VERSION 5.7 ;
  NOWIREEXTENSIONATPIN ON ;
  DIVIDERCHAR "/" ;
  BUSBITCHARS "[]" ;
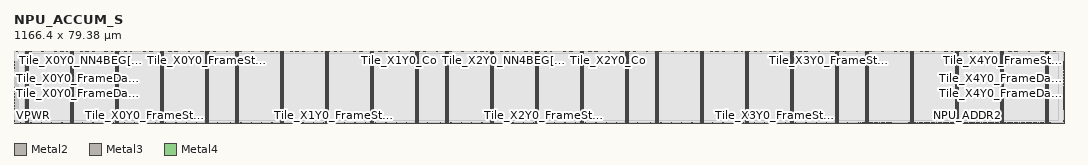
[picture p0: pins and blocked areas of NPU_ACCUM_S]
MACRO NPU_ACCUM_S
  CLASS BLOCK ;
  FOREIGN NPU_ACCUM_S ;
  ORIGIN 0.000 0.000 ;
  SIZE 1166.400 BY 79.380 ;
  PIN NPU_ADDR0
    DIRECTION OUTPUT ;
    USE SIGNAL ;
    ANTENNADIFFAREA 2.647800 ;
    PORT
      LAYER Metal2 ;
        RECT 1055.320 0.000 1055.720 0.400 ;
    END
  END NPU_ADDR0
  PIN NPU_ADDR1
    DIRECTION OUTPUT ;
    USE SIGNAL ;
    ANTENNADIFFAREA 2.647800 ;
    PORT
      LAYER Metal2 ;
        RECT 1057.240 0.000 1057.640 0.400 ;
    END
  END NPU_ADDR1
  PIN NPU_ADDR2
    DIRECTION OUTPUT ;
    USE SIGNAL ;
    ANTENNADIFFAREA 2.647800 ;
    PORT
      LAYER Metal2 ;
        RECT 1059.160 0.000 1059.560 0.400 ;
    END
  END NPU_ADDR2
  PIN NPU_ADDR3
    DIRECTION OUTPUT ;
    USE SIGNAL ;
    ANTENNADIFFAREA 2.647800 ;
    PORT
      LAYER Metal2 ;
        RECT 1061.080 0.000 1061.480 0.400 ;
    END
  END NPU_ADDR3
  PIN NPU_ADDR4
    DIRECTION OUTPUT ;
    USE SIGNAL ;
    ANTENNADIFFAREA 2.647800 ;
    PORT
      LAYER Metal2 ;
        RECT 1063.000 0.000 1063.400 0.400 ;
    END
  END NPU_ADDR4
  PIN NPU_ADDR5
    DIRECTION OUTPUT ;
    USE SIGNAL ;
    ANTENNADIFFAREA 2.647800 ;
    PORT
      LAYER Metal2 ;
        RECT 1064.920 0.000 1065.320 0.400 ;
    END
  END NPU_ADDR5
  PIN NPU_ADDR6
    DIRECTION OUTPUT ;
    USE SIGNAL ;
    ANTENNADIFFAREA 2.647800 ;
    PORT
      LAYER Metal2 ;
        RECT 1066.840 0.000 1067.240 0.400 ;
    END
  END NPU_ADDR6
  PIN NPU_ADDR7
    DIRECTION OUTPUT ;
    USE SIGNAL ;
    ANTENNADIFFAREA 2.647800 ;
    PORT
      LAYER Metal2 ;
        RECT 1068.760 0.000 1069.160 0.400 ;
    END
  END NPU_ADDR7
  PIN NPU_RDATA0
    DIRECTION INPUT ;
    USE SIGNAL ;
    ANTENNAGATEAREA 0.109200 ;
    ANTENNADIFFAREA 2.015400 ;
    PORT
      LAYER Metal2 ;
        RECT 993.880 0.000 994.280 0.400 ;
    END
  END NPU_RDATA0
  PIN NPU_RDATA1
    DIRECTION INPUT ;
    USE SIGNAL ;
    ANTENNAGATEAREA 0.109200 ;
    ANTENNADIFFAREA 2.015400 ;
    PORT
      LAYER Metal2 ;
        RECT 995.800 0.000 996.200 0.400 ;
    END
  END NPU_RDATA1
  PIN NPU_RDATA10
    DIRECTION INPUT ;
    USE SIGNAL ;
    ANTENNAGATEAREA 0.109200 ;
    ANTENNADIFFAREA 2.015400 ;
    PORT
      LAYER Metal2 ;
        RECT 1013.080 0.000 1013.480 0.400 ;
    END
  END NPU_RDATA10
  PIN NPU_RDATA11
    DIRECTION INPUT ;
    USE SIGNAL ;
    ANTENNAGATEAREA 0.109200 ;
    ANTENNADIFFAREA 2.015400 ;
    PORT
      LAYER Metal2 ;
        RECT 1015.000 0.000 1015.400 0.400 ;
    END
  END NPU_RDATA11
  PIN NPU_RDATA12
    DIRECTION INPUT ;
    USE SIGNAL ;
    ANTENNAGATEAREA 0.109200 ;
    ANTENNADIFFAREA 2.015400 ;
    PORT
      LAYER Metal2 ;
        RECT 1016.920 0.000 1017.320 0.400 ;
    END
  END NPU_RDATA12
  PIN NPU_RDATA13
    DIRECTION INPUT ;
    USE SIGNAL ;
    ANTENNAGATEAREA 0.109200 ;
    ANTENNADIFFAREA 2.015400 ;
    PORT
      LAYER Metal2 ;
        RECT 1018.840 0.000 1019.240 0.400 ;
    END
  END NPU_RDATA13
  PIN NPU_RDATA14
    DIRECTION INPUT ;
    USE SIGNAL ;
    ANTENNAGATEAREA 0.109200 ;
    ANTENNADIFFAREA 2.015400 ;
    PORT
      LAYER Metal2 ;
        RECT 1020.760 0.000 1021.160 0.400 ;
    END
  END NPU_RDATA14
  PIN NPU_RDATA15
    DIRECTION INPUT ;
    USE SIGNAL ;
    ANTENNAGATEAREA 0.109200 ;
    ANTENNADIFFAREA 2.015400 ;
    PORT
      LAYER Metal2 ;
        RECT 1022.680 0.000 1023.080 0.400 ;
    END
  END NPU_RDATA15
  PIN NPU_RDATA16
    DIRECTION INPUT ;
    USE SIGNAL ;
    ANTENNAGATEAREA 0.109200 ;
    ANTENNADIFFAREA 2.015400 ;
    PORT
      LAYER Metal2 ;
        RECT 1024.600 0.000 1025.000 0.400 ;
    END
  END NPU_RDATA16
  PIN NPU_RDATA17
    DIRECTION INPUT ;
    USE SIGNAL ;
    ANTENNAGATEAREA 0.109200 ;
    ANTENNADIFFAREA 2.015400 ;
    PORT
      LAYER Metal2 ;
        RECT 1026.520 0.000 1026.920 0.400 ;
    END
  END NPU_RDATA17
  PIN NPU_RDATA18
    DIRECTION INPUT ;
    USE SIGNAL ;
    ANTENNAGATEAREA 0.109200 ;
    ANTENNADIFFAREA 2.015400 ;
    PORT
      LAYER Metal2 ;
        RECT 1028.440 0.000 1028.840 0.400 ;
    END
  END NPU_RDATA18
  PIN NPU_RDATA19
    DIRECTION INPUT ;
    USE SIGNAL ;
    ANTENNAGATEAREA 0.109200 ;
    ANTENNADIFFAREA 2.015400 ;
    PORT
      LAYER Metal2 ;
        RECT 1030.360 0.000 1030.760 0.400 ;
    END
  END NPU_RDATA19
  PIN NPU_RDATA2
    DIRECTION INPUT ;
    USE SIGNAL ;
    ANTENNAGATEAREA 0.109200 ;
    ANTENNADIFFAREA 2.015400 ;
    PORT
      LAYER Metal2 ;
        RECT 997.720 0.000 998.120 0.400 ;
    END
  END NPU_RDATA2
  PIN NPU_RDATA20
    DIRECTION INPUT ;
    USE SIGNAL ;
    ANTENNAGATEAREA 0.109200 ;
    ANTENNADIFFAREA 2.015400 ;
    PORT
      LAYER Metal2 ;
        RECT 1032.280 0.000 1032.680 0.400 ;
    END
  END NPU_RDATA20
  PIN NPU_RDATA21
    DIRECTION INPUT ;
    USE SIGNAL ;
    ANTENNAGATEAREA 0.109200 ;
    ANTENNADIFFAREA 2.015400 ;
    PORT
      LAYER Metal2 ;
        RECT 1034.200 0.000 1034.600 0.400 ;
    END
  END NPU_RDATA21
  PIN NPU_RDATA22
    DIRECTION INPUT ;
    USE SIGNAL ;
    ANTENNAGATEAREA 0.109200 ;
    ANTENNADIFFAREA 2.015400 ;
    PORT
      LAYER Metal2 ;
        RECT 1036.120 0.000 1036.520 0.400 ;
    END
  END NPU_RDATA22
  PIN NPU_RDATA23
    DIRECTION INPUT ;
    USE SIGNAL ;
    ANTENNAGATEAREA 0.109200 ;
    ANTENNADIFFAREA 2.015400 ;
    PORT
      LAYER Metal2 ;
        RECT 1038.040 0.000 1038.440 0.400 ;
    END
  END NPU_RDATA23
  PIN NPU_RDATA24
    DIRECTION INPUT ;
    USE SIGNAL ;
    ANTENNAGATEAREA 0.109200 ;
    ANTENNADIFFAREA 2.015400 ;
    PORT
      LAYER Metal2 ;
        RECT 1039.960 0.000 1040.360 0.400 ;
    END
  END NPU_RDATA24
  PIN NPU_RDATA25
    DIRECTION INPUT ;
    USE SIGNAL ;
    ANTENNAGATEAREA 0.109200 ;
    ANTENNADIFFAREA 2.015400 ;
    PORT
      LAYER Metal2 ;
        RECT 1041.880 0.000 1042.280 0.400 ;
    END
  END NPU_RDATA25
  PIN NPU_RDATA26
    DIRECTION INPUT ;
    USE SIGNAL ;
    ANTENNAGATEAREA 0.109200 ;
    ANTENNADIFFAREA 2.015400 ;
    PORT
      LAYER Metal2 ;
        RECT 1043.800 0.000 1044.200 0.400 ;
    END
  END NPU_RDATA26
  PIN NPU_RDATA27
    DIRECTION INPUT ;
    USE SIGNAL ;
    ANTENNAGATEAREA 0.109200 ;
    ANTENNADIFFAREA 2.015400 ;
    PORT
      LAYER Metal2 ;
        RECT 1045.720 0.000 1046.120 0.400 ;
    END
  END NPU_RDATA27
  PIN NPU_RDATA28
    DIRECTION INPUT ;
    USE SIGNAL ;
    ANTENNAGATEAREA 0.109200 ;
    ANTENNADIFFAREA 2.015400 ;
    PORT
      LAYER Metal2 ;
        RECT 1047.640 0.000 1048.040 0.400 ;
    END
  END NPU_RDATA28
  PIN NPU_RDATA29
    DIRECTION INPUT ;
    USE SIGNAL ;
    ANTENNAGATEAREA 0.109200 ;
    ANTENNADIFFAREA 2.015400 ;
    PORT
      LAYER Metal2 ;
        RECT 1049.560 0.000 1049.960 0.400 ;
    END
  END NPU_RDATA29
  PIN NPU_RDATA3
    DIRECTION INPUT ;
    USE SIGNAL ;
    ANTENNAGATEAREA 0.109200 ;
    ANTENNADIFFAREA 2.015400 ;
    PORT
      LAYER Metal2 ;
        RECT 999.640 0.000 1000.040 0.400 ;
    END
  END NPU_RDATA3
  PIN NPU_RDATA30
    DIRECTION INPUT ;
    USE SIGNAL ;
    ANTENNAGATEAREA 0.109200 ;
    ANTENNADIFFAREA 2.015400 ;
    PORT
      LAYER Metal2 ;
        RECT 1051.480 0.000 1051.880 0.400 ;
    END
  END NPU_RDATA30
  PIN NPU_RDATA31
    DIRECTION INPUT ;
    USE SIGNAL ;
    ANTENNAGATEAREA 0.109200 ;
    ANTENNADIFFAREA 2.015400 ;
    PORT
      LAYER Metal2 ;
        RECT 1053.400 0.000 1053.800 0.400 ;
    END
  END NPU_RDATA31
  PIN NPU_RDATA4
    DIRECTION INPUT ;
    USE SIGNAL ;
    ANTENNAGATEAREA 0.109200 ;
    ANTENNADIFFAREA 2.015400 ;
    PORT
      LAYER Metal2 ;
        RECT 1001.560 0.000 1001.960 0.400 ;
    END
  END NPU_RDATA4
  PIN NPU_RDATA5
    DIRECTION INPUT ;
    USE SIGNAL ;
    ANTENNAGATEAREA 0.109200 ;
    ANTENNADIFFAREA 2.015400 ;
    PORT
      LAYER Metal2 ;
        RECT 1003.480 0.000 1003.880 0.400 ;
    END
  END NPU_RDATA5
  PIN NPU_RDATA6
    DIRECTION INPUT ;
    USE SIGNAL ;
    ANTENNAGATEAREA 0.109200 ;
    ANTENNADIFFAREA 2.015400 ;
    PORT
      LAYER Metal2 ;
        RECT 1005.400 0.000 1005.800 0.400 ;
    END
  END NPU_RDATA6
  PIN NPU_RDATA7
    DIRECTION INPUT ;
    USE SIGNAL ;
    ANTENNAGATEAREA 0.109200 ;
    ANTENNADIFFAREA 2.015400 ;
    PORT
      LAYER Metal2 ;
        RECT 1007.320 0.000 1007.720 0.400 ;
    END
  END NPU_RDATA7
  PIN NPU_RDATA8
    DIRECTION INPUT ;
    USE SIGNAL ;
    ANTENNAGATEAREA 0.109200 ;
    ANTENNADIFFAREA 2.015400 ;
    PORT
      LAYER Metal2 ;
        RECT 1009.240 0.000 1009.640 0.400 ;
    END
  END NPU_RDATA8
  PIN NPU_RDATA9
    DIRECTION INPUT ;
    USE SIGNAL ;
    ANTENNAGATEAREA 0.109200 ;
    ANTENNADIFFAREA 2.015400 ;
    PORT
      LAYER Metal2 ;
        RECT 1011.160 0.000 1011.560 0.400 ;
    END
  END NPU_RDATA9
  PIN NPU_READ_BANK_SEL0
    DIRECTION OUTPUT ;
    USE SIGNAL ;
    ANTENNADIFFAREA 2.647800 ;
    PORT
      LAYER Metal2 ;
        RECT 1147.480 0.000 1147.880 0.400 ;
    END
  END NPU_READ_BANK_SEL0
  PIN NPU_READ_BANK_SEL1
    DIRECTION OUTPUT ;
    USE SIGNAL ;
    ANTENNADIFFAREA 2.647800 ;
    PORT
      LAYER Metal2 ;
        RECT 1149.400 0.000 1149.800 0.400 ;
    END
  END NPU_READ_BANK_SEL1
  PIN NPU_READ_BANK_SEL2
    DIRECTION OUTPUT ;
    USE SIGNAL ;
    ANTENNADIFFAREA 2.647800 ;
    PORT
      LAYER Metal2 ;
        RECT 1151.320 0.000 1151.720 0.400 ;
    END
  END NPU_READ_BANK_SEL2
  PIN NPU_WDATA0
    DIRECTION OUTPUT ;
    USE SIGNAL ;
    ANTENNADIFFAREA 2.647800 ;
    PORT
      LAYER Metal2 ;
        RECT 1086.040 0.000 1086.440 0.400 ;
    END
  END NPU_WDATA0
  PIN NPU_WDATA1
    DIRECTION OUTPUT ;
    USE SIGNAL ;
    ANTENNADIFFAREA 2.647800 ;
    PORT
      LAYER Metal2 ;
        RECT 1087.960 0.000 1088.360 0.400 ;
    END
  END NPU_WDATA1
  PIN NPU_WDATA10
    DIRECTION OUTPUT ;
    USE SIGNAL ;
    ANTENNADIFFAREA 2.647800 ;
    PORT
      LAYER Metal2 ;
        RECT 1105.240 0.000 1105.640 0.400 ;
    END
  END NPU_WDATA10
  PIN NPU_WDATA11
    DIRECTION OUTPUT ;
    USE SIGNAL ;
    ANTENNADIFFAREA 2.647800 ;
    PORT
      LAYER Metal2 ;
        RECT 1107.160 0.000 1107.560 0.400 ;
    END
  END NPU_WDATA11
  PIN NPU_WDATA12
    DIRECTION OUTPUT ;
    USE SIGNAL ;
    ANTENNADIFFAREA 2.647800 ;
    PORT
      LAYER Metal2 ;
        RECT 1109.080 0.000 1109.480 0.400 ;
    END
  END NPU_WDATA12
  PIN NPU_WDATA13
    DIRECTION OUTPUT ;
    USE SIGNAL ;
    ANTENNADIFFAREA 2.647800 ;
    PORT
      LAYER Metal2 ;
        RECT 1111.000 0.000 1111.400 0.400 ;
    END
  END NPU_WDATA13
  PIN NPU_WDATA14
    DIRECTION OUTPUT ;
    USE SIGNAL ;
    ANTENNADIFFAREA 2.647800 ;
    PORT
      LAYER Metal2 ;
        RECT 1112.920 0.000 1113.320 0.400 ;
    END
  END NPU_WDATA14
  PIN NPU_WDATA15
    DIRECTION OUTPUT ;
    USE SIGNAL ;
    ANTENNADIFFAREA 2.647800 ;
    PORT
      LAYER Metal2 ;
        RECT 1114.840 0.000 1115.240 0.400 ;
    END
  END NPU_WDATA15
  PIN NPU_WDATA16
    DIRECTION OUTPUT ;
    USE SIGNAL ;
    ANTENNADIFFAREA 2.647800 ;
    PORT
      LAYER Metal2 ;
        RECT 1116.760 0.000 1117.160 0.400 ;
    END
  END NPU_WDATA16
  PIN NPU_WDATA17
    DIRECTION OUTPUT ;
    USE SIGNAL ;
    ANTENNADIFFAREA 2.647800 ;
    PORT
      LAYER Metal2 ;
        RECT 1118.680 0.000 1119.080 0.400 ;
    END
  END NPU_WDATA17
  PIN NPU_WDATA18
    DIRECTION OUTPUT ;
    USE SIGNAL ;
    ANTENNADIFFAREA 2.647800 ;
    PORT
      LAYER Metal2 ;
        RECT 1120.600 0.000 1121.000 0.400 ;
    END
  END NPU_WDATA18
  PIN NPU_WDATA19
    DIRECTION OUTPUT ;
    USE SIGNAL ;
    ANTENNADIFFAREA 2.647800 ;
    PORT
      LAYER Metal2 ;
        RECT 1122.520 0.000 1122.920 0.400 ;
    END
  END NPU_WDATA19
  PIN NPU_WDATA2
    DIRECTION OUTPUT ;
    USE SIGNAL ;
    ANTENNADIFFAREA 2.647800 ;
    PORT
      LAYER Metal2 ;
        RECT 1089.880 0.000 1090.280 0.400 ;
    END
  END NPU_WDATA2
  PIN NPU_WDATA20
    DIRECTION OUTPUT ;
    USE SIGNAL ;
    ANTENNADIFFAREA 2.647800 ;
    PORT
      LAYER Metal2 ;
        RECT 1124.440 0.000 1124.840 0.400 ;
    END
  END NPU_WDATA20
  PIN NPU_WDATA21
    DIRECTION OUTPUT ;
    USE SIGNAL ;
    ANTENNADIFFAREA 2.647800 ;
    PORT
      LAYER Metal2 ;
        RECT 1126.360 0.000 1126.760 0.400 ;
    END
  END NPU_WDATA21
  PIN NPU_WDATA22
    DIRECTION OUTPUT ;
    USE SIGNAL ;
    ANTENNADIFFAREA 2.647800 ;
    PORT
      LAYER Metal2 ;
        RECT 1128.280 0.000 1128.680 0.400 ;
    END
  END NPU_WDATA22
  PIN NPU_WDATA23
    DIRECTION OUTPUT ;
    USE SIGNAL ;
    ANTENNADIFFAREA 2.647800 ;
    PORT
      LAYER Metal2 ;
        RECT 1130.200 0.000 1130.600 0.400 ;
    END
  END NPU_WDATA23
  PIN NPU_WDATA24
    DIRECTION OUTPUT ;
    USE SIGNAL ;
    ANTENNADIFFAREA 2.647800 ;
    PORT
      LAYER Metal2 ;
        RECT 1132.120 0.000 1132.520 0.400 ;
    END
  END NPU_WDATA24
  PIN NPU_WDATA25
    DIRECTION OUTPUT ;
    USE SIGNAL ;
    ANTENNADIFFAREA 2.647800 ;
    PORT
      LAYER Metal2 ;
        RECT 1134.040 0.000 1134.440 0.400 ;
    END
  END NPU_WDATA25
  PIN NPU_WDATA26
    DIRECTION OUTPUT ;
    USE SIGNAL ;
    ANTENNADIFFAREA 2.647800 ;
    PORT
      LAYER Metal2 ;
        RECT 1135.960 0.000 1136.360 0.400 ;
    END
  END NPU_WDATA26
  PIN NPU_WDATA27
    DIRECTION OUTPUT ;
    USE SIGNAL ;
    ANTENNADIFFAREA 2.647800 ;
    PORT
      LAYER Metal2 ;
        RECT 1137.880 0.000 1138.280 0.400 ;
    END
  END NPU_WDATA27
  PIN NPU_WDATA28
    DIRECTION OUTPUT ;
    USE SIGNAL ;
    ANTENNADIFFAREA 2.647800 ;
    PORT
      LAYER Metal2 ;
        RECT 1139.800 0.000 1140.200 0.400 ;
    END
  END NPU_WDATA28
  PIN NPU_WDATA29
    DIRECTION OUTPUT ;
    USE SIGNAL ;
    ANTENNADIFFAREA 2.647800 ;
    PORT
      LAYER Metal2 ;
        RECT 1141.720 0.000 1142.120 0.400 ;
    END
  END NPU_WDATA29
  PIN NPU_WDATA3
    DIRECTION OUTPUT ;
    USE SIGNAL ;
    ANTENNADIFFAREA 2.647800 ;
    PORT
      LAYER Metal2 ;
        RECT 1091.800 0.000 1092.200 0.400 ;
    END
  END NPU_WDATA3
  PIN NPU_WDATA30
    DIRECTION OUTPUT ;
    USE SIGNAL ;
    ANTENNADIFFAREA 2.647800 ;
    PORT
      LAYER Metal2 ;
        RECT 1143.640 0.000 1144.040 0.400 ;
    END
  END NPU_WDATA30
  PIN NPU_WDATA31
    DIRECTION OUTPUT ;
    USE SIGNAL ;
    ANTENNADIFFAREA 2.647800 ;
    PORT
      LAYER Metal2 ;
        RECT 1145.560 0.000 1145.960 0.400 ;
    END
  END NPU_WDATA31
  PIN NPU_WDATA4
    DIRECTION OUTPUT ;
    USE SIGNAL ;
    ANTENNADIFFAREA 2.647800 ;
    PORT
      LAYER Metal2 ;
        RECT 1093.720 0.000 1094.120 0.400 ;
    END
  END NPU_WDATA4
  PIN NPU_WDATA5
    DIRECTION OUTPUT ;
    USE SIGNAL ;
    ANTENNADIFFAREA 2.647800 ;
    PORT
      LAYER Metal2 ;
        RECT 1095.640 0.000 1096.040 0.400 ;
    END
  END NPU_WDATA5
  PIN NPU_WDATA6
    DIRECTION OUTPUT ;
    USE SIGNAL ;
    ANTENNADIFFAREA 2.647800 ;
    PORT
      LAYER Metal2 ;
        RECT 1097.560 0.000 1097.960 0.400 ;
    END
  END NPU_WDATA6
  PIN NPU_WDATA7
    DIRECTION OUTPUT ;
    USE SIGNAL ;
    ANTENNADIFFAREA 2.647800 ;
    PORT
      LAYER Metal2 ;
        RECT 1099.480 0.000 1099.880 0.400 ;
    END
  END NPU_WDATA7
  PIN NPU_WDATA8
    DIRECTION OUTPUT ;
    USE SIGNAL ;
    ANTENNADIFFAREA 2.647800 ;
    PORT
      LAYER Metal2 ;
        RECT 1101.400 0.000 1101.800 0.400 ;
    END
  END NPU_WDATA8
  PIN NPU_WDATA9
    DIRECTION OUTPUT ;
    USE SIGNAL ;
    ANTENNADIFFAREA 2.647800 ;
    PORT
      LAYER Metal2 ;
        RECT 1103.320 0.000 1103.720 0.400 ;
    END
  END NPU_WDATA9
  PIN NPU_WE0
    DIRECTION OUTPUT ;
    USE SIGNAL ;
    ANTENNADIFFAREA 2.647800 ;
    PORT
      LAYER Metal2 ;
        RECT 1070.680 0.000 1071.080 0.400 ;
    END
  END NPU_WE0
  PIN NPU_WE1
    DIRECTION OUTPUT ;
    USE SIGNAL ;
    ANTENNADIFFAREA 2.647800 ;
    PORT
      LAYER Metal2 ;
        RECT 1072.600 0.000 1073.000 0.400 ;
    END
  END NPU_WE1
  PIN NPU_WE2
    DIRECTION OUTPUT ;
    USE SIGNAL ;
    ANTENNADIFFAREA 2.647800 ;
    PORT
      LAYER Metal2 ;
        RECT 1074.520 0.000 1074.920 0.400 ;
    END
  END NPU_WE2
  PIN NPU_WE3
    DIRECTION OUTPUT ;
    USE SIGNAL ;
    ANTENNADIFFAREA 2.647800 ;
    PORT
      LAYER Metal2 ;
        RECT 1076.440 0.000 1076.840 0.400 ;
    END
  END NPU_WE3
  PIN NPU_WE4
    DIRECTION OUTPUT ;
    USE SIGNAL ;
    ANTENNADIFFAREA 2.647800 ;
    PORT
      LAYER Metal2 ;
        RECT 1078.360 0.000 1078.760 0.400 ;
    END
  END NPU_WE4
  PIN NPU_WE5
    DIRECTION OUTPUT ;
    USE SIGNAL ;
    ANTENNADIFFAREA 2.647800 ;
    PORT
      LAYER Metal2 ;
        RECT 1080.280 0.000 1080.680 0.400 ;
    END
  END NPU_WE5
  PIN NPU_WE6
    DIRECTION OUTPUT ;
    USE SIGNAL ;
    ANTENNADIFFAREA 2.647800 ;
    PORT
      LAYER Metal2 ;
        RECT 1082.200 0.000 1082.600 0.400 ;
    END
  END NPU_WE6
  PIN NPU_WE7
    DIRECTION OUTPUT ;
    USE SIGNAL ;
    ANTENNADIFFAREA 2.647800 ;
    PORT
      LAYER Metal2 ;
        RECT 1084.120 0.000 1084.520 0.400 ;
    END
  END NPU_WE7
  PIN Tile_X0Y0_Co
    DIRECTION OUTPUT ;
    USE SIGNAL ;
    ANTENNADIFFAREA 2.314600 ;
    PORT
      LAYER Metal2 ;
        RECT 194.200 78.980 194.600 79.380 ;
    END
  END Tile_X0Y0_Co
  PIN Tile_X0Y0_FrameData[0]
    DIRECTION INPUT ;
    USE SIGNAL ;
    ANTENNAGATEAREA 2.349100 ;
    ANTENNADIFFAREA 78.600601 ;
    PORT
      LAYER Metal3 ;
        RECT 0.000 15.340 0.400 15.740 ;
    END
  END Tile_X0Y0_FrameData[0]
  PIN Tile_X0Y0_FrameData[10]
    DIRECTION INPUT ;
    USE SIGNAL ;
    ANTENNAGATEAREA 2.349100 ;
    ANTENNADIFFAREA 340.602600 ;
    PORT
      LAYER Metal3 ;
        RECT 0.000 32.140 0.400 32.540 ;
    END
  END Tile_X0Y0_FrameData[10]
  PIN Tile_X0Y0_FrameData[11]
    DIRECTION INPUT ;
    USE SIGNAL ;
    ANTENNAGATEAREA 2.349100 ;
    ANTENNADIFFAREA 235.801788 ;
    PORT
      LAYER Metal3 ;
        RECT 0.000 33.820 0.400 34.220 ;
    END
  END Tile_X0Y0_FrameData[11]
  PIN Tile_X0Y0_FrameData[12]
    DIRECTION INPUT ;
    USE SIGNAL ;
    ANTENNAGATEAREA 2.349100 ;
    ANTENNADIFFAREA 340.602600 ;
    PORT
      LAYER Metal3 ;
        RECT 0.000 35.500 0.400 35.900 ;
    END
  END Tile_X0Y0_FrameData[12]
  PIN Tile_X0Y0_FrameData[13]
    DIRECTION INPUT ;
    USE SIGNAL ;
    ANTENNAGATEAREA 2.349100 ;
    ANTENNADIFFAREA 52.400398 ;
    PORT
      LAYER Metal3 ;
        RECT 0.000 37.180 0.400 37.580 ;
    END
  END Tile_X0Y0_FrameData[13]
  PIN Tile_X0Y0_FrameData[14]
    DIRECTION INPUT ;
    USE SIGNAL ;
    ANTENNAGATEAREA 2.349100 ;
    ANTENNADIFFAREA 157.201202 ;
    PORT
      LAYER Metal3 ;
        RECT 0.000 38.860 0.400 39.260 ;
    END
  END Tile_X0Y0_FrameData[14]
  PIN Tile_X0Y0_FrameData[15]
    DIRECTION INPUT ;
    USE SIGNAL ;
    ANTENNAGATEAREA 2.349100 ;
    ANTENNADIFFAREA 340.602600 ;
    PORT
      LAYER Metal3 ;
        RECT 0.000 40.540 0.400 40.940 ;
    END
  END Tile_X0Y0_FrameData[15]
  PIN Tile_X0Y0_FrameData[16]
    DIRECTION INPUT ;
    USE SIGNAL ;
    ANTENNAGATEAREA 2.710500 ;
    ANTENNADIFFAREA 60.461998 ;
    PORT
      LAYER Metal3 ;
        RECT 0.000 42.220 0.400 42.620 ;
    END
  END Tile_X0Y0_FrameData[16]
  PIN Tile_X0Y0_FrameData[17]
    DIRECTION INPUT ;
    USE SIGNAL ;
    ANTENNAGATEAREA 2.710500 ;
    ANTENNADIFFAREA 453.464996 ;
    PORT
      LAYER Metal3 ;
        RECT 0.000 43.900 0.400 44.300 ;
    END
  END Tile_X0Y0_FrameData[17]
  PIN Tile_X0Y0_FrameData[18]
    DIRECTION INPUT ;
    USE SIGNAL ;
    ANTENNAGATEAREA 2.891200 ;
    ANTENNADIFFAREA 451.449585 ;
    PORT
      LAYER Metal3 ;
        RECT 0.000 45.580 0.400 45.980 ;
    END
  END Tile_X0Y0_FrameData[18]
  PIN Tile_X0Y0_FrameData[19]
    DIRECTION INPUT ;
    USE SIGNAL ;
    ANTENNAGATEAREA 2.891200 ;
    ANTENNADIFFAREA 193.478394 ;
    PORT
      LAYER Metal3 ;
        RECT 0.000 47.260 0.400 47.660 ;
    END
  END Tile_X0Y0_FrameData[19]
  PIN Tile_X0Y0_FrameData[1]
    DIRECTION INPUT ;
    USE SIGNAL ;
    ANTENNAGATEAREA 2.349100 ;
    ANTENNADIFFAREA 235.801788 ;
    PORT
      LAYER Metal3 ;
        RECT 0.000 17.020 0.400 17.420 ;
    END
  END Tile_X0Y0_FrameData[1]
  PIN Tile_X0Y0_FrameData[20]
    DIRECTION INPUT ;
    USE SIGNAL ;
    ANTENNAGATEAREA 2.891200 ;
    ANTENNADIFFAREA 515.942383 ;
    PORT
      LAYER Metal3 ;
        RECT 0.000 48.940 0.400 49.340 ;
    END
  END Tile_X0Y0_FrameData[20]
  PIN Tile_X0Y0_FrameData[21]
    DIRECTION INPUT ;
    USE SIGNAL ;
    ANTENNAGATEAREA 2.891200 ;
    ANTENNADIFFAREA 128.985596 ;
    PORT
      LAYER Metal3 ;
        RECT 0.000 50.620 0.400 51.020 ;
    END
  END Tile_X0Y0_FrameData[21]
  PIN Tile_X0Y0_FrameData[22]
    DIRECTION INPUT ;
    USE SIGNAL ;
    ANTENNAGATEAREA 2.891200 ;
    ANTENNADIFFAREA 386.956787 ;
    PORT
      LAYER Metal3 ;
        RECT 0.000 52.300 0.400 52.700 ;
    END
  END Tile_X0Y0_FrameData[22]
  PIN Tile_X0Y0_FrameData[23]
    DIRECTION INPUT ;
    USE SIGNAL ;
    ANTENNAGATEAREA 2.891200 ;
    ANTENNADIFFAREA 32.246399 ;
    PORT
      LAYER Metal3 ;
        RECT 0.000 53.980 0.400 54.380 ;
    END
  END Tile_X0Y0_FrameData[23]
  PIN Tile_X0Y0_FrameData[24]
    DIRECTION INPUT ;
    USE SIGNAL ;
    ANTENNAGATEAREA 2.891200 ;
    ANTENNADIFFAREA 419.203186 ;
    PORT
      LAYER Metal3 ;
        RECT 0.000 55.660 0.400 56.060 ;
    END
  END Tile_X0Y0_FrameData[24]
  PIN Tile_X0Y0_FrameData[25]
    DIRECTION INPUT ;
    USE SIGNAL ;
    ANTENNAGATEAREA 2.891200 ;
    ANTENNADIFFAREA 64.492798 ;
    PORT
      LAYER Metal3 ;
        RECT 0.000 57.340 0.400 57.740 ;
    END
  END Tile_X0Y0_FrameData[25]
  PIN Tile_X0Y0_FrameData[26]
    DIRECTION INPUT ;
    USE SIGNAL ;
    ANTENNAGATEAREA 2.891200 ;
    ANTENNADIFFAREA 193.478394 ;
    PORT
      LAYER Metal3 ;
        RECT 0.000 59.020 0.400 59.420 ;
    END
  END Tile_X0Y0_FrameData[26]
  PIN Tile_X0Y0_FrameData[27]
    DIRECTION INPUT ;
    USE SIGNAL ;
    ANTENNAGATEAREA 2.891200 ;
    ANTENNADIFFAREA 515.942383 ;
    PORT
      LAYER Metal3 ;
        RECT 0.000 60.700 0.400 61.100 ;
    END
  END Tile_X0Y0_FrameData[27]
  PIN Tile_X0Y0_FrameData[28]
    DIRECTION INPUT ;
    USE SIGNAL ;
    ANTENNAGATEAREA 2.891200 ;
    ANTENNADIFFAREA 344.633392 ;
    PORT
      LAYER Metal3 ;
        RECT 0.000 62.380 0.400 62.780 ;
    END
  END Tile_X0Y0_FrameData[28]
  PIN Tile_X0Y0_FrameData[29]
    DIRECTION INPUT ;
    USE SIGNAL ;
    ANTENNAGATEAREA 2.891200 ;
    ANTENNADIFFAREA 163.247391 ;
    PORT
      LAYER Metal3 ;
        RECT 0.000 64.060 0.400 64.460 ;
    END
  END Tile_X0Y0_FrameData[29]
  PIN Tile_X0Y0_FrameData[2]
    DIRECTION INPUT ;
    USE SIGNAL ;
    ANTENNAGATEAREA 2.349100 ;
    ANTENNADIFFAREA 102.785400 ;
    PORT
      LAYER Metal3 ;
        RECT 0.000 18.700 0.400 19.100 ;
    END
  END Tile_X0Y0_FrameData[2]
  PIN Tile_X0Y0_FrameData[30]
    DIRECTION INPUT ;
    USE SIGNAL ;
    ANTENNAGATEAREA 2.891200 ;
    ANTENNADIFFAREA 72.554398 ;
    PORT
      LAYER Metal3 ;
        RECT 0.000 65.740 0.400 66.140 ;
    END
  END Tile_X0Y0_FrameData[30]
  PIN Tile_X0Y0_FrameData[31]
    DIRECTION INPUT ;
    USE SIGNAL ;
    ANTENNAGATEAREA 2.891200 ;
    ANTENNADIFFAREA 515.942383 ;
    PORT
      LAYER Metal3 ;
        RECT 0.000 67.420 0.400 67.820 ;
    END
  END Tile_X0Y0_FrameData[31]
  PIN Tile_X0Y0_FrameData[3]
    DIRECTION INPUT ;
    USE SIGNAL ;
    ANTENNAGATEAREA 2.349100 ;
    PORT
      LAYER Metal3 ;
        RECT 0.000 20.380 0.400 20.780 ;
    END
  END Tile_X0Y0_FrameData[3]
  PIN Tile_X0Y0_FrameData[4]
    DIRECTION INPUT ;
    USE SIGNAL ;
    ANTENNAGATEAREA 2.349100 ;
    ANTENNADIFFAREA 340.602600 ;
    PORT
      LAYER Metal3 ;
        RECT 0.000 22.060 0.400 22.460 ;
    END
  END Tile_X0Y0_FrameData[4]
  PIN Tile_X0Y0_FrameData[5]
    DIRECTION INPUT ;
    USE SIGNAL ;
    ANTENNAGATEAREA 2.349100 ;
    ANTENNADIFFAREA 52.400398 ;
    PORT
      LAYER Metal3 ;
        RECT 0.000 23.740 0.400 24.140 ;
    END
  END Tile_X0Y0_FrameData[5]
  PIN Tile_X0Y0_FrameData[6]
    DIRECTION INPUT ;
    USE SIGNAL ;
    ANTENNAGATEAREA 2.349100 ;
    ANTENNADIFFAREA 340.602600 ;
    PORT
      LAYER Metal3 ;
        RECT 0.000 25.420 0.400 25.820 ;
    END
  END Tile_X0Y0_FrameData[6]
  PIN Tile_X0Y0_FrameData[7]
    DIRECTION INPUT ;
    USE SIGNAL ;
    ANTENNAGATEAREA 2.349100 ;
    ANTENNADIFFAREA 235.801788 ;
    PORT
      LAYER Metal3 ;
        RECT 0.000 27.100 0.400 27.500 ;
    END
  END Tile_X0Y0_FrameData[7]
  PIN Tile_X0Y0_FrameData[8]
    DIRECTION INPUT ;
    USE SIGNAL ;
    ANTENNAGATEAREA 2.349100 ;
    ANTENNADIFFAREA 340.602600 ;
    PORT
      LAYER Metal3 ;
        RECT 0.000 28.780 0.400 29.180 ;
    END
  END Tile_X0Y0_FrameData[8]
  PIN Tile_X0Y0_FrameData[9]
    DIRECTION INPUT ;
    USE SIGNAL ;
    ANTENNAGATEAREA 2.349100 ;
    ANTENNADIFFAREA 340.602600 ;
    PORT
      LAYER Metal3 ;
        RECT 0.000 30.460 0.400 30.860 ;
    END
  END Tile_X0Y0_FrameData[9]
  PIN Tile_X0Y0_FrameStrobe[0]
    DIRECTION INPUT ;
    USE SIGNAL ;
    ANTENNAGATEAREA 11.745500 ;
    PORT
      LAYER Metal2 ;
        RECT 7.000 0.000 7.400 0.400 ;
    END
  END Tile_X0Y0_FrameStrobe[0]
  PIN Tile_X0Y0_FrameStrobe[10]
    DIRECTION INPUT ;
    USE SIGNAL ;
    ANTENNAGATEAREA 0.180700 ;
    PORT
      LAYER Metal2 ;
        RECT 122.200 0.000 122.600 0.400 ;
    END
  END Tile_X0Y0_FrameStrobe[10]
  PIN Tile_X0Y0_FrameStrobe[11]
    DIRECTION INPUT ;
    USE SIGNAL ;
    ANTENNAGATEAREA 0.180700 ;
    PORT
      LAYER Metal2 ;
        RECT 133.720 0.000 134.120 0.400 ;
    END
  END Tile_X0Y0_FrameStrobe[11]
  PIN Tile_X0Y0_FrameStrobe[12]
    DIRECTION INPUT ;
    USE SIGNAL ;
    ANTENNAGATEAREA 0.180700 ;
    PORT
      LAYER Metal2 ;
        RECT 145.240 0.000 145.640 0.400 ;
    END
  END Tile_X0Y0_FrameStrobe[12]
  PIN Tile_X0Y0_FrameStrobe[13]
    DIRECTION INPUT ;
    USE SIGNAL ;
    ANTENNAGATEAREA 0.180700 ;
    PORT
      LAYER Metal2 ;
        RECT 156.760 0.000 157.160 0.400 ;
    END
  END Tile_X0Y0_FrameStrobe[13]
  PIN Tile_X0Y0_FrameStrobe[14]
    DIRECTION INPUT ;
    USE SIGNAL ;
    ANTENNAGATEAREA 0.180700 ;
    PORT
      LAYER Metal2 ;
        RECT 168.280 0.000 168.680 0.400 ;
    END
  END Tile_X0Y0_FrameStrobe[14]
  PIN Tile_X0Y0_FrameStrobe[15]
    DIRECTION INPUT ;
    USE SIGNAL ;
    ANTENNAGATEAREA 0.180700 ;
    PORT
      LAYER Metal2 ;
        RECT 179.800 0.000 180.200 0.400 ;
    END
  END Tile_X0Y0_FrameStrobe[15]
  PIN Tile_X0Y0_FrameStrobe[16]
    DIRECTION INPUT ;
    USE SIGNAL ;
    ANTENNAGATEAREA 0.180700 ;
    PORT
      LAYER Metal2 ;
        RECT 191.320 0.000 191.720 0.400 ;
    END
  END Tile_X0Y0_FrameStrobe[16]
  PIN Tile_X0Y0_FrameStrobe[17]
    DIRECTION INPUT ;
    USE SIGNAL ;
    ANTENNAGATEAREA 0.180700 ;
    PORT
      LAYER Metal2 ;
        RECT 202.840 0.000 203.240 0.400 ;
    END
  END Tile_X0Y0_FrameStrobe[17]
  PIN Tile_X0Y0_FrameStrobe[18]
    DIRECTION INPUT ;
    USE SIGNAL ;
    ANTENNAGATEAREA 0.180700 ;
    PORT
      LAYER Metal2 ;
        RECT 214.360 0.000 214.760 0.400 ;
    END
  END Tile_X0Y0_FrameStrobe[18]
  PIN Tile_X0Y0_FrameStrobe[19]
    DIRECTION INPUT ;
    USE SIGNAL ;
    ANTENNAGATEAREA 0.180700 ;
    PORT
      LAYER Metal2 ;
        RECT 225.880 0.000 226.280 0.400 ;
    END
  END Tile_X0Y0_FrameStrobe[19]
  PIN Tile_X0Y0_FrameStrobe[1]
    DIRECTION INPUT ;
    USE SIGNAL ;
    ANTENNAGATEAREA 11.745500 ;
    PORT
      LAYER Metal2 ;
        RECT 18.520 0.000 18.920 0.400 ;
    END
  END Tile_X0Y0_FrameStrobe[1]
  PIN Tile_X0Y0_FrameStrobe[2]
    DIRECTION INPUT ;
    USE SIGNAL ;
    ANTENNAGATEAREA 11.745500 ;
    PORT
      LAYER Metal2 ;
        RECT 30.040 0.000 30.440 0.400 ;
    END
  END Tile_X0Y0_FrameStrobe[2]
  PIN Tile_X0Y0_FrameStrobe[3]
    DIRECTION INPUT ;
    USE SIGNAL ;
    ANTENNAGATEAREA 5.963100 ;
    PORT
      LAYER Metal2 ;
        RECT 41.560 0.000 41.960 0.400 ;
    END
  END Tile_X0Y0_FrameStrobe[3]
  PIN Tile_X0Y0_FrameStrobe[4]
    DIRECTION INPUT ;
    USE SIGNAL ;
    ANTENNAGATEAREA 0.180700 ;
    PORT
      LAYER Metal2 ;
        RECT 53.080 0.000 53.480 0.400 ;
    END
  END Tile_X0Y0_FrameStrobe[4]
  PIN Tile_X0Y0_FrameStrobe[5]
    DIRECTION INPUT ;
    USE SIGNAL ;
    ANTENNAGATEAREA 0.180700 ;
    PORT
      LAYER Metal2 ;
        RECT 64.600 0.000 65.000 0.400 ;
    END
  END Tile_X0Y0_FrameStrobe[5]
  PIN Tile_X0Y0_FrameStrobe[6]
    DIRECTION INPUT ;
    USE SIGNAL ;
    ANTENNAGATEAREA 0.180700 ;
    PORT
      LAYER Metal2 ;
        RECT 76.120 0.000 76.520 0.400 ;
    END
  END Tile_X0Y0_FrameStrobe[6]
  PIN Tile_X0Y0_FrameStrobe[7]
    DIRECTION INPUT ;
    USE SIGNAL ;
    ANTENNAGATEAREA 0.180700 ;
    PORT
      LAYER Metal2 ;
        RECT 87.640 0.000 88.040 0.400 ;
    END
  END Tile_X0Y0_FrameStrobe[7]
  PIN Tile_X0Y0_FrameStrobe[8]
    DIRECTION INPUT ;
    USE SIGNAL ;
    ANTENNAGATEAREA 0.180700 ;
    PORT
      LAYER Metal2 ;
        RECT 99.160 0.000 99.560 0.400 ;
    END
  END Tile_X0Y0_FrameStrobe[8]
  PIN Tile_X0Y0_FrameStrobe[9]
    DIRECTION INPUT ;
    USE SIGNAL ;
    ANTENNAGATEAREA 0.180700 ;
    PORT
      LAYER Metal2 ;
        RECT 110.680 0.000 111.080 0.400 ;
    END
  END Tile_X0Y0_FrameStrobe[9]
  PIN Tile_X0Y0_FrameStrobe_O[0]
    DIRECTION OUTPUT ;
    USE SIGNAL ;
    ANTENNADIFFAREA 2.724000 ;
    PORT
      LAYER Metal2 ;
        RECT 204.760 78.980 205.160 79.380 ;
    END
  END Tile_X0Y0_FrameStrobe_O[0]
  PIN Tile_X0Y0_FrameStrobe_O[10]
    DIRECTION OUTPUT ;
    USE SIGNAL ;
    ANTENNADIFFAREA 2.724000 ;
    PORT
      LAYER Metal2 ;
        RECT 214.360 78.980 214.760 79.380 ;
    END
  END Tile_X0Y0_FrameStrobe_O[10]
  PIN Tile_X0Y0_FrameStrobe_O[11]
    DIRECTION OUTPUT ;
    USE SIGNAL ;
    ANTENNADIFFAREA 2.724000 ;
    PORT
      LAYER Metal2 ;
        RECT 215.320 78.980 215.720 79.380 ;
    END
  END Tile_X0Y0_FrameStrobe_O[11]
  PIN Tile_X0Y0_FrameStrobe_O[12]
    DIRECTION OUTPUT ;
    USE SIGNAL ;
    ANTENNADIFFAREA 2.724000 ;
    PORT
      LAYER Metal2 ;
        RECT 216.280 78.980 216.680 79.380 ;
    END
  END Tile_X0Y0_FrameStrobe_O[12]
  PIN Tile_X0Y0_FrameStrobe_O[13]
    DIRECTION OUTPUT ;
    USE SIGNAL ;
    ANTENNADIFFAREA 2.724000 ;
    PORT
      LAYER Metal2 ;
        RECT 217.240 78.980 217.640 79.380 ;
    END
  END Tile_X0Y0_FrameStrobe_O[13]
  PIN Tile_X0Y0_FrameStrobe_O[14]
    DIRECTION OUTPUT ;
    USE SIGNAL ;
    ANTENNADIFFAREA 2.724000 ;
    PORT
      LAYER Metal2 ;
        RECT 218.200 78.980 218.600 79.380 ;
    END
  END Tile_X0Y0_FrameStrobe_O[14]
  PIN Tile_X0Y0_FrameStrobe_O[15]
    DIRECTION OUTPUT ;
    USE SIGNAL ;
    ANTENNADIFFAREA 2.724000 ;
    PORT
      LAYER Metal2 ;
        RECT 219.160 78.980 219.560 79.380 ;
    END
  END Tile_X0Y0_FrameStrobe_O[15]
  PIN Tile_X0Y0_FrameStrobe_O[16]
    DIRECTION OUTPUT ;
    USE SIGNAL ;
    ANTENNADIFFAREA 2.724000 ;
    PORT
      LAYER Metal2 ;
        RECT 220.120 78.980 220.520 79.380 ;
    END
  END Tile_X0Y0_FrameStrobe_O[16]
  PIN Tile_X0Y0_FrameStrobe_O[17]
    DIRECTION OUTPUT ;
    USE SIGNAL ;
    ANTENNADIFFAREA 2.724000 ;
    PORT
      LAYER Metal2 ;
        RECT 221.080 78.980 221.480 79.380 ;
    END
  END Tile_X0Y0_FrameStrobe_O[17]
  PIN Tile_X0Y0_FrameStrobe_O[18]
    DIRECTION OUTPUT ;
    USE SIGNAL ;
    ANTENNADIFFAREA 2.724000 ;
    PORT
      LAYER Metal2 ;
        RECT 222.040 78.980 222.440 79.380 ;
    END
  END Tile_X0Y0_FrameStrobe_O[18]
  PIN Tile_X0Y0_FrameStrobe_O[19]
    DIRECTION OUTPUT ;
    USE SIGNAL ;
    ANTENNADIFFAREA 2.724000 ;
    PORT
      LAYER Metal2 ;
        RECT 223.000 78.980 223.400 79.380 ;
    END
  END Tile_X0Y0_FrameStrobe_O[19]
  PIN Tile_X0Y0_FrameStrobe_O[1]
    DIRECTION OUTPUT ;
    USE SIGNAL ;
    ANTENNADIFFAREA 2.724000 ;
    PORT
      LAYER Metal2 ;
        RECT 205.720 78.980 206.120 79.380 ;
    END
  END Tile_X0Y0_FrameStrobe_O[1]
  PIN Tile_X0Y0_FrameStrobe_O[2]
    DIRECTION OUTPUT ;
    USE SIGNAL ;
    ANTENNADIFFAREA 2.724000 ;
    PORT
      LAYER Metal2 ;
        RECT 206.680 78.980 207.080 79.380 ;
    END
  END Tile_X0Y0_FrameStrobe_O[2]
  PIN Tile_X0Y0_FrameStrobe_O[3]
    DIRECTION OUTPUT ;
    USE SIGNAL ;
    ANTENNADIFFAREA 2.724000 ;
    PORT
      LAYER Metal2 ;
        RECT 207.640 78.980 208.040 79.380 ;
    END
  END Tile_X0Y0_FrameStrobe_O[3]
  PIN Tile_X0Y0_FrameStrobe_O[4]
    DIRECTION OUTPUT ;
    USE SIGNAL ;
    ANTENNADIFFAREA 2.724000 ;
    PORT
      LAYER Metal2 ;
        RECT 208.600 78.980 209.000 79.380 ;
    END
  END Tile_X0Y0_FrameStrobe_O[4]
  PIN Tile_X0Y0_FrameStrobe_O[5]
    DIRECTION OUTPUT ;
    USE SIGNAL ;
    ANTENNADIFFAREA 2.724000 ;
    PORT
      LAYER Metal2 ;
        RECT 209.560 78.980 209.960 79.380 ;
    END
  END Tile_X0Y0_FrameStrobe_O[5]
  PIN Tile_X0Y0_FrameStrobe_O[6]
    DIRECTION OUTPUT ;
    USE SIGNAL ;
    ANTENNADIFFAREA 2.724000 ;
    PORT
      LAYER Metal2 ;
        RECT 210.520 78.980 210.920 79.380 ;
    END
  END Tile_X0Y0_FrameStrobe_O[6]
  PIN Tile_X0Y0_FrameStrobe_O[7]
    DIRECTION OUTPUT ;
    USE SIGNAL ;
    ANTENNADIFFAREA 2.724000 ;
    PORT
      LAYER Metal2 ;
        RECT 211.480 78.980 211.880 79.380 ;
    END
  END Tile_X0Y0_FrameStrobe_O[7]
  PIN Tile_X0Y0_FrameStrobe_O[8]
    DIRECTION OUTPUT ;
    USE SIGNAL ;
    ANTENNADIFFAREA 2.724000 ;
    PORT
      LAYER Metal2 ;
        RECT 212.440 78.980 212.840 79.380 ;
    END
  END Tile_X0Y0_FrameStrobe_O[8]
  PIN Tile_X0Y0_FrameStrobe_O[9]
    DIRECTION OUTPUT ;
    USE SIGNAL ;
    ANTENNADIFFAREA 2.724000 ;
    PORT
      LAYER Metal2 ;
        RECT 213.400 78.980 213.800 79.380 ;
    END
  END Tile_X0Y0_FrameStrobe_O[9]
  PIN Tile_X0Y0_N1BEG[0]
    DIRECTION OUTPUT ;
    USE SIGNAL ;
    ANTENNADIFFAREA 2.724000 ;
    PORT
      LAYER Metal2 ;
        RECT 1.240 78.980 1.640 79.380 ;
    END
  END Tile_X0Y0_N1BEG[0]
  PIN Tile_X0Y0_N1BEG[1]
    DIRECTION OUTPUT ;
    USE SIGNAL ;
    ANTENNADIFFAREA 2.724000 ;
    PORT
      LAYER Metal2 ;
        RECT 3.160 78.980 3.560 79.380 ;
    END
  END Tile_X0Y0_N1BEG[1]
  PIN Tile_X0Y0_N1BEG[2]
    DIRECTION OUTPUT ;
    USE SIGNAL ;
    ANTENNADIFFAREA 2.724000 ;
    PORT
      LAYER Metal2 ;
        RECT 5.080 78.980 5.480 79.380 ;
    END
  END Tile_X0Y0_N1BEG[2]
  PIN Tile_X0Y0_N1BEG[3]
    DIRECTION OUTPUT ;
    USE SIGNAL ;
    ANTENNADIFFAREA 2.724000 ;
    PORT
      LAYER Metal2 ;
        RECT 7.000 78.980 7.400 79.380 ;
    END
  END Tile_X0Y0_N1BEG[3]
  PIN Tile_X0Y0_N2BEG[0]
    DIRECTION OUTPUT ;
    USE SIGNAL ;
    ANTENNADIFFAREA 2.724000 ;
    PORT
      LAYER Metal2 ;
        RECT 11.800 78.980 12.200 79.380 ;
    END
  END Tile_X0Y0_N2BEG[0]
  PIN Tile_X0Y0_N2BEG[1]
    DIRECTION OUTPUT ;
    USE SIGNAL ;
    ANTENNADIFFAREA 2.724000 ;
    PORT
      LAYER Metal2 ;
        RECT 12.760 78.980 13.160 79.380 ;
    END
  END Tile_X0Y0_N2BEG[1]
  PIN Tile_X0Y0_N2BEG[2]
    DIRECTION OUTPUT ;
    USE SIGNAL ;
    ANTENNADIFFAREA 2.724000 ;
    PORT
      LAYER Metal2 ;
        RECT 13.720 78.980 14.120 79.380 ;
    END
  END Tile_X0Y0_N2BEG[2]
  PIN Tile_X0Y0_N2BEG[3]
    DIRECTION OUTPUT ;
    USE SIGNAL ;
    ANTENNADIFFAREA 2.724000 ;
    PORT
      LAYER Metal2 ;
        RECT 14.680 78.980 15.080 79.380 ;
    END
  END Tile_X0Y0_N2BEG[3]
  PIN Tile_X0Y0_N2BEG[4]
    DIRECTION OUTPUT ;
    USE SIGNAL ;
    ANTENNADIFFAREA 2.724000 ;
    PORT
      LAYER Metal2 ;
        RECT 15.640 78.980 16.040 79.380 ;
    END
  END Tile_X0Y0_N2BEG[4]
  PIN Tile_X0Y0_N2BEG[5]
    DIRECTION OUTPUT ;
    USE SIGNAL ;
    ANTENNADIFFAREA 2.724000 ;
    PORT
      LAYER Metal2 ;
        RECT 16.600 78.980 17.000 79.380 ;
    END
  END Tile_X0Y0_N2BEG[5]
  PIN Tile_X0Y0_N2BEG[6]
    DIRECTION OUTPUT ;
    USE SIGNAL ;
    ANTENNADIFFAREA 2.724000 ;
    PORT
      LAYER Metal2 ;
        RECT 17.560 78.980 17.960 79.380 ;
    END
  END Tile_X0Y0_N2BEG[6]
  PIN Tile_X0Y0_N2BEG[7]
    DIRECTION OUTPUT ;
    USE SIGNAL ;
    ANTENNADIFFAREA 2.724000 ;
    PORT
      LAYER Metal2 ;
        RECT 18.520 78.980 18.920 79.380 ;
    END
  END Tile_X0Y0_N2BEG[7]
  PIN Tile_X0Y0_N2BEGb[0]
    DIRECTION OUTPUT ;
    USE SIGNAL ;
    ANTENNADIFFAREA 2.724000 ;
    PORT
      LAYER Metal2 ;
        RECT 26.200 78.980 26.600 79.380 ;
    END
  END Tile_X0Y0_N2BEGb[0]
  PIN Tile_X0Y0_N2BEGb[1]
    DIRECTION OUTPUT ;
    USE SIGNAL ;
    ANTENNADIFFAREA 2.724000 ;
    PORT
      LAYER Metal2 ;
        RECT 27.160 78.980 27.560 79.380 ;
    END
  END Tile_X0Y0_N2BEGb[1]
  PIN Tile_X0Y0_N2BEGb[2]
    DIRECTION OUTPUT ;
    USE SIGNAL ;
    ANTENNADIFFAREA 2.724000 ;
    PORT
      LAYER Metal2 ;
        RECT 28.120 78.980 28.520 79.380 ;
    END
  END Tile_X0Y0_N2BEGb[2]
  PIN Tile_X0Y0_N2BEGb[3]
    DIRECTION OUTPUT ;
    USE SIGNAL ;
    ANTENNADIFFAREA 2.724000 ;
    PORT
      LAYER Metal2 ;
        RECT 29.080 78.980 29.480 79.380 ;
    END
  END Tile_X0Y0_N2BEGb[3]
  PIN Tile_X0Y0_N2BEGb[4]
    DIRECTION OUTPUT ;
    USE SIGNAL ;
    ANTENNADIFFAREA 2.724000 ;
    PORT
      LAYER Metal2 ;
        RECT 30.040 78.980 30.440 79.380 ;
    END
  END Tile_X0Y0_N2BEGb[4]
  PIN Tile_X0Y0_N2BEGb[5]
    DIRECTION OUTPUT ;
    USE SIGNAL ;
    ANTENNADIFFAREA 2.724000 ;
    PORT
      LAYER Metal2 ;
        RECT 31.000 78.980 31.400 79.380 ;
    END
  END Tile_X0Y0_N2BEGb[5]
  PIN Tile_X0Y0_N2BEGb[6]
    DIRECTION OUTPUT ;
    USE SIGNAL ;
    ANTENNADIFFAREA 2.724000 ;
    PORT
      LAYER Metal2 ;
        RECT 31.960 78.980 32.360 79.380 ;
    END
  END Tile_X0Y0_N2BEGb[6]
  PIN Tile_X0Y0_N2BEGb[7]
    DIRECTION OUTPUT ;
    USE SIGNAL ;
    ANTENNADIFFAREA 2.724000 ;
    PORT
      LAYER Metal2 ;
        RECT 32.920 78.980 33.320 79.380 ;
    END
  END Tile_X0Y0_N2BEGb[7]
  PIN Tile_X0Y0_N4BEG[0]
    DIRECTION OUTPUT ;
    USE SIGNAL ;
    ANTENNADIFFAREA 2.724000 ;
    PORT
      LAYER Metal2 ;
        RECT 44.440 78.980 44.840 79.380 ;
    END
  END Tile_X0Y0_N4BEG[0]
  PIN Tile_X0Y0_N4BEG[10]
    DIRECTION OUTPUT ;
    USE SIGNAL ;
    ANTENNADIFFAREA 2.724000 ;
    PORT
      LAYER Metal2 ;
        RECT 54.040 78.980 54.440 79.380 ;
    END
  END Tile_X0Y0_N4BEG[10]
  PIN Tile_X0Y0_N4BEG[11]
    DIRECTION OUTPUT ;
    USE SIGNAL ;
    ANTENNADIFFAREA 2.724000 ;
    PORT
      LAYER Metal2 ;
        RECT 55.000 78.980 55.400 79.380 ;
    END
  END Tile_X0Y0_N4BEG[11]
  PIN Tile_X0Y0_N4BEG[12]
    DIRECTION OUTPUT ;
    USE SIGNAL ;
    ANTENNADIFFAREA 2.724000 ;
    PORT
      LAYER Metal2 ;
        RECT 55.960 78.980 56.360 79.380 ;
    END
  END Tile_X0Y0_N4BEG[12]
  PIN Tile_X0Y0_N4BEG[13]
    DIRECTION OUTPUT ;
    USE SIGNAL ;
    ANTENNADIFFAREA 2.724000 ;
    PORT
      LAYER Metal2 ;
        RECT 56.920 78.980 57.320 79.380 ;
    END
  END Tile_X0Y0_N4BEG[13]
  PIN Tile_X0Y0_N4BEG[14]
    DIRECTION OUTPUT ;
    USE SIGNAL ;
    ANTENNADIFFAREA 2.724000 ;
    PORT
      LAYER Metal2 ;
        RECT 57.880 78.980 58.280 79.380 ;
    END
  END Tile_X0Y0_N4BEG[14]
  PIN Tile_X0Y0_N4BEG[15]
    DIRECTION OUTPUT ;
    USE SIGNAL ;
    ANTENNADIFFAREA 2.724000 ;
    PORT
      LAYER Metal2 ;
        RECT 58.840 78.980 59.240 79.380 ;
    END
  END Tile_X0Y0_N4BEG[15]
  PIN Tile_X0Y0_N4BEG[1]
    DIRECTION OUTPUT ;
    USE SIGNAL ;
    ANTENNADIFFAREA 2.724000 ;
    PORT
      LAYER Metal2 ;
        RECT 45.400 78.980 45.800 79.380 ;
    END
  END Tile_X0Y0_N4BEG[1]
  PIN Tile_X0Y0_N4BEG[2]
    DIRECTION OUTPUT ;
    USE SIGNAL ;
    ANTENNADIFFAREA 2.724000 ;
    PORT
      LAYER Metal2 ;
        RECT 46.360 78.980 46.760 79.380 ;
    END
  END Tile_X0Y0_N4BEG[2]
  PIN Tile_X0Y0_N4BEG[3]
    DIRECTION OUTPUT ;
    USE SIGNAL ;
    ANTENNADIFFAREA 2.724000 ;
    PORT
      LAYER Metal2 ;
        RECT 47.320 78.980 47.720 79.380 ;
    END
  END Tile_X0Y0_N4BEG[3]
  PIN Tile_X0Y0_N4BEG[4]
    DIRECTION OUTPUT ;
    USE SIGNAL ;
    ANTENNADIFFAREA 2.724000 ;
    PORT
      LAYER Metal2 ;
        RECT 48.280 78.980 48.680 79.380 ;
    END
  END Tile_X0Y0_N4BEG[4]
  PIN Tile_X0Y0_N4BEG[5]
    DIRECTION OUTPUT ;
    USE SIGNAL ;
    ANTENNADIFFAREA 2.724000 ;
    PORT
      LAYER Metal2 ;
        RECT 49.240 78.980 49.640 79.380 ;
    END
  END Tile_X0Y0_N4BEG[5]
  PIN Tile_X0Y0_N4BEG[6]
    DIRECTION OUTPUT ;
    USE SIGNAL ;
    ANTENNADIFFAREA 2.724000 ;
    PORT
      LAYER Metal2 ;
        RECT 50.200 78.980 50.600 79.380 ;
    END
  END Tile_X0Y0_N4BEG[6]
  PIN Tile_X0Y0_N4BEG[7]
    DIRECTION OUTPUT ;
    USE SIGNAL ;
    ANTENNADIFFAREA 2.724000 ;
    PORT
      LAYER Metal2 ;
        RECT 51.160 78.980 51.560 79.380 ;
    END
  END Tile_X0Y0_N4BEG[7]
  PIN Tile_X0Y0_N4BEG[8]
    DIRECTION OUTPUT ;
    USE SIGNAL ;
    ANTENNADIFFAREA 2.724000 ;
    PORT
      LAYER Metal2 ;
        RECT 52.120 78.980 52.520 79.380 ;
    END
  END Tile_X0Y0_N4BEG[8]
  PIN Tile_X0Y0_N4BEG[9]
    DIRECTION OUTPUT ;
    USE SIGNAL ;
    ANTENNADIFFAREA 2.724000 ;
    PORT
      LAYER Metal2 ;
        RECT 53.080 78.980 53.480 79.380 ;
    END
  END Tile_X0Y0_N4BEG[9]
  PIN Tile_X0Y0_NN4BEG[0]
    DIRECTION OUTPUT ;
    USE SIGNAL ;
    ANTENNADIFFAREA 2.724000 ;
    PORT
      LAYER Metal2 ;
        RECT 74.200 78.980 74.600 79.380 ;
    END
  END Tile_X0Y0_NN4BEG[0]
  PIN Tile_X0Y0_NN4BEG[10]
    DIRECTION OUTPUT ;
    USE SIGNAL ;
    ANTENNADIFFAREA 2.724000 ;
    PORT
      LAYER Metal2 ;
        RECT 83.800 78.980 84.200 79.380 ;
    END
  END Tile_X0Y0_NN4BEG[10]
  PIN Tile_X0Y0_NN4BEG[11]
    DIRECTION OUTPUT ;
    USE SIGNAL ;
    ANTENNADIFFAREA 2.724000 ;
    PORT
      LAYER Metal2 ;
        RECT 84.760 78.980 85.160 79.380 ;
    END
  END Tile_X0Y0_NN4BEG[11]
  PIN Tile_X0Y0_NN4BEG[12]
    DIRECTION OUTPUT ;
    USE SIGNAL ;
    ANTENNADIFFAREA 2.724000 ;
    PORT
      LAYER Metal2 ;
        RECT 85.720 78.980 86.120 79.380 ;
    END
  END Tile_X0Y0_NN4BEG[12]
  PIN Tile_X0Y0_NN4BEG[13]
    DIRECTION OUTPUT ;
    USE SIGNAL ;
    ANTENNADIFFAREA 2.724000 ;
    PORT
      LAYER Metal2 ;
        RECT 86.680 78.980 87.080 79.380 ;
    END
  END Tile_X0Y0_NN4BEG[13]
  PIN Tile_X0Y0_NN4BEG[14]
    DIRECTION OUTPUT ;
    USE SIGNAL ;
    ANTENNADIFFAREA 2.724000 ;
    PORT
      LAYER Metal2 ;
        RECT 87.640 78.980 88.040 79.380 ;
    END
  END Tile_X0Y0_NN4BEG[14]
  PIN Tile_X0Y0_NN4BEG[15]
    DIRECTION OUTPUT ;
    USE SIGNAL ;
    ANTENNADIFFAREA 2.724000 ;
    PORT
      LAYER Metal2 ;
        RECT 88.600 78.980 89.000 79.380 ;
    END
  END Tile_X0Y0_NN4BEG[15]
  PIN Tile_X0Y0_NN4BEG[1]
    DIRECTION OUTPUT ;
    USE SIGNAL ;
    ANTENNADIFFAREA 2.724000 ;
    PORT
      LAYER Metal2 ;
        RECT 75.160 78.980 75.560 79.380 ;
    END
  END Tile_X0Y0_NN4BEG[1]
  PIN Tile_X0Y0_NN4BEG[2]
    DIRECTION OUTPUT ;
    USE SIGNAL ;
    ANTENNADIFFAREA 2.724000 ;
    PORT
      LAYER Metal2 ;
        RECT 76.120 78.980 76.520 79.380 ;
    END
  END Tile_X0Y0_NN4BEG[2]
  PIN Tile_X0Y0_NN4BEG[3]
    DIRECTION OUTPUT ;
    USE SIGNAL ;
    ANTENNADIFFAREA 2.724000 ;
    PORT
      LAYER Metal2 ;
        RECT 77.080 78.980 77.480 79.380 ;
    END
  END Tile_X0Y0_NN4BEG[3]
  PIN Tile_X0Y0_NN4BEG[4]
    DIRECTION OUTPUT ;
    USE SIGNAL ;
    ANTENNADIFFAREA 2.724000 ;
    PORT
      LAYER Metal2 ;
        RECT 78.040 78.980 78.440 79.380 ;
    END
  END Tile_X0Y0_NN4BEG[4]
  PIN Tile_X0Y0_NN4BEG[5]
    DIRECTION OUTPUT ;
    USE SIGNAL ;
    ANTENNADIFFAREA 2.724000 ;
    PORT
      LAYER Metal2 ;
        RECT 79.000 78.980 79.400 79.380 ;
    END
  END Tile_X0Y0_NN4BEG[5]
  PIN Tile_X0Y0_NN4BEG[6]
    DIRECTION OUTPUT ;
    USE SIGNAL ;
    ANTENNADIFFAREA 2.724000 ;
    PORT
      LAYER Metal2 ;
        RECT 79.960 78.980 80.360 79.380 ;
    END
  END Tile_X0Y0_NN4BEG[6]
  PIN Tile_X0Y0_NN4BEG[7]
    DIRECTION OUTPUT ;
    USE SIGNAL ;
    ANTENNADIFFAREA 2.724000 ;
    PORT
      LAYER Metal2 ;
        RECT 80.920 78.980 81.320 79.380 ;
    END
  END Tile_X0Y0_NN4BEG[7]
  PIN Tile_X0Y0_NN4BEG[8]
    DIRECTION OUTPUT ;
    USE SIGNAL ;
    ANTENNADIFFAREA 2.724000 ;
    PORT
      LAYER Metal2 ;
        RECT 81.880 78.980 82.280 79.380 ;
    END
  END Tile_X0Y0_NN4BEG[8]
  PIN Tile_X0Y0_NN4BEG[9]
    DIRECTION OUTPUT ;
    USE SIGNAL ;
    ANTENNADIFFAREA 2.724000 ;
    PORT
      LAYER Metal2 ;
        RECT 82.840 78.980 83.240 79.380 ;
    END
  END Tile_X0Y0_NN4BEG[9]
  PIN Tile_X0Y0_S1END[0]
    DIRECTION INPUT ;
    USE SIGNAL ;
    ANTENNAGATEAREA 0.607100 ;
    PORT
      LAYER Metal2 ;
        RECT 97.240 78.980 97.640 79.380 ;
    END
  END Tile_X0Y0_S1END[0]
  PIN Tile_X0Y0_S1END[1]
    DIRECTION INPUT ;
    USE SIGNAL ;
    ANTENNAGATEAREA 0.607100 ;
    PORT
      LAYER Metal2 ;
        RECT 99.160 78.980 99.560 79.380 ;
    END
  END Tile_X0Y0_S1END[1]
  PIN Tile_X0Y0_S1END[2]
    DIRECTION INPUT ;
    USE SIGNAL ;
    ANTENNAGATEAREA 0.607100 ;
    PORT
      LAYER Metal2 ;
        RECT 101.080 78.980 101.480 79.380 ;
    END
  END Tile_X0Y0_S1END[2]
  PIN Tile_X0Y0_S1END[3]
    DIRECTION INPUT ;
    USE SIGNAL ;
    ANTENNAGATEAREA 0.607100 ;
    PORT
      LAYER Metal2 ;
        RECT 103.000 78.980 103.400 79.380 ;
    END
  END Tile_X0Y0_S1END[3]
  PIN Tile_X0Y0_S2END[0]
    DIRECTION INPUT ;
    USE SIGNAL ;
    ANTENNAGATEAREA 0.639600 ;
    PORT
      LAYER Metal2 ;
        RECT 123.160 78.980 123.560 79.380 ;
    END
  END Tile_X0Y0_S2END[0]
  PIN Tile_X0Y0_S2END[1]
    DIRECTION INPUT ;
    USE SIGNAL ;
    ANTENNAGATEAREA 0.639600 ;
    PORT
      LAYER Metal2 ;
        RECT 124.120 78.980 124.520 79.380 ;
    END
  END Tile_X0Y0_S2END[1]
  PIN Tile_X0Y0_S2END[2]
    DIRECTION INPUT ;
    USE SIGNAL ;
    ANTENNAGATEAREA 0.639600 ;
    PORT
      LAYER Metal2 ;
        RECT 125.080 78.980 125.480 79.380 ;
    END
  END Tile_X0Y0_S2END[2]
  PIN Tile_X0Y0_S2END[3]
    DIRECTION INPUT ;
    USE SIGNAL ;
    ANTENNAGATEAREA 0.639600 ;
    PORT
      LAYER Metal2 ;
        RECT 126.040 78.980 126.440 79.380 ;
    END
  END Tile_X0Y0_S2END[3]
  PIN Tile_X0Y0_S2END[4]
    DIRECTION INPUT ;
    USE SIGNAL ;
    ANTENNAGATEAREA 0.639600 ;
    PORT
      LAYER Metal2 ;
        RECT 127.000 78.980 127.400 79.380 ;
    END
  END Tile_X0Y0_S2END[4]
  PIN Tile_X0Y0_S2END[5]
    DIRECTION INPUT ;
    USE SIGNAL ;
    ANTENNAGATEAREA 0.639600 ;
    PORT
      LAYER Metal2 ;
        RECT 127.960 78.980 128.360 79.380 ;
    END
  END Tile_X0Y0_S2END[5]
  PIN Tile_X0Y0_S2END[6]
    DIRECTION INPUT ;
    USE SIGNAL ;
    ANTENNAGATEAREA 0.639600 ;
    PORT
      LAYER Metal2 ;
        RECT 128.920 78.980 129.320 79.380 ;
    END
  END Tile_X0Y0_S2END[6]
  PIN Tile_X0Y0_S2END[7]
    DIRECTION INPUT ;
    USE SIGNAL ;
    ANTENNAGATEAREA 0.639600 ;
    PORT
      LAYER Metal2 ;
        RECT 129.880 78.980 130.280 79.380 ;
    END
  END Tile_X0Y0_S2END[7]
  PIN Tile_X0Y0_S2MID[0]
    DIRECTION INPUT ;
    USE SIGNAL ;
    ANTENNAGATEAREA 0.820300 ;
    PORT
      LAYER Metal2 ;
        RECT 104.920 78.980 105.320 79.380 ;
    END
  END Tile_X0Y0_S2MID[0]
  PIN Tile_X0Y0_S2MID[1]
    DIRECTION INPUT ;
    USE SIGNAL ;
    ANTENNAGATEAREA 0.820300 ;
    PORT
      LAYER Metal2 ;
        RECT 106.840 78.980 107.240 79.380 ;
    END
  END Tile_X0Y0_S2MID[1]
  PIN Tile_X0Y0_S2MID[2]
    DIRECTION INPUT ;
    USE SIGNAL ;
    ANTENNAGATEAREA 0.820300 ;
    PORT
      LAYER Metal2 ;
        RECT 108.760 78.980 109.160 79.380 ;
    END
  END Tile_X0Y0_S2MID[2]
  PIN Tile_X0Y0_S2MID[3]
    DIRECTION INPUT ;
    USE SIGNAL ;
    ANTENNAGATEAREA 0.820300 ;
    PORT
      LAYER Metal2 ;
        RECT 110.680 78.980 111.080 79.380 ;
    END
  END Tile_X0Y0_S2MID[3]
  PIN Tile_X0Y0_S2MID[4]
    DIRECTION INPUT ;
    USE SIGNAL ;
    ANTENNAGATEAREA 0.820300 ;
    PORT
      LAYER Metal2 ;
        RECT 112.600 78.980 113.000 79.380 ;
    END
  END Tile_X0Y0_S2MID[4]
  PIN Tile_X0Y0_S2MID[5]
    DIRECTION INPUT ;
    USE SIGNAL ;
    ANTENNAGATEAREA 0.820300 ;
    PORT
      LAYER Metal2 ;
        RECT 114.520 78.980 114.920 79.380 ;
    END
  END Tile_X0Y0_S2MID[5]
  PIN Tile_X0Y0_S2MID[6]
    DIRECTION INPUT ;
    USE SIGNAL ;
    ANTENNAGATEAREA 0.820300 ;
    PORT
      LAYER Metal2 ;
        RECT 116.440 78.980 116.840 79.380 ;
    END
  END Tile_X0Y0_S2MID[6]
  PIN Tile_X0Y0_S2MID[7]
    DIRECTION INPUT ;
    USE SIGNAL ;
    ANTENNAGATEAREA 0.820300 ;
    PORT
      LAYER Metal2 ;
        RECT 118.360 78.980 118.760 79.380 ;
    END
  END Tile_X0Y0_S2MID[7]
  PIN Tile_X0Y0_S4END[0]
    DIRECTION INPUT ;
    USE SIGNAL ;
    ANTENNAGATEAREA 0.852800 ;
    PORT
      LAYER Metal2 ;
        RECT 141.400 78.980 141.800 79.380 ;
    END
  END Tile_X0Y0_S4END[0]
  PIN Tile_X0Y0_S4END[10]
    DIRECTION INPUT ;
    USE SIGNAL ;
    ANTENNAGATEAREA 0.852800 ;
    PORT
      LAYER Metal2 ;
        RECT 151.000 78.980 151.400 79.380 ;
    END
  END Tile_X0Y0_S4END[10]
  PIN Tile_X0Y0_S4END[11]
    DIRECTION INPUT ;
    USE SIGNAL ;
    ANTENNAGATEAREA 0.852800 ;
    PORT
      LAYER Metal2 ;
        RECT 151.960 78.980 152.360 79.380 ;
    END
  END Tile_X0Y0_S4END[11]
  PIN Tile_X0Y0_S4END[12]
    DIRECTION INPUT ;
    USE SIGNAL ;
    ANTENNAGATEAREA 0.852800 ;
    PORT
      LAYER Metal2 ;
        RECT 152.920 78.980 153.320 79.380 ;
    END
  END Tile_X0Y0_S4END[12]
  PIN Tile_X0Y0_S4END[13]
    DIRECTION INPUT ;
    USE SIGNAL ;
    ANTENNAGATEAREA 0.852800 ;
    PORT
      LAYER Metal2 ;
        RECT 153.880 78.980 154.280 79.380 ;
    END
  END Tile_X0Y0_S4END[13]
  PIN Tile_X0Y0_S4END[14]
    DIRECTION INPUT ;
    USE SIGNAL ;
    ANTENNAGATEAREA 0.852800 ;
    PORT
      LAYER Metal2 ;
        RECT 154.840 78.980 155.240 79.380 ;
    END
  END Tile_X0Y0_S4END[14]
  PIN Tile_X0Y0_S4END[15]
    DIRECTION INPUT ;
    USE SIGNAL ;
    ANTENNAGATEAREA 0.852800 ;
    PORT
      LAYER Metal2 ;
        RECT 155.800 78.980 156.200 79.380 ;
    END
  END Tile_X0Y0_S4END[15]
  PIN Tile_X0Y0_S4END[1]
    DIRECTION INPUT ;
    USE SIGNAL ;
    ANTENNAGATEAREA 0.852800 ;
    PORT
      LAYER Metal2 ;
        RECT 142.360 78.980 142.760 79.380 ;
    END
  END Tile_X0Y0_S4END[1]
  PIN Tile_X0Y0_S4END[2]
    DIRECTION INPUT ;
    USE SIGNAL ;
    ANTENNAGATEAREA 0.852800 ;
    PORT
      LAYER Metal2 ;
        RECT 143.320 78.980 143.720 79.380 ;
    END
  END Tile_X0Y0_S4END[2]
  PIN Tile_X0Y0_S4END[3]
    DIRECTION INPUT ;
    USE SIGNAL ;
    ANTENNAGATEAREA 0.852800 ;
    PORT
      LAYER Metal2 ;
        RECT 144.280 78.980 144.680 79.380 ;
    END
  END Tile_X0Y0_S4END[3]
  PIN Tile_X0Y0_S4END[4]
    DIRECTION INPUT ;
    USE SIGNAL ;
    ANTENNAGATEAREA 0.852800 ;
    PORT
      LAYER Metal2 ;
        RECT 145.240 78.980 145.640 79.380 ;
    END
  END Tile_X0Y0_S4END[4]
  PIN Tile_X0Y0_S4END[5]
    DIRECTION INPUT ;
    USE SIGNAL ;
    ANTENNAGATEAREA 0.852800 ;
    PORT
      LAYER Metal2 ;
        RECT 146.200 78.980 146.600 79.380 ;
    END
  END Tile_X0Y0_S4END[5]
  PIN Tile_X0Y0_S4END[6]
    DIRECTION INPUT ;
    USE SIGNAL ;
    ANTENNAGATEAREA 0.852800 ;
    PORT
      LAYER Metal2 ;
        RECT 147.160 78.980 147.560 79.380 ;
    END
  END Tile_X0Y0_S4END[6]
  PIN Tile_X0Y0_S4END[7]
    DIRECTION INPUT ;
    USE SIGNAL ;
    ANTENNAGATEAREA 0.852800 ;
    PORT
      LAYER Metal2 ;
        RECT 148.120 78.980 148.520 79.380 ;
    END
  END Tile_X0Y0_S4END[7]
  PIN Tile_X0Y0_S4END[8]
    DIRECTION INPUT ;
    USE SIGNAL ;
    ANTENNAGATEAREA 0.852800 ;
    PORT
      LAYER Metal2 ;
        RECT 149.080 78.980 149.480 79.380 ;
    END
  END Tile_X0Y0_S4END[8]
  PIN Tile_X0Y0_S4END[9]
    DIRECTION INPUT ;
    USE SIGNAL ;
    ANTENNAGATEAREA 0.852800 ;
    PORT
      LAYER Metal2 ;
        RECT 150.040 78.980 150.440 79.380 ;
    END
  END Tile_X0Y0_S4END[9]
  PIN Tile_X0Y0_SS4END[0]
    DIRECTION INPUT ;
    USE SIGNAL ;
    ANTENNAGATEAREA 0.852800 ;
    PORT
      LAYER Metal2 ;
        RECT 171.160 78.980 171.560 79.380 ;
    END
  END Tile_X0Y0_SS4END[0]
  PIN Tile_X0Y0_SS4END[10]
    DIRECTION INPUT ;
    USE SIGNAL ;
    ANTENNAGATEAREA 0.852800 ;
    PORT
      LAYER Metal2 ;
        RECT 180.760 78.980 181.160 79.380 ;
    END
  END Tile_X0Y0_SS4END[10]
  PIN Tile_X0Y0_SS4END[11]
    DIRECTION INPUT ;
    USE SIGNAL ;
    ANTENNAGATEAREA 0.852800 ;
    PORT
      LAYER Metal2 ;
        RECT 181.720 78.980 182.120 79.380 ;
    END
  END Tile_X0Y0_SS4END[11]
  PIN Tile_X0Y0_SS4END[12]
    DIRECTION INPUT ;
    USE SIGNAL ;
    ANTENNAGATEAREA 0.852800 ;
    ANTENNADIFFAREA 32.246399 ;
    PORT
      LAYER Metal2 ;
        RECT 182.680 78.980 183.080 79.380 ;
    END
  END Tile_X0Y0_SS4END[12]
  PIN Tile_X0Y0_SS4END[13]
    DIRECTION INPUT ;
    USE SIGNAL ;
    ANTENNAGATEAREA 0.852800 ;
    PORT
      LAYER Metal2 ;
        RECT 183.640 78.980 184.040 79.380 ;
    END
  END Tile_X0Y0_SS4END[13]
  PIN Tile_X0Y0_SS4END[14]
    DIRECTION INPUT ;
    USE SIGNAL ;
    ANTENNAGATEAREA 0.852800 ;
    ANTENNADIFFAREA 32.246399 ;
    PORT
      LAYER Metal2 ;
        RECT 184.600 78.980 185.000 79.380 ;
    END
  END Tile_X0Y0_SS4END[14]
  PIN Tile_X0Y0_SS4END[15]
    DIRECTION INPUT ;
    USE SIGNAL ;
    ANTENNAGATEAREA 0.852800 ;
    PORT
      LAYER Metal2 ;
        RECT 185.560 78.980 185.960 79.380 ;
    END
  END Tile_X0Y0_SS4END[15]
  PIN Tile_X0Y0_SS4END[1]
    DIRECTION INPUT ;
    USE SIGNAL ;
    ANTENNAGATEAREA 0.852800 ;
    PORT
      LAYER Metal2 ;
        RECT 172.120 78.980 172.520 79.380 ;
    END
  END Tile_X0Y0_SS4END[1]
  PIN Tile_X0Y0_SS4END[2]
    DIRECTION INPUT ;
    USE SIGNAL ;
    ANTENNAGATEAREA 0.852800 ;
    PORT
      LAYER Metal2 ;
        RECT 173.080 78.980 173.480 79.380 ;
    END
  END Tile_X0Y0_SS4END[2]
  PIN Tile_X0Y0_SS4END[3]
    DIRECTION INPUT ;
    USE SIGNAL ;
    ANTENNAGATEAREA 0.852800 ;
    PORT
      LAYER Metal2 ;
        RECT 174.040 78.980 174.440 79.380 ;
    END
  END Tile_X0Y0_SS4END[3]
  PIN Tile_X0Y0_SS4END[4]
    DIRECTION INPUT ;
    USE SIGNAL ;
    ANTENNAGATEAREA 0.852800 ;
    PORT
      LAYER Metal2 ;
        RECT 175.000 78.980 175.400 79.380 ;
    END
  END Tile_X0Y0_SS4END[4]
  PIN Tile_X0Y0_SS4END[5]
    DIRECTION INPUT ;
    USE SIGNAL ;
    ANTENNAGATEAREA 0.852800 ;
    PORT
      LAYER Metal2 ;
        RECT 175.960 78.980 176.360 79.380 ;
    END
  END Tile_X0Y0_SS4END[5]
  PIN Tile_X0Y0_SS4END[6]
    DIRECTION INPUT ;
    USE SIGNAL ;
    ANTENNAGATEAREA 0.852800 ;
    PORT
      LAYER Metal2 ;
        RECT 176.920 78.980 177.320 79.380 ;
    END
  END Tile_X0Y0_SS4END[6]
  PIN Tile_X0Y0_SS4END[7]
    DIRECTION INPUT ;
    USE SIGNAL ;
    ANTENNAGATEAREA 0.852800 ;
    PORT
      LAYER Metal2 ;
        RECT 177.880 78.980 178.280 79.380 ;
    END
  END Tile_X0Y0_SS4END[7]
  PIN Tile_X0Y0_SS4END[8]
    DIRECTION INPUT ;
    USE SIGNAL ;
    ANTENNAGATEAREA 0.852800 ;
    PORT
      LAYER Metal2 ;
        RECT 178.840 78.980 179.240 79.380 ;
    END
  END Tile_X0Y0_SS4END[8]
  PIN Tile_X0Y0_SS4END[9]
    DIRECTION INPUT ;
    USE SIGNAL ;
    ANTENNAGATEAREA 0.852800 ;
    PORT
      LAYER Metal2 ;
        RECT 179.800 78.980 180.200 79.380 ;
    END
  END Tile_X0Y0_SS4END[9]
  PIN Tile_X0Y0_UserCLK
    DIRECTION INPUT ;
    USE SIGNAL ;
    ANTENNAGATEAREA 20.250099 ;
    PORT
      LAYER Metal3 ;
        RECT 0.000 1.900 0.400 2.300 ;
    END
  END Tile_X0Y0_UserCLK
  PIN Tile_X1Y0_Co
    DIRECTION OUTPUT ;
    USE SIGNAL ;
    ANTENNADIFFAREA 2.314600 ;
    PORT
      LAYER Metal2 ;
        RECT 427.480 78.980 427.880 79.380 ;
    END
  END Tile_X1Y0_Co
  PIN Tile_X1Y0_FrameStrobe[0]
    DIRECTION INPUT ;
    USE SIGNAL ;
    ANTENNAGATEAREA 11.745500 ;
    PORT
      LAYER Metal2 ;
        RECT 240.280 0.000 240.680 0.400 ;
    END
  END Tile_X1Y0_FrameStrobe[0]
  PIN Tile_X1Y0_FrameStrobe[10]
    DIRECTION INPUT ;
    USE SIGNAL ;
    ANTENNAGATEAREA 0.180700 ;
    PORT
      LAYER Metal2 ;
        RECT 355.480 0.000 355.880 0.400 ;
    END
  END Tile_X1Y0_FrameStrobe[10]
  PIN Tile_X1Y0_FrameStrobe[11]
    DIRECTION INPUT ;
    USE SIGNAL ;
    ANTENNAGATEAREA 0.180700 ;
    PORT
      LAYER Metal2 ;
        RECT 367.000 0.000 367.400 0.400 ;
    END
  END Tile_X1Y0_FrameStrobe[11]
  PIN Tile_X1Y0_FrameStrobe[12]
    DIRECTION INPUT ;
    USE SIGNAL ;
    ANTENNAGATEAREA 0.180700 ;
    PORT
      LAYER Metal2 ;
        RECT 378.520 0.000 378.920 0.400 ;
    END
  END Tile_X1Y0_FrameStrobe[12]
  PIN Tile_X1Y0_FrameStrobe[13]
    DIRECTION INPUT ;
    USE SIGNAL ;
    ANTENNAGATEAREA 0.180700 ;
    PORT
      LAYER Metal2 ;
        RECT 390.040 0.000 390.440 0.400 ;
    END
  END Tile_X1Y0_FrameStrobe[13]
  PIN Tile_X1Y0_FrameStrobe[14]
    DIRECTION INPUT ;
    USE SIGNAL ;
    ANTENNAGATEAREA 0.180700 ;
    PORT
      LAYER Metal2 ;
        RECT 401.560 0.000 401.960 0.400 ;
    END
  END Tile_X1Y0_FrameStrobe[14]
  PIN Tile_X1Y0_FrameStrobe[15]
    DIRECTION INPUT ;
    USE SIGNAL ;
    ANTENNAGATEAREA 0.180700 ;
    PORT
      LAYER Metal2 ;
        RECT 413.080 0.000 413.480 0.400 ;
    END
  END Tile_X1Y0_FrameStrobe[15]
  PIN Tile_X1Y0_FrameStrobe[16]
    DIRECTION INPUT ;
    USE SIGNAL ;
    ANTENNAGATEAREA 0.180700 ;
    PORT
      LAYER Metal2 ;
        RECT 424.600 0.000 425.000 0.400 ;
    END
  END Tile_X1Y0_FrameStrobe[16]
  PIN Tile_X1Y0_FrameStrobe[17]
    DIRECTION INPUT ;
    USE SIGNAL ;
    ANTENNAGATEAREA 0.180700 ;
    PORT
      LAYER Metal2 ;
        RECT 436.120 0.000 436.520 0.400 ;
    END
  END Tile_X1Y0_FrameStrobe[17]
  PIN Tile_X1Y0_FrameStrobe[18]
    DIRECTION INPUT ;
    USE SIGNAL ;
    ANTENNAGATEAREA 0.180700 ;
    PORT
      LAYER Metal2 ;
        RECT 447.640 0.000 448.040 0.400 ;
    END
  END Tile_X1Y0_FrameStrobe[18]
  PIN Tile_X1Y0_FrameStrobe[19]
    DIRECTION INPUT ;
    USE SIGNAL ;
    ANTENNAGATEAREA 0.180700 ;
    PORT
      LAYER Metal2 ;
        RECT 459.160 0.000 459.560 0.400 ;
    END
  END Tile_X1Y0_FrameStrobe[19]
  PIN Tile_X1Y0_FrameStrobe[1]
    DIRECTION INPUT ;
    USE SIGNAL ;
    ANTENNAGATEAREA 11.745500 ;
    PORT
      LAYER Metal2 ;
        RECT 251.800 0.000 252.200 0.400 ;
    END
  END Tile_X1Y0_FrameStrobe[1]
  PIN Tile_X1Y0_FrameStrobe[2]
    DIRECTION INPUT ;
    USE SIGNAL ;
    ANTENNAGATEAREA 11.745500 ;
    PORT
      LAYER Metal2 ;
        RECT 263.320 0.000 263.720 0.400 ;
    END
  END Tile_X1Y0_FrameStrobe[2]
  PIN Tile_X1Y0_FrameStrobe[3]
    DIRECTION INPUT ;
    USE SIGNAL ;
    ANTENNAGATEAREA 5.963100 ;
    PORT
      LAYER Metal2 ;
        RECT 274.840 0.000 275.240 0.400 ;
    END
  END Tile_X1Y0_FrameStrobe[3]
  PIN Tile_X1Y0_FrameStrobe[4]
    DIRECTION INPUT ;
    USE SIGNAL ;
    ANTENNAGATEAREA 0.180700 ;
    PORT
      LAYER Metal2 ;
        RECT 286.360 0.000 286.760 0.400 ;
    END
  END Tile_X1Y0_FrameStrobe[4]
  PIN Tile_X1Y0_FrameStrobe[5]
    DIRECTION INPUT ;
    USE SIGNAL ;
    ANTENNAGATEAREA 0.180700 ;
    PORT
      LAYER Metal2 ;
        RECT 297.880 0.000 298.280 0.400 ;
    END
  END Tile_X1Y0_FrameStrobe[5]
  PIN Tile_X1Y0_FrameStrobe[6]
    DIRECTION INPUT ;
    USE SIGNAL ;
    ANTENNAGATEAREA 0.180700 ;
    PORT
      LAYER Metal2 ;
        RECT 309.400 0.000 309.800 0.400 ;
    END
  END Tile_X1Y0_FrameStrobe[6]
  PIN Tile_X1Y0_FrameStrobe[7]
    DIRECTION INPUT ;
    USE SIGNAL ;
    ANTENNAGATEAREA 0.180700 ;
    PORT
      LAYER Metal2 ;
        RECT 320.920 0.000 321.320 0.400 ;
    END
  END Tile_X1Y0_FrameStrobe[7]
  PIN Tile_X1Y0_FrameStrobe[8]
    DIRECTION INPUT ;
    USE SIGNAL ;
    ANTENNAGATEAREA 0.180700 ;
    PORT
      LAYER Metal2 ;
        RECT 332.440 0.000 332.840 0.400 ;
    END
  END Tile_X1Y0_FrameStrobe[8]
  PIN Tile_X1Y0_FrameStrobe[9]
    DIRECTION INPUT ;
    USE SIGNAL ;
    ANTENNAGATEAREA 0.180700 ;
    PORT
      LAYER Metal2 ;
        RECT 343.960 0.000 344.360 0.400 ;
    END
  END Tile_X1Y0_FrameStrobe[9]
  PIN Tile_X1Y0_FrameStrobe_O[0]
    DIRECTION OUTPUT ;
    USE SIGNAL ;
    ANTENNADIFFAREA 2.724000 ;
    PORT
      LAYER Metal2 ;
        RECT 438.040 78.980 438.440 79.380 ;
    END
  END Tile_X1Y0_FrameStrobe_O[0]
  PIN Tile_X1Y0_FrameStrobe_O[10]
    DIRECTION OUTPUT ;
    USE SIGNAL ;
    ANTENNADIFFAREA 2.724000 ;
    PORT
      LAYER Metal2 ;
        RECT 447.640 78.980 448.040 79.380 ;
    END
  END Tile_X1Y0_FrameStrobe_O[10]
  PIN Tile_X1Y0_FrameStrobe_O[11]
    DIRECTION OUTPUT ;
    USE SIGNAL ;
    ANTENNADIFFAREA 2.724000 ;
    PORT
      LAYER Metal2 ;
        RECT 448.600 78.980 449.000 79.380 ;
    END
  END Tile_X1Y0_FrameStrobe_O[11]
  PIN Tile_X1Y0_FrameStrobe_O[12]
    DIRECTION OUTPUT ;
    USE SIGNAL ;
    ANTENNADIFFAREA 2.724000 ;
    PORT
      LAYER Metal2 ;
        RECT 449.560 78.980 449.960 79.380 ;
    END
  END Tile_X1Y0_FrameStrobe_O[12]
  PIN Tile_X1Y0_FrameStrobe_O[13]
    DIRECTION OUTPUT ;
    USE SIGNAL ;
    ANTENNADIFFAREA 2.724000 ;
    PORT
      LAYER Metal2 ;
        RECT 450.520 78.980 450.920 79.380 ;
    END
  END Tile_X1Y0_FrameStrobe_O[13]
  PIN Tile_X1Y0_FrameStrobe_O[14]
    DIRECTION OUTPUT ;
    USE SIGNAL ;
    ANTENNADIFFAREA 2.724000 ;
    PORT
      LAYER Metal2 ;
        RECT 451.480 78.980 451.880 79.380 ;
    END
  END Tile_X1Y0_FrameStrobe_O[14]
  PIN Tile_X1Y0_FrameStrobe_O[15]
    DIRECTION OUTPUT ;
    USE SIGNAL ;
    ANTENNADIFFAREA 2.724000 ;
    PORT
      LAYER Metal2 ;
        RECT 452.440 78.980 452.840 79.380 ;
    END
  END Tile_X1Y0_FrameStrobe_O[15]
  PIN Tile_X1Y0_FrameStrobe_O[16]
    DIRECTION OUTPUT ;
    USE SIGNAL ;
    ANTENNADIFFAREA 2.724000 ;
    PORT
      LAYER Metal2 ;
        RECT 453.400 78.980 453.800 79.380 ;
    END
  END Tile_X1Y0_FrameStrobe_O[16]
  PIN Tile_X1Y0_FrameStrobe_O[17]
    DIRECTION OUTPUT ;
    USE SIGNAL ;
    ANTENNADIFFAREA 2.724000 ;
    PORT
      LAYER Metal2 ;
        RECT 454.360 78.980 454.760 79.380 ;
    END
  END Tile_X1Y0_FrameStrobe_O[17]
  PIN Tile_X1Y0_FrameStrobe_O[18]
    DIRECTION OUTPUT ;
    USE SIGNAL ;
    ANTENNADIFFAREA 2.724000 ;
    PORT
      LAYER Metal2 ;
        RECT 455.320 78.980 455.720 79.380 ;
    END
  END Tile_X1Y0_FrameStrobe_O[18]
  PIN Tile_X1Y0_FrameStrobe_O[19]
    DIRECTION OUTPUT ;
    USE SIGNAL ;
    ANTENNADIFFAREA 2.724000 ;
    PORT
      LAYER Metal2 ;
        RECT 456.280 78.980 456.680 79.380 ;
    END
  END Tile_X1Y0_FrameStrobe_O[19]
  PIN Tile_X1Y0_FrameStrobe_O[1]
    DIRECTION OUTPUT ;
    USE SIGNAL ;
    ANTENNADIFFAREA 2.724000 ;
    PORT
      LAYER Metal2 ;
        RECT 439.000 78.980 439.400 79.380 ;
    END
  END Tile_X1Y0_FrameStrobe_O[1]
  PIN Tile_X1Y0_FrameStrobe_O[2]
    DIRECTION OUTPUT ;
    USE SIGNAL ;
    ANTENNADIFFAREA 2.724000 ;
    PORT
      LAYER Metal2 ;
        RECT 439.960 78.980 440.360 79.380 ;
    END
  END Tile_X1Y0_FrameStrobe_O[2]
  PIN Tile_X1Y0_FrameStrobe_O[3]
    DIRECTION OUTPUT ;
    USE SIGNAL ;
    ANTENNADIFFAREA 2.724000 ;
    PORT
      LAYER Metal2 ;
        RECT 440.920 78.980 441.320 79.380 ;
    END
  END Tile_X1Y0_FrameStrobe_O[3]
  PIN Tile_X1Y0_FrameStrobe_O[4]
    DIRECTION OUTPUT ;
    USE SIGNAL ;
    ANTENNADIFFAREA 2.724000 ;
    PORT
      LAYER Metal2 ;
        RECT 441.880 78.980 442.280 79.380 ;
    END
  END Tile_X1Y0_FrameStrobe_O[4]
  PIN Tile_X1Y0_FrameStrobe_O[5]
    DIRECTION OUTPUT ;
    USE SIGNAL ;
    ANTENNADIFFAREA 2.724000 ;
    PORT
      LAYER Metal2 ;
        RECT 442.840 78.980 443.240 79.380 ;
    END
  END Tile_X1Y0_FrameStrobe_O[5]
  PIN Tile_X1Y0_FrameStrobe_O[6]
    DIRECTION OUTPUT ;
    USE SIGNAL ;
    ANTENNADIFFAREA 2.724000 ;
    PORT
      LAYER Metal2 ;
        RECT 443.800 78.980 444.200 79.380 ;
    END
  END Tile_X1Y0_FrameStrobe_O[6]
  PIN Tile_X1Y0_FrameStrobe_O[7]
    DIRECTION OUTPUT ;
    USE SIGNAL ;
    ANTENNADIFFAREA 2.724000 ;
    PORT
      LAYER Metal2 ;
        RECT 444.760 78.980 445.160 79.380 ;
    END
  END Tile_X1Y0_FrameStrobe_O[7]
  PIN Tile_X1Y0_FrameStrobe_O[8]
    DIRECTION OUTPUT ;
    USE SIGNAL ;
    ANTENNADIFFAREA 2.724000 ;
    PORT
      LAYER Metal2 ;
        RECT 445.720 78.980 446.120 79.380 ;
    END
  END Tile_X1Y0_FrameStrobe_O[8]
  PIN Tile_X1Y0_FrameStrobe_O[9]
    DIRECTION OUTPUT ;
    USE SIGNAL ;
    ANTENNADIFFAREA 2.724000 ;
    PORT
      LAYER Metal2 ;
        RECT 446.680 78.980 447.080 79.380 ;
    END
  END Tile_X1Y0_FrameStrobe_O[9]
  PIN Tile_X1Y0_N1BEG[0]
    DIRECTION OUTPUT ;
    USE SIGNAL ;
    ANTENNADIFFAREA 2.724000 ;
    PORT
      LAYER Metal2 ;
        RECT 234.520 78.980 234.920 79.380 ;
    END
  END Tile_X1Y0_N1BEG[0]
  PIN Tile_X1Y0_N1BEG[1]
    DIRECTION OUTPUT ;
    USE SIGNAL ;
    ANTENNADIFFAREA 2.724000 ;
    PORT
      LAYER Metal2 ;
        RECT 236.440 78.980 236.840 79.380 ;
    END
  END Tile_X1Y0_N1BEG[1]
  PIN Tile_X1Y0_N1BEG[2]
    DIRECTION OUTPUT ;
    USE SIGNAL ;
    ANTENNADIFFAREA 2.724000 ;
    PORT
      LAYER Metal2 ;
        RECT 238.360 78.980 238.760 79.380 ;
    END
  END Tile_X1Y0_N1BEG[2]
  PIN Tile_X1Y0_N1BEG[3]
    DIRECTION OUTPUT ;
    USE SIGNAL ;
    ANTENNADIFFAREA 2.724000 ;
    PORT
      LAYER Metal2 ;
        RECT 240.280 78.980 240.680 79.380 ;
    END
  END Tile_X1Y0_N1BEG[3]
  PIN Tile_X1Y0_N2BEG[0]
    DIRECTION OUTPUT ;
    USE SIGNAL ;
    ANTENNADIFFAREA 2.724000 ;
    PORT
      LAYER Metal2 ;
        RECT 245.080 78.980 245.480 79.380 ;
    END
  END Tile_X1Y0_N2BEG[0]
  PIN Tile_X1Y0_N2BEG[1]
    DIRECTION OUTPUT ;
    USE SIGNAL ;
    ANTENNADIFFAREA 2.724000 ;
    PORT
      LAYER Metal2 ;
        RECT 246.040 78.980 246.440 79.380 ;
    END
  END Tile_X1Y0_N2BEG[1]
  PIN Tile_X1Y0_N2BEG[2]
    DIRECTION OUTPUT ;
    USE SIGNAL ;
    ANTENNADIFFAREA 2.724000 ;
    PORT
      LAYER Metal2 ;
        RECT 247.000 78.980 247.400 79.380 ;
    END
  END Tile_X1Y0_N2BEG[2]
  PIN Tile_X1Y0_N2BEG[3]
    DIRECTION OUTPUT ;
    USE SIGNAL ;
    ANTENNADIFFAREA 2.724000 ;
    PORT
      LAYER Metal2 ;
        RECT 247.960 78.980 248.360 79.380 ;
    END
  END Tile_X1Y0_N2BEG[3]
  PIN Tile_X1Y0_N2BEG[4]
    DIRECTION OUTPUT ;
    USE SIGNAL ;
    ANTENNADIFFAREA 2.724000 ;
    PORT
      LAYER Metal2 ;
        RECT 248.920 78.980 249.320 79.380 ;
    END
  END Tile_X1Y0_N2BEG[4]
  PIN Tile_X1Y0_N2BEG[5]
    DIRECTION OUTPUT ;
    USE SIGNAL ;
    ANTENNADIFFAREA 2.724000 ;
    PORT
      LAYER Metal2 ;
        RECT 249.880 78.980 250.280 79.380 ;
    END
  END Tile_X1Y0_N2BEG[5]
  PIN Tile_X1Y0_N2BEG[6]
    DIRECTION OUTPUT ;
    USE SIGNAL ;
    ANTENNADIFFAREA 2.724000 ;
    PORT
      LAYER Metal2 ;
        RECT 250.840 78.980 251.240 79.380 ;
    END
  END Tile_X1Y0_N2BEG[6]
  PIN Tile_X1Y0_N2BEG[7]
    DIRECTION OUTPUT ;
    USE SIGNAL ;
    ANTENNADIFFAREA 2.724000 ;
    PORT
      LAYER Metal2 ;
        RECT 251.800 78.980 252.200 79.380 ;
    END
  END Tile_X1Y0_N2BEG[7]
  PIN Tile_X1Y0_N2BEGb[0]
    DIRECTION OUTPUT ;
    USE SIGNAL ;
    ANTENNADIFFAREA 2.724000 ;
    PORT
      LAYER Metal2 ;
        RECT 259.480 78.980 259.880 79.380 ;
    END
  END Tile_X1Y0_N2BEGb[0]
  PIN Tile_X1Y0_N2BEGb[1]
    DIRECTION OUTPUT ;
    USE SIGNAL ;
    ANTENNADIFFAREA 2.724000 ;
    PORT
      LAYER Metal2 ;
        RECT 260.440 78.980 260.840 79.380 ;
    END
  END Tile_X1Y0_N2BEGb[1]
  PIN Tile_X1Y0_N2BEGb[2]
    DIRECTION OUTPUT ;
    USE SIGNAL ;
    ANTENNADIFFAREA 2.724000 ;
    PORT
      LAYER Metal2 ;
        RECT 261.400 78.980 261.800 79.380 ;
    END
  END Tile_X1Y0_N2BEGb[2]
  PIN Tile_X1Y0_N2BEGb[3]
    DIRECTION OUTPUT ;
    USE SIGNAL ;
    ANTENNADIFFAREA 2.724000 ;
    PORT
      LAYER Metal2 ;
        RECT 262.360 78.980 262.760 79.380 ;
    END
  END Tile_X1Y0_N2BEGb[3]
  PIN Tile_X1Y0_N2BEGb[4]
    DIRECTION OUTPUT ;
    USE SIGNAL ;
    ANTENNADIFFAREA 2.724000 ;
    PORT
      LAYER Metal2 ;
        RECT 263.320 78.980 263.720 79.380 ;
    END
  END Tile_X1Y0_N2BEGb[4]
  PIN Tile_X1Y0_N2BEGb[5]
    DIRECTION OUTPUT ;
    USE SIGNAL ;
    ANTENNADIFFAREA 2.724000 ;
    PORT
      LAYER Metal2 ;
        RECT 264.280 78.980 264.680 79.380 ;
    END
  END Tile_X1Y0_N2BEGb[5]
  PIN Tile_X1Y0_N2BEGb[6]
    DIRECTION OUTPUT ;
    USE SIGNAL ;
    ANTENNADIFFAREA 2.724000 ;
    PORT
      LAYER Metal2 ;
        RECT 265.240 78.980 265.640 79.380 ;
    END
  END Tile_X1Y0_N2BEGb[6]
  PIN Tile_X1Y0_N2BEGb[7]
    DIRECTION OUTPUT ;
    USE SIGNAL ;
    ANTENNADIFFAREA 2.724000 ;
    PORT
      LAYER Metal2 ;
        RECT 266.200 78.980 266.600 79.380 ;
    END
  END Tile_X1Y0_N2BEGb[7]
  PIN Tile_X1Y0_N4BEG[0]
    DIRECTION OUTPUT ;
    USE SIGNAL ;
    ANTENNADIFFAREA 2.724000 ;
    PORT
      LAYER Metal2 ;
        RECT 277.720 78.980 278.120 79.380 ;
    END
  END Tile_X1Y0_N4BEG[0]
  PIN Tile_X1Y0_N4BEG[10]
    DIRECTION OUTPUT ;
    USE SIGNAL ;
    ANTENNADIFFAREA 2.724000 ;
    PORT
      LAYER Metal2 ;
        RECT 287.320 78.980 287.720 79.380 ;
    END
  END Tile_X1Y0_N4BEG[10]
  PIN Tile_X1Y0_N4BEG[11]
    DIRECTION OUTPUT ;
    USE SIGNAL ;
    ANTENNADIFFAREA 2.724000 ;
    PORT
      LAYER Metal2 ;
        RECT 288.280 78.980 288.680 79.380 ;
    END
  END Tile_X1Y0_N4BEG[11]
  PIN Tile_X1Y0_N4BEG[12]
    DIRECTION OUTPUT ;
    USE SIGNAL ;
    ANTENNADIFFAREA 2.724000 ;
    PORT
      LAYER Metal2 ;
        RECT 289.240 78.980 289.640 79.380 ;
    END
  END Tile_X1Y0_N4BEG[12]
  PIN Tile_X1Y0_N4BEG[13]
    DIRECTION OUTPUT ;
    USE SIGNAL ;
    ANTENNADIFFAREA 2.724000 ;
    PORT
      LAYER Metal2 ;
        RECT 290.200 78.980 290.600 79.380 ;
    END
  END Tile_X1Y0_N4BEG[13]
  PIN Tile_X1Y0_N4BEG[14]
    DIRECTION OUTPUT ;
    USE SIGNAL ;
    ANTENNADIFFAREA 2.724000 ;
    PORT
      LAYER Metal2 ;
        RECT 291.160 78.980 291.560 79.380 ;
    END
  END Tile_X1Y0_N4BEG[14]
  PIN Tile_X1Y0_N4BEG[15]
    DIRECTION OUTPUT ;
    USE SIGNAL ;
    ANTENNADIFFAREA 2.724000 ;
    PORT
      LAYER Metal2 ;
        RECT 292.120 78.980 292.520 79.380 ;
    END
  END Tile_X1Y0_N4BEG[15]
  PIN Tile_X1Y0_N4BEG[1]
    DIRECTION OUTPUT ;
    USE SIGNAL ;
    ANTENNADIFFAREA 2.724000 ;
    PORT
      LAYER Metal2 ;
        RECT 278.680 78.980 279.080 79.380 ;
    END
  END Tile_X1Y0_N4BEG[1]
  PIN Tile_X1Y0_N4BEG[2]
    DIRECTION OUTPUT ;
    USE SIGNAL ;
    ANTENNADIFFAREA 2.724000 ;
    PORT
      LAYER Metal2 ;
        RECT 279.640 78.980 280.040 79.380 ;
    END
  END Tile_X1Y0_N4BEG[2]
  PIN Tile_X1Y0_N4BEG[3]
    DIRECTION OUTPUT ;
    USE SIGNAL ;
    ANTENNADIFFAREA 2.724000 ;
    PORT
      LAYER Metal2 ;
        RECT 280.600 78.980 281.000 79.380 ;
    END
  END Tile_X1Y0_N4BEG[3]
  PIN Tile_X1Y0_N4BEG[4]
    DIRECTION OUTPUT ;
    USE SIGNAL ;
    ANTENNADIFFAREA 2.724000 ;
    PORT
      LAYER Metal2 ;
        RECT 281.560 78.980 281.960 79.380 ;
    END
  END Tile_X1Y0_N4BEG[4]
  PIN Tile_X1Y0_N4BEG[5]
    DIRECTION OUTPUT ;
    USE SIGNAL ;
    ANTENNADIFFAREA 2.724000 ;
    PORT
      LAYER Metal2 ;
        RECT 282.520 78.980 282.920 79.380 ;
    END
  END Tile_X1Y0_N4BEG[5]
  PIN Tile_X1Y0_N4BEG[6]
    DIRECTION OUTPUT ;
    USE SIGNAL ;
    ANTENNADIFFAREA 2.724000 ;
    PORT
      LAYER Metal2 ;
        RECT 283.480 78.980 283.880 79.380 ;
    END
  END Tile_X1Y0_N4BEG[6]
  PIN Tile_X1Y0_N4BEG[7]
    DIRECTION OUTPUT ;
    USE SIGNAL ;
    ANTENNADIFFAREA 2.724000 ;
    PORT
      LAYER Metal2 ;
        RECT 284.440 78.980 284.840 79.380 ;
    END
  END Tile_X1Y0_N4BEG[7]
  PIN Tile_X1Y0_N4BEG[8]
    DIRECTION OUTPUT ;
    USE SIGNAL ;
    ANTENNADIFFAREA 2.724000 ;
    PORT
      LAYER Metal2 ;
        RECT 285.400 78.980 285.800 79.380 ;
    END
  END Tile_X1Y0_N4BEG[8]
  PIN Tile_X1Y0_N4BEG[9]
    DIRECTION OUTPUT ;
    USE SIGNAL ;
    ANTENNADIFFAREA 2.724000 ;
    PORT
      LAYER Metal2 ;
        RECT 286.360 78.980 286.760 79.380 ;
    END
  END Tile_X1Y0_N4BEG[9]
  PIN Tile_X1Y0_NN4BEG[0]
    DIRECTION OUTPUT ;
    USE SIGNAL ;
    ANTENNADIFFAREA 2.724000 ;
    PORT
      LAYER Metal2 ;
        RECT 307.480 78.980 307.880 79.380 ;
    END
  END Tile_X1Y0_NN4BEG[0]
  PIN Tile_X1Y0_NN4BEG[10]
    DIRECTION OUTPUT ;
    USE SIGNAL ;
    ANTENNADIFFAREA 2.724000 ;
    PORT
      LAYER Metal2 ;
        RECT 317.080 78.980 317.480 79.380 ;
    END
  END Tile_X1Y0_NN4BEG[10]
  PIN Tile_X1Y0_NN4BEG[11]
    DIRECTION OUTPUT ;
    USE SIGNAL ;
    ANTENNADIFFAREA 2.724000 ;
    PORT
      LAYER Metal2 ;
        RECT 318.040 78.980 318.440 79.380 ;
    END
  END Tile_X1Y0_NN4BEG[11]
  PIN Tile_X1Y0_NN4BEG[12]
    DIRECTION OUTPUT ;
    USE SIGNAL ;
    ANTENNADIFFAREA 2.724000 ;
    PORT
      LAYER Metal2 ;
        RECT 319.000 78.980 319.400 79.380 ;
    END
  END Tile_X1Y0_NN4BEG[12]
  PIN Tile_X1Y0_NN4BEG[13]
    DIRECTION OUTPUT ;
    USE SIGNAL ;
    ANTENNADIFFAREA 2.724000 ;
    PORT
      LAYER Metal2 ;
        RECT 319.960 78.980 320.360 79.380 ;
    END
  END Tile_X1Y0_NN4BEG[13]
  PIN Tile_X1Y0_NN4BEG[14]
    DIRECTION OUTPUT ;
    USE SIGNAL ;
    ANTENNADIFFAREA 2.724000 ;
    PORT
      LAYER Metal2 ;
        RECT 320.920 78.980 321.320 79.380 ;
    END
  END Tile_X1Y0_NN4BEG[14]
  PIN Tile_X1Y0_NN4BEG[15]
    DIRECTION OUTPUT ;
    USE SIGNAL ;
    ANTENNADIFFAREA 2.724000 ;
    PORT
      LAYER Metal2 ;
        RECT 321.880 78.980 322.280 79.380 ;
    END
  END Tile_X1Y0_NN4BEG[15]
  PIN Tile_X1Y0_NN4BEG[1]
    DIRECTION OUTPUT ;
    USE SIGNAL ;
    ANTENNADIFFAREA 2.724000 ;
    PORT
      LAYER Metal2 ;
        RECT 308.440 78.980 308.840 79.380 ;
    END
  END Tile_X1Y0_NN4BEG[1]
  PIN Tile_X1Y0_NN4BEG[2]
    DIRECTION OUTPUT ;
    USE SIGNAL ;
    ANTENNADIFFAREA 2.724000 ;
    PORT
      LAYER Metal2 ;
        RECT 309.400 78.980 309.800 79.380 ;
    END
  END Tile_X1Y0_NN4BEG[2]
  PIN Tile_X1Y0_NN4BEG[3]
    DIRECTION OUTPUT ;
    USE SIGNAL ;
    ANTENNADIFFAREA 2.724000 ;
    PORT
      LAYER Metal2 ;
        RECT 310.360 78.980 310.760 79.380 ;
    END
  END Tile_X1Y0_NN4BEG[3]
  PIN Tile_X1Y0_NN4BEG[4]
    DIRECTION OUTPUT ;
    USE SIGNAL ;
    ANTENNADIFFAREA 2.724000 ;
    PORT
      LAYER Metal2 ;
        RECT 311.320 78.980 311.720 79.380 ;
    END
  END Tile_X1Y0_NN4BEG[4]
  PIN Tile_X1Y0_NN4BEG[5]
    DIRECTION OUTPUT ;
    USE SIGNAL ;
    ANTENNADIFFAREA 2.724000 ;
    PORT
      LAYER Metal2 ;
        RECT 312.280 78.980 312.680 79.380 ;
    END
  END Tile_X1Y0_NN4BEG[5]
  PIN Tile_X1Y0_NN4BEG[6]
    DIRECTION OUTPUT ;
    USE SIGNAL ;
    ANTENNADIFFAREA 2.724000 ;
    PORT
      LAYER Metal2 ;
        RECT 313.240 78.980 313.640 79.380 ;
    END
  END Tile_X1Y0_NN4BEG[6]
  PIN Tile_X1Y0_NN4BEG[7]
    DIRECTION OUTPUT ;
    USE SIGNAL ;
    ANTENNADIFFAREA 2.724000 ;
    PORT
      LAYER Metal2 ;
        RECT 314.200 78.980 314.600 79.380 ;
    END
  END Tile_X1Y0_NN4BEG[7]
  PIN Tile_X1Y0_NN4BEG[8]
    DIRECTION OUTPUT ;
    USE SIGNAL ;
    ANTENNADIFFAREA 2.724000 ;
    PORT
      LAYER Metal2 ;
        RECT 315.160 78.980 315.560 79.380 ;
    END
  END Tile_X1Y0_NN4BEG[8]
  PIN Tile_X1Y0_NN4BEG[9]
    DIRECTION OUTPUT ;
    USE SIGNAL ;
    ANTENNADIFFAREA 2.724000 ;
    PORT
      LAYER Metal2 ;
        RECT 316.120 78.980 316.520 79.380 ;
    END
  END Tile_X1Y0_NN4BEG[9]
  PIN Tile_X1Y0_S1END[0]
    DIRECTION INPUT ;
    USE SIGNAL ;
    ANTENNAGATEAREA 0.607100 ;
    PORT
      LAYER Metal2 ;
        RECT 330.520 78.980 330.920 79.380 ;
    END
  END Tile_X1Y0_S1END[0]
  PIN Tile_X1Y0_S1END[1]
    DIRECTION INPUT ;
    USE SIGNAL ;
    ANTENNAGATEAREA 0.607100 ;
    PORT
      LAYER Metal2 ;
        RECT 332.440 78.980 332.840 79.380 ;
    END
  END Tile_X1Y0_S1END[1]
  PIN Tile_X1Y0_S1END[2]
    DIRECTION INPUT ;
    USE SIGNAL ;
    ANTENNAGATEAREA 0.607100 ;
    PORT
      LAYER Metal2 ;
        RECT 334.360 78.980 334.760 79.380 ;
    END
  END Tile_X1Y0_S1END[2]
  PIN Tile_X1Y0_S1END[3]
    DIRECTION INPUT ;
    USE SIGNAL ;
    ANTENNAGATEAREA 0.607100 ;
    PORT
      LAYER Metal2 ;
        RECT 336.280 78.980 336.680 79.380 ;
    END
  END Tile_X1Y0_S1END[3]
  PIN Tile_X1Y0_S2END[0]
    DIRECTION INPUT ;
    USE SIGNAL ;
    ANTENNAGATEAREA 0.639600 ;
    PORT
      LAYER Metal2 ;
        RECT 356.440 78.980 356.840 79.380 ;
    END
  END Tile_X1Y0_S2END[0]
  PIN Tile_X1Y0_S2END[1]
    DIRECTION INPUT ;
    USE SIGNAL ;
    ANTENNAGATEAREA 0.639600 ;
    PORT
      LAYER Metal2 ;
        RECT 357.400 78.980 357.800 79.380 ;
    END
  END Tile_X1Y0_S2END[1]
  PIN Tile_X1Y0_S2END[2]
    DIRECTION INPUT ;
    USE SIGNAL ;
    ANTENNAGATEAREA 0.639600 ;
    PORT
      LAYER Metal2 ;
        RECT 358.360 78.980 358.760 79.380 ;
    END
  END Tile_X1Y0_S2END[2]
  PIN Tile_X1Y0_S2END[3]
    DIRECTION INPUT ;
    USE SIGNAL ;
    ANTENNAGATEAREA 0.639600 ;
    PORT
      LAYER Metal2 ;
        RECT 359.320 78.980 359.720 79.380 ;
    END
  END Tile_X1Y0_S2END[3]
  PIN Tile_X1Y0_S2END[4]
    DIRECTION INPUT ;
    USE SIGNAL ;
    ANTENNAGATEAREA 0.639600 ;
    PORT
      LAYER Metal2 ;
        RECT 360.280 78.980 360.680 79.380 ;
    END
  END Tile_X1Y0_S2END[4]
  PIN Tile_X1Y0_S2END[5]
    DIRECTION INPUT ;
    USE SIGNAL ;
    ANTENNAGATEAREA 0.639600 ;
    PORT
      LAYER Metal2 ;
        RECT 361.240 78.980 361.640 79.380 ;
    END
  END Tile_X1Y0_S2END[5]
  PIN Tile_X1Y0_S2END[6]
    DIRECTION INPUT ;
    USE SIGNAL ;
    ANTENNAGATEAREA 0.639600 ;
    PORT
      LAYER Metal2 ;
        RECT 362.200 78.980 362.600 79.380 ;
    END
  END Tile_X1Y0_S2END[6]
  PIN Tile_X1Y0_S2END[7]
    DIRECTION INPUT ;
    USE SIGNAL ;
    ANTENNAGATEAREA 0.639600 ;
    PORT
      LAYER Metal2 ;
        RECT 363.160 78.980 363.560 79.380 ;
    END
  END Tile_X1Y0_S2END[7]
  PIN Tile_X1Y0_S2MID[0]
    DIRECTION INPUT ;
    USE SIGNAL ;
    ANTENNAGATEAREA 0.820300 ;
    PORT
      LAYER Metal2 ;
        RECT 338.200 78.980 338.600 79.380 ;
    END
  END Tile_X1Y0_S2MID[0]
  PIN Tile_X1Y0_S2MID[1]
    DIRECTION INPUT ;
    USE SIGNAL ;
    ANTENNAGATEAREA 0.820300 ;
    PORT
      LAYER Metal2 ;
        RECT 340.120 78.980 340.520 79.380 ;
    END
  END Tile_X1Y0_S2MID[1]
  PIN Tile_X1Y0_S2MID[2]
    DIRECTION INPUT ;
    USE SIGNAL ;
    ANTENNAGATEAREA 0.820300 ;
    PORT
      LAYER Metal2 ;
        RECT 342.040 78.980 342.440 79.380 ;
    END
  END Tile_X1Y0_S2MID[2]
  PIN Tile_X1Y0_S2MID[3]
    DIRECTION INPUT ;
    USE SIGNAL ;
    ANTENNAGATEAREA 0.820300 ;
    PORT
      LAYER Metal2 ;
        RECT 343.960 78.980 344.360 79.380 ;
    END
  END Tile_X1Y0_S2MID[3]
  PIN Tile_X1Y0_S2MID[4]
    DIRECTION INPUT ;
    USE SIGNAL ;
    ANTENNAGATEAREA 0.820300 ;
    PORT
      LAYER Metal2 ;
        RECT 345.880 78.980 346.280 79.380 ;
    END
  END Tile_X1Y0_S2MID[4]
  PIN Tile_X1Y0_S2MID[5]
    DIRECTION INPUT ;
    USE SIGNAL ;
    ANTENNAGATEAREA 0.820300 ;
    PORT
      LAYER Metal2 ;
        RECT 347.800 78.980 348.200 79.380 ;
    END
  END Tile_X1Y0_S2MID[5]
  PIN Tile_X1Y0_S2MID[6]
    DIRECTION INPUT ;
    USE SIGNAL ;
    ANTENNAGATEAREA 0.820300 ;
    PORT
      LAYER Metal2 ;
        RECT 349.720 78.980 350.120 79.380 ;
    END
  END Tile_X1Y0_S2MID[6]
  PIN Tile_X1Y0_S2MID[7]
    DIRECTION INPUT ;
    USE SIGNAL ;
    ANTENNAGATEAREA 0.820300 ;
    PORT
      LAYER Metal2 ;
        RECT 351.640 78.980 352.040 79.380 ;
    END
  END Tile_X1Y0_S2MID[7]
  PIN Tile_X1Y0_S4END[0]
    DIRECTION INPUT ;
    USE SIGNAL ;
    ANTENNAGATEAREA 0.852800 ;
    PORT
      LAYER Metal2 ;
        RECT 374.680 78.980 375.080 79.380 ;
    END
  END Tile_X1Y0_S4END[0]
  PIN Tile_X1Y0_S4END[10]
    DIRECTION INPUT ;
    USE SIGNAL ;
    ANTENNAGATEAREA 0.852800 ;
    PORT
      LAYER Metal2 ;
        RECT 384.280 78.980 384.680 79.380 ;
    END
  END Tile_X1Y0_S4END[10]
  PIN Tile_X1Y0_S4END[11]
    DIRECTION INPUT ;
    USE SIGNAL ;
    ANTENNAGATEAREA 0.852800 ;
    PORT
      LAYER Metal2 ;
        RECT 385.240 78.980 385.640 79.380 ;
    END
  END Tile_X1Y0_S4END[11]
  PIN Tile_X1Y0_S4END[12]
    DIRECTION INPUT ;
    USE SIGNAL ;
    ANTENNAGATEAREA 0.852800 ;
    PORT
      LAYER Metal2 ;
        RECT 386.200 78.980 386.600 79.380 ;
    END
  END Tile_X1Y0_S4END[12]
  PIN Tile_X1Y0_S4END[13]
    DIRECTION INPUT ;
    USE SIGNAL ;
    ANTENNAGATEAREA 0.852800 ;
    PORT
      LAYER Metal2 ;
        RECT 387.160 78.980 387.560 79.380 ;
    END
  END Tile_X1Y0_S4END[13]
  PIN Tile_X1Y0_S4END[14]
    DIRECTION INPUT ;
    USE SIGNAL ;
    ANTENNAGATEAREA 0.852800 ;
    PORT
      LAYER Metal2 ;
        RECT 388.120 78.980 388.520 79.380 ;
    END
  END Tile_X1Y0_S4END[14]
  PIN Tile_X1Y0_S4END[15]
    DIRECTION INPUT ;
    USE SIGNAL ;
    ANTENNAGATEAREA 0.852800 ;
    PORT
      LAYER Metal2 ;
        RECT 389.080 78.980 389.480 79.380 ;
    END
  END Tile_X1Y0_S4END[15]
  PIN Tile_X1Y0_S4END[1]
    DIRECTION INPUT ;
    USE SIGNAL ;
    ANTENNAGATEAREA 0.852800 ;
    PORT
      LAYER Metal2 ;
        RECT 375.640 78.980 376.040 79.380 ;
    END
  END Tile_X1Y0_S4END[1]
  PIN Tile_X1Y0_S4END[2]
    DIRECTION INPUT ;
    USE SIGNAL ;
    ANTENNAGATEAREA 0.852800 ;
    PORT
      LAYER Metal2 ;
        RECT 376.600 78.980 377.000 79.380 ;
    END
  END Tile_X1Y0_S4END[2]
  PIN Tile_X1Y0_S4END[3]
    DIRECTION INPUT ;
    USE SIGNAL ;
    ANTENNAGATEAREA 0.852800 ;
    PORT
      LAYER Metal2 ;
        RECT 377.560 78.980 377.960 79.380 ;
    END
  END Tile_X1Y0_S4END[3]
  PIN Tile_X1Y0_S4END[4]
    DIRECTION INPUT ;
    USE SIGNAL ;
    ANTENNAGATEAREA 0.852800 ;
    PORT
      LAYER Metal2 ;
        RECT 378.520 78.980 378.920 79.380 ;
    END
  END Tile_X1Y0_S4END[4]
  PIN Tile_X1Y0_S4END[5]
    DIRECTION INPUT ;
    USE SIGNAL ;
    ANTENNAGATEAREA 0.852800 ;
    PORT
      LAYER Metal2 ;
        RECT 379.480 78.980 379.880 79.380 ;
    END
  END Tile_X1Y0_S4END[5]
  PIN Tile_X1Y0_S4END[6]
    DIRECTION INPUT ;
    USE SIGNAL ;
    ANTENNAGATEAREA 0.852800 ;
    PORT
      LAYER Metal2 ;
        RECT 380.440 78.980 380.840 79.380 ;
    END
  END Tile_X1Y0_S4END[6]
  PIN Tile_X1Y0_S4END[7]
    DIRECTION INPUT ;
    USE SIGNAL ;
    ANTENNAGATEAREA 0.852800 ;
    PORT
      LAYER Metal2 ;
        RECT 381.400 78.980 381.800 79.380 ;
    END
  END Tile_X1Y0_S4END[7]
  PIN Tile_X1Y0_S4END[8]
    DIRECTION INPUT ;
    USE SIGNAL ;
    ANTENNAGATEAREA 0.852800 ;
    PORT
      LAYER Metal2 ;
        RECT 382.360 78.980 382.760 79.380 ;
    END
  END Tile_X1Y0_S4END[8]
  PIN Tile_X1Y0_S4END[9]
    DIRECTION INPUT ;
    USE SIGNAL ;
    ANTENNAGATEAREA 0.852800 ;
    PORT
      LAYER Metal2 ;
        RECT 383.320 78.980 383.720 79.380 ;
    END
  END Tile_X1Y0_S4END[9]
  PIN Tile_X1Y0_SS4END[0]
    DIRECTION INPUT ;
    USE SIGNAL ;
    ANTENNAGATEAREA 0.852800 ;
    PORT
      LAYER Metal2 ;
        RECT 404.440 78.980 404.840 79.380 ;
    END
  END Tile_X1Y0_SS4END[0]
  PIN Tile_X1Y0_SS4END[10]
    DIRECTION INPUT ;
    USE SIGNAL ;
    ANTENNAGATEAREA 0.852800 ;
    PORT
      LAYER Metal2 ;
        RECT 414.040 78.980 414.440 79.380 ;
    END
  END Tile_X1Y0_SS4END[10]
  PIN Tile_X1Y0_SS4END[11]
    DIRECTION INPUT ;
    USE SIGNAL ;
    ANTENNAGATEAREA 0.852800 ;
    PORT
      LAYER Metal2 ;
        RECT 415.000 78.980 415.400 79.380 ;
    END
  END Tile_X1Y0_SS4END[11]
  PIN Tile_X1Y0_SS4END[12]
    DIRECTION INPUT ;
    USE SIGNAL ;
    ANTENNAGATEAREA 0.852800 ;
    PORT
      LAYER Metal2 ;
        RECT 415.960 78.980 416.360 79.380 ;
    END
  END Tile_X1Y0_SS4END[12]
  PIN Tile_X1Y0_SS4END[13]
    DIRECTION INPUT ;
    USE SIGNAL ;
    ANTENNAGATEAREA 0.852800 ;
    ANTENNADIFFAREA 32.246399 ;
    PORT
      LAYER Metal2 ;
        RECT 416.920 78.980 417.320 79.380 ;
    END
  END Tile_X1Y0_SS4END[13]
  PIN Tile_X1Y0_SS4END[14]
    DIRECTION INPUT ;
    USE SIGNAL ;
    ANTENNAGATEAREA 0.852800 ;
    PORT
      LAYER Metal2 ;
        RECT 417.880 78.980 418.280 79.380 ;
    END
  END Tile_X1Y0_SS4END[14]
  PIN Tile_X1Y0_SS4END[15]
    DIRECTION INPUT ;
    USE SIGNAL ;
    ANTENNAGATEAREA 0.852800 ;
    ANTENNADIFFAREA 32.246399 ;
    PORT
      LAYER Metal2 ;
        RECT 418.840 78.980 419.240 79.380 ;
    END
  END Tile_X1Y0_SS4END[15]
  PIN Tile_X1Y0_SS4END[1]
    DIRECTION INPUT ;
    USE SIGNAL ;
    ANTENNAGATEAREA 0.852800 ;
    PORT
      LAYER Metal2 ;
        RECT 405.400 78.980 405.800 79.380 ;
    END
  END Tile_X1Y0_SS4END[1]
  PIN Tile_X1Y0_SS4END[2]
    DIRECTION INPUT ;
    USE SIGNAL ;
    ANTENNAGATEAREA 0.852800 ;
    PORT
      LAYER Metal2 ;
        RECT 406.360 78.980 406.760 79.380 ;
    END
  END Tile_X1Y0_SS4END[2]
  PIN Tile_X1Y0_SS4END[3]
    DIRECTION INPUT ;
    USE SIGNAL ;
    ANTENNAGATEAREA 0.852800 ;
    PORT
      LAYER Metal2 ;
        RECT 407.320 78.980 407.720 79.380 ;
    END
  END Tile_X1Y0_SS4END[3]
  PIN Tile_X1Y0_SS4END[4]
    DIRECTION INPUT ;
    USE SIGNAL ;
    ANTENNAGATEAREA 0.852800 ;
    PORT
      LAYER Metal2 ;
        RECT 408.280 78.980 408.680 79.380 ;
    END
  END Tile_X1Y0_SS4END[4]
  PIN Tile_X1Y0_SS4END[5]
    DIRECTION INPUT ;
    USE SIGNAL ;
    ANTENNAGATEAREA 0.852800 ;
    ANTENNADIFFAREA 16.123199 ;
    PORT
      LAYER Metal2 ;
        RECT 409.240 78.980 409.640 79.380 ;
    END
  END Tile_X1Y0_SS4END[5]
  PIN Tile_X1Y0_SS4END[6]
    DIRECTION INPUT ;
    USE SIGNAL ;
    ANTENNAGATEAREA 0.852800 ;
    PORT
      LAYER Metal2 ;
        RECT 410.200 78.980 410.600 79.380 ;
    END
  END Tile_X1Y0_SS4END[6]
  PIN Tile_X1Y0_SS4END[7]
    DIRECTION INPUT ;
    USE SIGNAL ;
    ANTENNAGATEAREA 0.852800 ;
    PORT
      LAYER Metal2 ;
        RECT 411.160 78.980 411.560 79.380 ;
    END
  END Tile_X1Y0_SS4END[7]
  PIN Tile_X1Y0_SS4END[8]
    DIRECTION INPUT ;
    USE SIGNAL ;
    ANTENNAGATEAREA 0.852800 ;
    PORT
      LAYER Metal2 ;
        RECT 412.120 78.980 412.520 79.380 ;
    END
  END Tile_X1Y0_SS4END[8]
  PIN Tile_X1Y0_SS4END[9]
    DIRECTION INPUT ;
    USE SIGNAL ;
    ANTENNAGATEAREA 0.852800 ;
    PORT
      LAYER Metal2 ;
        RECT 413.080 78.980 413.480 79.380 ;
    END
  END Tile_X1Y0_SS4END[9]
  PIN Tile_X2Y0_Co
    DIRECTION OUTPUT ;
    USE SIGNAL ;
    ANTENNADIFFAREA 2.314600 ;
    PORT
      LAYER Metal2 ;
        RECT 660.760 78.980 661.160 79.380 ;
    END
  END Tile_X2Y0_Co
  PIN Tile_X2Y0_FrameStrobe[0]
    DIRECTION INPUT ;
    USE SIGNAL ;
    ANTENNAGATEAREA 11.745500 ;
    PORT
      LAYER Metal2 ;
        RECT 473.560 0.000 473.960 0.400 ;
    END
  END Tile_X2Y0_FrameStrobe[0]
  PIN Tile_X2Y0_FrameStrobe[10]
    DIRECTION INPUT ;
    USE SIGNAL ;
    ANTENNAGATEAREA 0.180700 ;
    PORT
      LAYER Metal2 ;
        RECT 588.760 0.000 589.160 0.400 ;
    END
  END Tile_X2Y0_FrameStrobe[10]
  PIN Tile_X2Y0_FrameStrobe[11]
    DIRECTION INPUT ;
    USE SIGNAL ;
    ANTENNAGATEAREA 0.180700 ;
    PORT
      LAYER Metal2 ;
        RECT 600.280 0.000 600.680 0.400 ;
    END
  END Tile_X2Y0_FrameStrobe[11]
  PIN Tile_X2Y0_FrameStrobe[12]
    DIRECTION INPUT ;
    USE SIGNAL ;
    ANTENNAGATEAREA 0.180700 ;
    PORT
      LAYER Metal2 ;
        RECT 611.800 0.000 612.200 0.400 ;
    END
  END Tile_X2Y0_FrameStrobe[12]
  PIN Tile_X2Y0_FrameStrobe[13]
    DIRECTION INPUT ;
    USE SIGNAL ;
    ANTENNAGATEAREA 0.180700 ;
    PORT
      LAYER Metal2 ;
        RECT 623.320 0.000 623.720 0.400 ;
    END
  END Tile_X2Y0_FrameStrobe[13]
  PIN Tile_X2Y0_FrameStrobe[14]
    DIRECTION INPUT ;
    USE SIGNAL ;
    ANTENNAGATEAREA 0.180700 ;
    PORT
      LAYER Metal2 ;
        RECT 634.840 0.000 635.240 0.400 ;
    END
  END Tile_X2Y0_FrameStrobe[14]
  PIN Tile_X2Y0_FrameStrobe[15]
    DIRECTION INPUT ;
    USE SIGNAL ;
    ANTENNAGATEAREA 0.180700 ;
    PORT
      LAYER Metal2 ;
        RECT 646.360 0.000 646.760 0.400 ;
    END
  END Tile_X2Y0_FrameStrobe[15]
  PIN Tile_X2Y0_FrameStrobe[16]
    DIRECTION INPUT ;
    USE SIGNAL ;
    ANTENNAGATEAREA 0.180700 ;
    PORT
      LAYER Metal2 ;
        RECT 657.880 0.000 658.280 0.400 ;
    END
  END Tile_X2Y0_FrameStrobe[16]
  PIN Tile_X2Y0_FrameStrobe[17]
    DIRECTION INPUT ;
    USE SIGNAL ;
    ANTENNAGATEAREA 0.180700 ;
    PORT
      LAYER Metal2 ;
        RECT 669.400 0.000 669.800 0.400 ;
    END
  END Tile_X2Y0_FrameStrobe[17]
  PIN Tile_X2Y0_FrameStrobe[18]
    DIRECTION INPUT ;
    USE SIGNAL ;
    ANTENNAGATEAREA 0.180700 ;
    PORT
      LAYER Metal2 ;
        RECT 680.920 0.000 681.320 0.400 ;
    END
  END Tile_X2Y0_FrameStrobe[18]
  PIN Tile_X2Y0_FrameStrobe[19]
    DIRECTION INPUT ;
    USE SIGNAL ;
    ANTENNAGATEAREA 0.180700 ;
    PORT
      LAYER Metal2 ;
        RECT 692.440 0.000 692.840 0.400 ;
    END
  END Tile_X2Y0_FrameStrobe[19]
  PIN Tile_X2Y0_FrameStrobe[1]
    DIRECTION INPUT ;
    USE SIGNAL ;
    ANTENNAGATEAREA 11.745500 ;
    PORT
      LAYER Metal2 ;
        RECT 485.080 0.000 485.480 0.400 ;
    END
  END Tile_X2Y0_FrameStrobe[1]
  PIN Tile_X2Y0_FrameStrobe[2]
    DIRECTION INPUT ;
    USE SIGNAL ;
    ANTENNAGATEAREA 11.745500 ;
    PORT
      LAYER Metal2 ;
        RECT 496.600 0.000 497.000 0.400 ;
    END
  END Tile_X2Y0_FrameStrobe[2]
  PIN Tile_X2Y0_FrameStrobe[3]
    DIRECTION INPUT ;
    USE SIGNAL ;
    ANTENNAGATEAREA 0.180700 ;
    PORT
      LAYER Metal2 ;
        RECT 508.120 0.000 508.520 0.400 ;
    END
  END Tile_X2Y0_FrameStrobe[3]
  PIN Tile_X2Y0_FrameStrobe[4]
    DIRECTION INPUT ;
    USE SIGNAL ;
    ANTENNAGATEAREA 0.180700 ;
    PORT
      LAYER Metal2 ;
        RECT 519.640 0.000 520.040 0.400 ;
    END
  END Tile_X2Y0_FrameStrobe[4]
  PIN Tile_X2Y0_FrameStrobe[5]
    DIRECTION INPUT ;
    USE SIGNAL ;
    ANTENNAGATEAREA 0.180700 ;
    PORT
      LAYER Metal2 ;
        RECT 531.160 0.000 531.560 0.400 ;
    END
  END Tile_X2Y0_FrameStrobe[5]
  PIN Tile_X2Y0_FrameStrobe[6]
    DIRECTION INPUT ;
    USE SIGNAL ;
    ANTENNAGATEAREA 0.180700 ;
    PORT
      LAYER Metal2 ;
        RECT 542.680 0.000 543.080 0.400 ;
    END
  END Tile_X2Y0_FrameStrobe[6]
  PIN Tile_X2Y0_FrameStrobe[7]
    DIRECTION INPUT ;
    USE SIGNAL ;
    ANTENNAGATEAREA 0.180700 ;
    PORT
      LAYER Metal2 ;
        RECT 554.200 0.000 554.600 0.400 ;
    END
  END Tile_X2Y0_FrameStrobe[7]
  PIN Tile_X2Y0_FrameStrobe[8]
    DIRECTION INPUT ;
    USE SIGNAL ;
    ANTENNAGATEAREA 0.180700 ;
    PORT
      LAYER Metal2 ;
        RECT 565.720 0.000 566.120 0.400 ;
    END
  END Tile_X2Y0_FrameStrobe[8]
  PIN Tile_X2Y0_FrameStrobe[9]
    DIRECTION INPUT ;
    USE SIGNAL ;
    ANTENNAGATEAREA 0.180700 ;
    PORT
      LAYER Metal2 ;
        RECT 577.240 0.000 577.640 0.400 ;
    END
  END Tile_X2Y0_FrameStrobe[9]
  PIN Tile_X2Y0_FrameStrobe_O[0]
    DIRECTION OUTPUT ;
    USE SIGNAL ;
    ANTENNADIFFAREA 2.724000 ;
    PORT
      LAYER Metal2 ;
        RECT 671.320 78.980 671.720 79.380 ;
    END
  END Tile_X2Y0_FrameStrobe_O[0]
  PIN Tile_X2Y0_FrameStrobe_O[10]
    DIRECTION OUTPUT ;
    USE SIGNAL ;
    ANTENNADIFFAREA 2.724000 ;
    PORT
      LAYER Metal2 ;
        RECT 680.920 78.980 681.320 79.380 ;
    END
  END Tile_X2Y0_FrameStrobe_O[10]
  PIN Tile_X2Y0_FrameStrobe_O[11]
    DIRECTION OUTPUT ;
    USE SIGNAL ;
    ANTENNADIFFAREA 2.724000 ;
    PORT
      LAYER Metal2 ;
        RECT 681.880 78.980 682.280 79.380 ;
    END
  END Tile_X2Y0_FrameStrobe_O[11]
  PIN Tile_X2Y0_FrameStrobe_O[12]
    DIRECTION OUTPUT ;
    USE SIGNAL ;
    ANTENNADIFFAREA 2.724000 ;
    PORT
      LAYER Metal2 ;
        RECT 682.840 78.980 683.240 79.380 ;
    END
  END Tile_X2Y0_FrameStrobe_O[12]
  PIN Tile_X2Y0_FrameStrobe_O[13]
    DIRECTION OUTPUT ;
    USE SIGNAL ;
    ANTENNADIFFAREA 2.724000 ;
    PORT
      LAYER Metal2 ;
        RECT 683.800 78.980 684.200 79.380 ;
    END
  END Tile_X2Y0_FrameStrobe_O[13]
  PIN Tile_X2Y0_FrameStrobe_O[14]
    DIRECTION OUTPUT ;
    USE SIGNAL ;
    ANTENNADIFFAREA 2.724000 ;
    PORT
      LAYER Metal2 ;
        RECT 684.760 78.980 685.160 79.380 ;
    END
  END Tile_X2Y0_FrameStrobe_O[14]
  PIN Tile_X2Y0_FrameStrobe_O[15]
    DIRECTION OUTPUT ;
    USE SIGNAL ;
    ANTENNADIFFAREA 2.724000 ;
    PORT
      LAYER Metal2 ;
        RECT 685.720 78.980 686.120 79.380 ;
    END
  END Tile_X2Y0_FrameStrobe_O[15]
  PIN Tile_X2Y0_FrameStrobe_O[16]
    DIRECTION OUTPUT ;
    USE SIGNAL ;
    ANTENNADIFFAREA 2.724000 ;
    PORT
      LAYER Metal2 ;
        RECT 686.680 78.980 687.080 79.380 ;
    END
  END Tile_X2Y0_FrameStrobe_O[16]
  PIN Tile_X2Y0_FrameStrobe_O[17]
    DIRECTION OUTPUT ;
    USE SIGNAL ;
    ANTENNADIFFAREA 2.724000 ;
    PORT
      LAYER Metal2 ;
        RECT 687.640 78.980 688.040 79.380 ;
    END
  END Tile_X2Y0_FrameStrobe_O[17]
  PIN Tile_X2Y0_FrameStrobe_O[18]
    DIRECTION OUTPUT ;
    USE SIGNAL ;
    ANTENNADIFFAREA 2.724000 ;
    PORT
      LAYER Metal2 ;
        RECT 688.600 78.980 689.000 79.380 ;
    END
  END Tile_X2Y0_FrameStrobe_O[18]
  PIN Tile_X2Y0_FrameStrobe_O[19]
    DIRECTION OUTPUT ;
    USE SIGNAL ;
    ANTENNADIFFAREA 2.724000 ;
    PORT
      LAYER Metal2 ;
        RECT 689.560 78.980 689.960 79.380 ;
    END
  END Tile_X2Y0_FrameStrobe_O[19]
  PIN Tile_X2Y0_FrameStrobe_O[1]
    DIRECTION OUTPUT ;
    USE SIGNAL ;
    ANTENNADIFFAREA 2.724000 ;
    PORT
      LAYER Metal2 ;
        RECT 672.280 78.980 672.680 79.380 ;
    END
  END Tile_X2Y0_FrameStrobe_O[1]
  PIN Tile_X2Y0_FrameStrobe_O[2]
    DIRECTION OUTPUT ;
    USE SIGNAL ;
    ANTENNADIFFAREA 2.724000 ;
    PORT
      LAYER Metal2 ;
        RECT 673.240 78.980 673.640 79.380 ;
    END
  END Tile_X2Y0_FrameStrobe_O[2]
  PIN Tile_X2Y0_FrameStrobe_O[3]
    DIRECTION OUTPUT ;
    USE SIGNAL ;
    ANTENNADIFFAREA 2.724000 ;
    PORT
      LAYER Metal2 ;
        RECT 674.200 78.980 674.600 79.380 ;
    END
  END Tile_X2Y0_FrameStrobe_O[3]
  PIN Tile_X2Y0_FrameStrobe_O[4]
    DIRECTION OUTPUT ;
    USE SIGNAL ;
    ANTENNADIFFAREA 2.724000 ;
    PORT
      LAYER Metal2 ;
        RECT 675.160 78.980 675.560 79.380 ;
    END
  END Tile_X2Y0_FrameStrobe_O[4]
  PIN Tile_X2Y0_FrameStrobe_O[5]
    DIRECTION OUTPUT ;
    USE SIGNAL ;
    ANTENNADIFFAREA 2.724000 ;
    PORT
      LAYER Metal2 ;
        RECT 676.120 78.980 676.520 79.380 ;
    END
  END Tile_X2Y0_FrameStrobe_O[5]
  PIN Tile_X2Y0_FrameStrobe_O[6]
    DIRECTION OUTPUT ;
    USE SIGNAL ;
    ANTENNADIFFAREA 2.724000 ;
    PORT
      LAYER Metal2 ;
        RECT 677.080 78.980 677.480 79.380 ;
    END
  END Tile_X2Y0_FrameStrobe_O[6]
  PIN Tile_X2Y0_FrameStrobe_O[7]
    DIRECTION OUTPUT ;
    USE SIGNAL ;
    ANTENNADIFFAREA 2.724000 ;
    PORT
      LAYER Metal2 ;
        RECT 678.040 78.980 678.440 79.380 ;
    END
  END Tile_X2Y0_FrameStrobe_O[7]
  PIN Tile_X2Y0_FrameStrobe_O[8]
    DIRECTION OUTPUT ;
    USE SIGNAL ;
    ANTENNADIFFAREA 2.724000 ;
    PORT
      LAYER Metal2 ;
        RECT 679.000 78.980 679.400 79.380 ;
    END
  END Tile_X2Y0_FrameStrobe_O[8]
  PIN Tile_X2Y0_FrameStrobe_O[9]
    DIRECTION OUTPUT ;
    USE SIGNAL ;
    ANTENNADIFFAREA 2.724000 ;
    PORT
      LAYER Metal2 ;
        RECT 679.960 78.980 680.360 79.380 ;
    END
  END Tile_X2Y0_FrameStrobe_O[9]
  PIN Tile_X2Y0_N1BEG[0]
    DIRECTION OUTPUT ;
    USE SIGNAL ;
    ANTENNADIFFAREA 2.724000 ;
    PORT
      LAYER Metal2 ;
        RECT 467.800 78.980 468.200 79.380 ;
    END
  END Tile_X2Y0_N1BEG[0]
  PIN Tile_X2Y0_N1BEG[1]
    DIRECTION OUTPUT ;
    USE SIGNAL ;
    ANTENNADIFFAREA 2.724000 ;
    PORT
      LAYER Metal2 ;
        RECT 469.720 78.980 470.120 79.380 ;
    END
  END Tile_X2Y0_N1BEG[1]
  PIN Tile_X2Y0_N1BEG[2]
    DIRECTION OUTPUT ;
    USE SIGNAL ;
    ANTENNADIFFAREA 2.724000 ;
    PORT
      LAYER Metal2 ;
        RECT 471.640 78.980 472.040 79.380 ;
    END
  END Tile_X2Y0_N1BEG[2]
  PIN Tile_X2Y0_N1BEG[3]
    DIRECTION OUTPUT ;
    USE SIGNAL ;
    ANTENNADIFFAREA 2.724000 ;
    PORT
      LAYER Metal2 ;
        RECT 473.560 78.980 473.960 79.380 ;
    END
  END Tile_X2Y0_N1BEG[3]
  PIN Tile_X2Y0_N2BEG[0]
    DIRECTION OUTPUT ;
    USE SIGNAL ;
    ANTENNADIFFAREA 2.724000 ;
    PORT
      LAYER Metal2 ;
        RECT 478.360 78.980 478.760 79.380 ;
    END
  END Tile_X2Y0_N2BEG[0]
  PIN Tile_X2Y0_N2BEG[1]
    DIRECTION OUTPUT ;
    USE SIGNAL ;
    ANTENNADIFFAREA 2.724000 ;
    PORT
      LAYER Metal2 ;
        RECT 479.320 78.980 479.720 79.380 ;
    END
  END Tile_X2Y0_N2BEG[1]
  PIN Tile_X2Y0_N2BEG[2]
    DIRECTION OUTPUT ;
    USE SIGNAL ;
    ANTENNADIFFAREA 2.724000 ;
    PORT
      LAYER Metal2 ;
        RECT 480.280 78.980 480.680 79.380 ;
    END
  END Tile_X2Y0_N2BEG[2]
  PIN Tile_X2Y0_N2BEG[3]
    DIRECTION OUTPUT ;
    USE SIGNAL ;
    ANTENNADIFFAREA 2.724000 ;
    PORT
      LAYER Metal2 ;
        RECT 481.240 78.980 481.640 79.380 ;
    END
  END Tile_X2Y0_N2BEG[3]
  PIN Tile_X2Y0_N2BEG[4]
    DIRECTION OUTPUT ;
    USE SIGNAL ;
    ANTENNADIFFAREA 2.724000 ;
    PORT
      LAYER Metal2 ;
        RECT 482.200 78.980 482.600 79.380 ;
    END
  END Tile_X2Y0_N2BEG[4]
  PIN Tile_X2Y0_N2BEG[5]
    DIRECTION OUTPUT ;
    USE SIGNAL ;
    ANTENNADIFFAREA 2.724000 ;
    PORT
      LAYER Metal2 ;
        RECT 483.160 78.980 483.560 79.380 ;
    END
  END Tile_X2Y0_N2BEG[5]
  PIN Tile_X2Y0_N2BEG[6]
    DIRECTION OUTPUT ;
    USE SIGNAL ;
    ANTENNADIFFAREA 2.724000 ;
    PORT
      LAYER Metal2 ;
        RECT 484.120 78.980 484.520 79.380 ;
    END
  END Tile_X2Y0_N2BEG[6]
  PIN Tile_X2Y0_N2BEG[7]
    DIRECTION OUTPUT ;
    USE SIGNAL ;
    ANTENNADIFFAREA 2.724000 ;
    PORT
      LAYER Metal2 ;
        RECT 485.080 78.980 485.480 79.380 ;
    END
  END Tile_X2Y0_N2BEG[7]
  PIN Tile_X2Y0_N2BEGb[0]
    DIRECTION OUTPUT ;
    USE SIGNAL ;
    ANTENNADIFFAREA 2.724000 ;
    PORT
      LAYER Metal2 ;
        RECT 492.760 78.980 493.160 79.380 ;
    END
  END Tile_X2Y0_N2BEGb[0]
  PIN Tile_X2Y0_N2BEGb[1]
    DIRECTION OUTPUT ;
    USE SIGNAL ;
    ANTENNADIFFAREA 2.724000 ;
    PORT
      LAYER Metal2 ;
        RECT 493.720 78.980 494.120 79.380 ;
    END
  END Tile_X2Y0_N2BEGb[1]
  PIN Tile_X2Y0_N2BEGb[2]
    DIRECTION OUTPUT ;
    USE SIGNAL ;
    ANTENNADIFFAREA 2.724000 ;
    PORT
      LAYER Metal2 ;
        RECT 494.680 78.980 495.080 79.380 ;
    END
  END Tile_X2Y0_N2BEGb[2]
  PIN Tile_X2Y0_N2BEGb[3]
    DIRECTION OUTPUT ;
    USE SIGNAL ;
    ANTENNADIFFAREA 2.724000 ;
    PORT
      LAYER Metal2 ;
        RECT 495.640 78.980 496.040 79.380 ;
    END
  END Tile_X2Y0_N2BEGb[3]
  PIN Tile_X2Y0_N2BEGb[4]
    DIRECTION OUTPUT ;
    USE SIGNAL ;
    ANTENNADIFFAREA 2.724000 ;
    PORT
      LAYER Metal2 ;
        RECT 496.600 78.980 497.000 79.380 ;
    END
  END Tile_X2Y0_N2BEGb[4]
  PIN Tile_X2Y0_N2BEGb[5]
    DIRECTION OUTPUT ;
    USE SIGNAL ;
    ANTENNADIFFAREA 2.724000 ;
    PORT
      LAYER Metal2 ;
        RECT 497.560 78.980 497.960 79.380 ;
    END
  END Tile_X2Y0_N2BEGb[5]
  PIN Tile_X2Y0_N2BEGb[6]
    DIRECTION OUTPUT ;
    USE SIGNAL ;
    ANTENNADIFFAREA 2.724000 ;
    PORT
      LAYER Metal2 ;
        RECT 498.520 78.980 498.920 79.380 ;
    END
  END Tile_X2Y0_N2BEGb[6]
  PIN Tile_X2Y0_N2BEGb[7]
    DIRECTION OUTPUT ;
    USE SIGNAL ;
    ANTENNADIFFAREA 2.724000 ;
    PORT
      LAYER Metal2 ;
        RECT 499.480 78.980 499.880 79.380 ;
    END
  END Tile_X2Y0_N2BEGb[7]
  PIN Tile_X2Y0_N4BEG[0]
    DIRECTION OUTPUT ;
    USE SIGNAL ;
    ANTENNADIFFAREA 2.724000 ;
    PORT
      LAYER Metal2 ;
        RECT 511.000 78.980 511.400 79.380 ;
    END
  END Tile_X2Y0_N4BEG[0]
  PIN Tile_X2Y0_N4BEG[10]
    DIRECTION OUTPUT ;
    USE SIGNAL ;
    ANTENNADIFFAREA 2.724000 ;
    PORT
      LAYER Metal2 ;
        RECT 520.600 78.980 521.000 79.380 ;
    END
  END Tile_X2Y0_N4BEG[10]
  PIN Tile_X2Y0_N4BEG[11]
    DIRECTION OUTPUT ;
    USE SIGNAL ;
    ANTENNADIFFAREA 2.724000 ;
    PORT
      LAYER Metal2 ;
        RECT 521.560 78.980 521.960 79.380 ;
    END
  END Tile_X2Y0_N4BEG[11]
  PIN Tile_X2Y0_N4BEG[12]
    DIRECTION OUTPUT ;
    USE SIGNAL ;
    ANTENNADIFFAREA 2.724000 ;
    PORT
      LAYER Metal2 ;
        RECT 522.520 78.980 522.920 79.380 ;
    END
  END Tile_X2Y0_N4BEG[12]
  PIN Tile_X2Y0_N4BEG[13]
    DIRECTION OUTPUT ;
    USE SIGNAL ;
    ANTENNADIFFAREA 2.724000 ;
    PORT
      LAYER Metal2 ;
        RECT 523.480 78.980 523.880 79.380 ;
    END
  END Tile_X2Y0_N4BEG[13]
  PIN Tile_X2Y0_N4BEG[14]
    DIRECTION OUTPUT ;
    USE SIGNAL ;
    ANTENNADIFFAREA 2.724000 ;
    PORT
      LAYER Metal2 ;
        RECT 524.440 78.980 524.840 79.380 ;
    END
  END Tile_X2Y0_N4BEG[14]
  PIN Tile_X2Y0_N4BEG[15]
    DIRECTION OUTPUT ;
    USE SIGNAL ;
    ANTENNADIFFAREA 2.724000 ;
    PORT
      LAYER Metal2 ;
        RECT 525.400 78.980 525.800 79.380 ;
    END
  END Tile_X2Y0_N4BEG[15]
  PIN Tile_X2Y0_N4BEG[1]
    DIRECTION OUTPUT ;
    USE SIGNAL ;
    ANTENNADIFFAREA 2.724000 ;
    PORT
      LAYER Metal2 ;
        RECT 511.960 78.980 512.360 79.380 ;
    END
  END Tile_X2Y0_N4BEG[1]
  PIN Tile_X2Y0_N4BEG[2]
    DIRECTION OUTPUT ;
    USE SIGNAL ;
    ANTENNADIFFAREA 2.724000 ;
    PORT
      LAYER Metal2 ;
        RECT 512.920 78.980 513.320 79.380 ;
    END
  END Tile_X2Y0_N4BEG[2]
  PIN Tile_X2Y0_N4BEG[3]
    DIRECTION OUTPUT ;
    USE SIGNAL ;
    ANTENNADIFFAREA 2.724000 ;
    PORT
      LAYER Metal2 ;
        RECT 513.880 78.980 514.280 79.380 ;
    END
  END Tile_X2Y0_N4BEG[3]
  PIN Tile_X2Y0_N4BEG[4]
    DIRECTION OUTPUT ;
    USE SIGNAL ;
    ANTENNADIFFAREA 2.724000 ;
    PORT
      LAYER Metal2 ;
        RECT 514.840 78.980 515.240 79.380 ;
    END
  END Tile_X2Y0_N4BEG[4]
  PIN Tile_X2Y0_N4BEG[5]
    DIRECTION OUTPUT ;
    USE SIGNAL ;
    ANTENNADIFFAREA 2.724000 ;
    PORT
      LAYER Metal2 ;
        RECT 515.800 78.980 516.200 79.380 ;
    END
  END Tile_X2Y0_N4BEG[5]
  PIN Tile_X2Y0_N4BEG[6]
    DIRECTION OUTPUT ;
    USE SIGNAL ;
    ANTENNADIFFAREA 2.724000 ;
    PORT
      LAYER Metal2 ;
        RECT 516.760 78.980 517.160 79.380 ;
    END
  END Tile_X2Y0_N4BEG[6]
  PIN Tile_X2Y0_N4BEG[7]
    DIRECTION OUTPUT ;
    USE SIGNAL ;
    ANTENNADIFFAREA 2.724000 ;
    PORT
      LAYER Metal2 ;
        RECT 517.720 78.980 518.120 79.380 ;
    END
  END Tile_X2Y0_N4BEG[7]
  PIN Tile_X2Y0_N4BEG[8]
    DIRECTION OUTPUT ;
    USE SIGNAL ;
    ANTENNADIFFAREA 2.724000 ;
    PORT
      LAYER Metal2 ;
        RECT 518.680 78.980 519.080 79.380 ;
    END
  END Tile_X2Y0_N4BEG[8]
  PIN Tile_X2Y0_N4BEG[9]
    DIRECTION OUTPUT ;
    USE SIGNAL ;
    ANTENNADIFFAREA 2.724000 ;
    PORT
      LAYER Metal2 ;
        RECT 519.640 78.980 520.040 79.380 ;
    END
  END Tile_X2Y0_N4BEG[9]
  PIN Tile_X2Y0_NN4BEG[0]
    DIRECTION OUTPUT ;
    USE SIGNAL ;
    ANTENNADIFFAREA 2.724000 ;
    PORT
      LAYER Metal2 ;
        RECT 540.760 78.980 541.160 79.380 ;
    END
  END Tile_X2Y0_NN4BEG[0]
  PIN Tile_X2Y0_NN4BEG[10]
    DIRECTION OUTPUT ;
    USE SIGNAL ;
    ANTENNADIFFAREA 2.724000 ;
    PORT
      LAYER Metal2 ;
        RECT 550.360 78.980 550.760 79.380 ;
    END
  END Tile_X2Y0_NN4BEG[10]
  PIN Tile_X2Y0_NN4BEG[11]
    DIRECTION OUTPUT ;
    USE SIGNAL ;
    ANTENNADIFFAREA 2.724000 ;
    PORT
      LAYER Metal2 ;
        RECT 551.320 78.980 551.720 79.380 ;
    END
  END Tile_X2Y0_NN4BEG[11]
  PIN Tile_X2Y0_NN4BEG[12]
    DIRECTION OUTPUT ;
    USE SIGNAL ;
    ANTENNADIFFAREA 2.724000 ;
    PORT
      LAYER Metal2 ;
        RECT 552.280 78.980 552.680 79.380 ;
    END
  END Tile_X2Y0_NN4BEG[12]
  PIN Tile_X2Y0_NN4BEG[13]
    DIRECTION OUTPUT ;
    USE SIGNAL ;
    ANTENNADIFFAREA 2.724000 ;
    PORT
      LAYER Metal2 ;
        RECT 553.240 78.980 553.640 79.380 ;
    END
  END Tile_X2Y0_NN4BEG[13]
  PIN Tile_X2Y0_NN4BEG[14]
    DIRECTION OUTPUT ;
    USE SIGNAL ;
    ANTENNADIFFAREA 2.724000 ;
    PORT
      LAYER Metal2 ;
        RECT 554.200 78.980 554.600 79.380 ;
    END
  END Tile_X2Y0_NN4BEG[14]
  PIN Tile_X2Y0_NN4BEG[15]
    DIRECTION OUTPUT ;
    USE SIGNAL ;
    ANTENNADIFFAREA 2.724000 ;
    PORT
      LAYER Metal2 ;
        RECT 555.160 78.980 555.560 79.380 ;
    END
  END Tile_X2Y0_NN4BEG[15]
  PIN Tile_X2Y0_NN4BEG[1]
    DIRECTION OUTPUT ;
    USE SIGNAL ;
    ANTENNADIFFAREA 2.724000 ;
    PORT
      LAYER Metal2 ;
        RECT 541.720 78.980 542.120 79.380 ;
    END
  END Tile_X2Y0_NN4BEG[1]
  PIN Tile_X2Y0_NN4BEG[2]
    DIRECTION OUTPUT ;
    USE SIGNAL ;
    ANTENNADIFFAREA 2.724000 ;
    PORT
      LAYER Metal2 ;
        RECT 542.680 78.980 543.080 79.380 ;
    END
  END Tile_X2Y0_NN4BEG[2]
  PIN Tile_X2Y0_NN4BEG[3]
    DIRECTION OUTPUT ;
    USE SIGNAL ;
    ANTENNADIFFAREA 2.724000 ;
    PORT
      LAYER Metal2 ;
        RECT 543.640 78.980 544.040 79.380 ;
    END
  END Tile_X2Y0_NN4BEG[3]
  PIN Tile_X2Y0_NN4BEG[4]
    DIRECTION OUTPUT ;
    USE SIGNAL ;
    ANTENNADIFFAREA 2.724000 ;
    PORT
      LAYER Metal2 ;
        RECT 544.600 78.980 545.000 79.380 ;
    END
  END Tile_X2Y0_NN4BEG[4]
  PIN Tile_X2Y0_NN4BEG[5]
    DIRECTION OUTPUT ;
    USE SIGNAL ;
    ANTENNADIFFAREA 2.724000 ;
    PORT
      LAYER Metal2 ;
        RECT 545.560 78.980 545.960 79.380 ;
    END
  END Tile_X2Y0_NN4BEG[5]
  PIN Tile_X2Y0_NN4BEG[6]
    DIRECTION OUTPUT ;
    USE SIGNAL ;
    ANTENNADIFFAREA 2.724000 ;
    PORT
      LAYER Metal2 ;
        RECT 546.520 78.980 546.920 79.380 ;
    END
  END Tile_X2Y0_NN4BEG[6]
  PIN Tile_X2Y0_NN4BEG[7]
    DIRECTION OUTPUT ;
    USE SIGNAL ;
    ANTENNADIFFAREA 2.724000 ;
    PORT
      LAYER Metal2 ;
        RECT 547.480 78.980 547.880 79.380 ;
    END
  END Tile_X2Y0_NN4BEG[7]
  PIN Tile_X2Y0_NN4BEG[8]
    DIRECTION OUTPUT ;
    USE SIGNAL ;
    ANTENNADIFFAREA 2.724000 ;
    PORT
      LAYER Metal2 ;
        RECT 548.440 78.980 548.840 79.380 ;
    END
  END Tile_X2Y0_NN4BEG[8]
  PIN Tile_X2Y0_NN4BEG[9]
    DIRECTION OUTPUT ;
    USE SIGNAL ;
    ANTENNADIFFAREA 2.724000 ;
    PORT
      LAYER Metal2 ;
        RECT 549.400 78.980 549.800 79.380 ;
    END
  END Tile_X2Y0_NN4BEG[9]
  PIN Tile_X2Y0_S1END[0]
    DIRECTION INPUT ;
    USE SIGNAL ;
    ANTENNAGATEAREA 1.033500 ;
    PORT
      LAYER Metal2 ;
        RECT 563.800 78.980 564.200 79.380 ;
    END
  END Tile_X2Y0_S1END[0]
  PIN Tile_X2Y0_S1END[1]
    DIRECTION INPUT ;
    USE SIGNAL ;
    ANTENNAGATEAREA 1.033500 ;
    PORT
      LAYER Metal2 ;
        RECT 565.720 78.980 566.120 79.380 ;
    END
  END Tile_X2Y0_S1END[1]
  PIN Tile_X2Y0_S1END[2]
    DIRECTION INPUT ;
    USE SIGNAL ;
    ANTENNAGATEAREA 1.033500 ;
    PORT
      LAYER Metal2 ;
        RECT 567.640 78.980 568.040 79.380 ;
    END
  END Tile_X2Y0_S1END[2]
  PIN Tile_X2Y0_S1END[3]
    DIRECTION INPUT ;
    USE SIGNAL ;
    ANTENNAGATEAREA 1.033500 ;
    PORT
      LAYER Metal2 ;
        RECT 569.560 78.980 569.960 79.380 ;
    END
  END Tile_X2Y0_S1END[3]
  PIN Tile_X2Y0_S2END[0]
    DIRECTION INPUT ;
    USE SIGNAL ;
    ANTENNAGATEAREA 0.852800 ;
    PORT
      LAYER Metal2 ;
        RECT 589.720 78.980 590.120 79.380 ;
    END
  END Tile_X2Y0_S2END[0]
  PIN Tile_X2Y0_S2END[1]
    DIRECTION INPUT ;
    USE SIGNAL ;
    ANTENNAGATEAREA 0.852800 ;
    PORT
      LAYER Metal2 ;
        RECT 590.680 78.980 591.080 79.380 ;
    END
  END Tile_X2Y0_S2END[1]
  PIN Tile_X2Y0_S2END[2]
    DIRECTION INPUT ;
    USE SIGNAL ;
    ANTENNAGATEAREA 0.852800 ;
    PORT
      LAYER Metal2 ;
        RECT 591.640 78.980 592.040 79.380 ;
    END
  END Tile_X2Y0_S2END[2]
  PIN Tile_X2Y0_S2END[3]
    DIRECTION INPUT ;
    USE SIGNAL ;
    ANTENNAGATEAREA 0.852800 ;
    PORT
      LAYER Metal2 ;
        RECT 592.600 78.980 593.000 79.380 ;
    END
  END Tile_X2Y0_S2END[3]
  PIN Tile_X2Y0_S2END[4]
    DIRECTION INPUT ;
    USE SIGNAL ;
    ANTENNAGATEAREA 0.852800 ;
    PORT
      LAYER Metal2 ;
        RECT 593.560 78.980 593.960 79.380 ;
    END
  END Tile_X2Y0_S2END[4]
  PIN Tile_X2Y0_S2END[5]
    DIRECTION INPUT ;
    USE SIGNAL ;
    ANTENNAGATEAREA 0.852800 ;
    PORT
      LAYER Metal2 ;
        RECT 594.520 78.980 594.920 79.380 ;
    END
  END Tile_X2Y0_S2END[5]
  PIN Tile_X2Y0_S2END[6]
    DIRECTION INPUT ;
    USE SIGNAL ;
    ANTENNAGATEAREA 0.852800 ;
    PORT
      LAYER Metal2 ;
        RECT 595.480 78.980 595.880 79.380 ;
    END
  END Tile_X2Y0_S2END[6]
  PIN Tile_X2Y0_S2END[7]
    DIRECTION INPUT ;
    USE SIGNAL ;
    ANTENNAGATEAREA 0.852800 ;
    PORT
      LAYER Metal2 ;
        RECT 596.440 78.980 596.840 79.380 ;
    END
  END Tile_X2Y0_S2END[7]
  PIN Tile_X2Y0_S2MID[0]
    DIRECTION INPUT ;
    USE SIGNAL ;
    ANTENNAGATEAREA 1.246700 ;
    PORT
      LAYER Metal2 ;
        RECT 571.480 78.980 571.880 79.380 ;
    END
  END Tile_X2Y0_S2MID[0]
  PIN Tile_X2Y0_S2MID[1]
    DIRECTION INPUT ;
    USE SIGNAL ;
    ANTENNAGATEAREA 1.246700 ;
    PORT
      LAYER Metal2 ;
        RECT 573.400 78.980 573.800 79.380 ;
    END
  END Tile_X2Y0_S2MID[1]
  PIN Tile_X2Y0_S2MID[2]
    DIRECTION INPUT ;
    USE SIGNAL ;
    ANTENNAGATEAREA 1.246700 ;
    PORT
      LAYER Metal2 ;
        RECT 575.320 78.980 575.720 79.380 ;
    END
  END Tile_X2Y0_S2MID[2]
  PIN Tile_X2Y0_S2MID[3]
    DIRECTION INPUT ;
    USE SIGNAL ;
    ANTENNAGATEAREA 1.246700 ;
    PORT
      LAYER Metal2 ;
        RECT 577.240 78.980 577.640 79.380 ;
    END
  END Tile_X2Y0_S2MID[3]
  PIN Tile_X2Y0_S2MID[4]
    DIRECTION INPUT ;
    USE SIGNAL ;
    ANTENNAGATEAREA 1.246700 ;
    PORT
      LAYER Metal2 ;
        RECT 579.160 78.980 579.560 79.380 ;
    END
  END Tile_X2Y0_S2MID[4]
  PIN Tile_X2Y0_S2MID[5]
    DIRECTION INPUT ;
    USE SIGNAL ;
    ANTENNAGATEAREA 1.246700 ;
    PORT
      LAYER Metal2 ;
        RECT 581.080 78.980 581.480 79.380 ;
    END
  END Tile_X2Y0_S2MID[5]
  PIN Tile_X2Y0_S2MID[6]
    DIRECTION INPUT ;
    USE SIGNAL ;
    ANTENNAGATEAREA 1.246700 ;
    PORT
      LAYER Metal2 ;
        RECT 583.000 78.980 583.400 79.380 ;
    END
  END Tile_X2Y0_S2MID[6]
  PIN Tile_X2Y0_S2MID[7]
    DIRECTION INPUT ;
    USE SIGNAL ;
    ANTENNAGATEAREA 1.246700 ;
    PORT
      LAYER Metal2 ;
        RECT 584.920 78.980 585.320 79.380 ;
    END
  END Tile_X2Y0_S2MID[7]
  PIN Tile_X2Y0_S4END[0]
    DIRECTION INPUT ;
    USE SIGNAL ;
    ANTENNAGATEAREA 0.426400 ;
    ANTENNADIFFAREA 8.061600 ;
    PORT
      LAYER Metal2 ;
        RECT 607.960 78.980 608.360 79.380 ;
    END
  END Tile_X2Y0_S4END[0]
  PIN Tile_X2Y0_S4END[10]
    DIRECTION INPUT ;
    USE SIGNAL ;
    ANTENNAGATEAREA 0.426400 ;
    PORT
      LAYER Metal2 ;
        RECT 617.560 78.980 617.960 79.380 ;
    END
  END Tile_X2Y0_S4END[10]
  PIN Tile_X2Y0_S4END[11]
    DIRECTION INPUT ;
    USE SIGNAL ;
    ANTENNAGATEAREA 0.426400 ;
    PORT
      LAYER Metal2 ;
        RECT 618.520 78.980 618.920 79.380 ;
    END
  END Tile_X2Y0_S4END[11]
  PIN Tile_X2Y0_S4END[12]
    DIRECTION INPUT ;
    USE SIGNAL ;
    ANTENNAGATEAREA 0.426400 ;
    PORT
      LAYER Metal2 ;
        RECT 619.480 78.980 619.880 79.380 ;
    END
  END Tile_X2Y0_S4END[12]
  PIN Tile_X2Y0_S4END[13]
    DIRECTION INPUT ;
    USE SIGNAL ;
    ANTENNAGATEAREA 0.426400 ;
    PORT
      LAYER Metal2 ;
        RECT 620.440 78.980 620.840 79.380 ;
    END
  END Tile_X2Y0_S4END[13]
  PIN Tile_X2Y0_S4END[14]
    DIRECTION INPUT ;
    USE SIGNAL ;
    ANTENNAGATEAREA 0.426400 ;
    PORT
      LAYER Metal2 ;
        RECT 621.400 78.980 621.800 79.380 ;
    END
  END Tile_X2Y0_S4END[14]
  PIN Tile_X2Y0_S4END[15]
    DIRECTION INPUT ;
    USE SIGNAL ;
    ANTENNAGATEAREA 0.426400 ;
    PORT
      LAYER Metal2 ;
        RECT 622.360 78.980 622.760 79.380 ;
    END
  END Tile_X2Y0_S4END[15]
  PIN Tile_X2Y0_S4END[1]
    DIRECTION INPUT ;
    USE SIGNAL ;
    ANTENNAGATEAREA 0.426400 ;
    PORT
      LAYER Metal2 ;
        RECT 608.920 78.980 609.320 79.380 ;
    END
  END Tile_X2Y0_S4END[1]
  PIN Tile_X2Y0_S4END[2]
    DIRECTION INPUT ;
    USE SIGNAL ;
    ANTENNAGATEAREA 0.426400 ;
    PORT
      LAYER Metal2 ;
        RECT 609.880 78.980 610.280 79.380 ;
    END
  END Tile_X2Y0_S4END[2]
  PIN Tile_X2Y0_S4END[3]
    DIRECTION INPUT ;
    USE SIGNAL ;
    ANTENNAGATEAREA 0.426400 ;
    PORT
      LAYER Metal2 ;
        RECT 610.840 78.980 611.240 79.380 ;
    END
  END Tile_X2Y0_S4END[3]
  PIN Tile_X2Y0_S4END[4]
    DIRECTION INPUT ;
    USE SIGNAL ;
    ANTENNAGATEAREA 0.426400 ;
    PORT
      LAYER Metal2 ;
        RECT 611.800 78.980 612.200 79.380 ;
    END
  END Tile_X2Y0_S4END[4]
  PIN Tile_X2Y0_S4END[5]
    DIRECTION INPUT ;
    USE SIGNAL ;
    ANTENNAGATEAREA 0.426400 ;
    PORT
      LAYER Metal2 ;
        RECT 612.760 78.980 613.160 79.380 ;
    END
  END Tile_X2Y0_S4END[5]
  PIN Tile_X2Y0_S4END[6]
    DIRECTION INPUT ;
    USE SIGNAL ;
    ANTENNAGATEAREA 0.426400 ;
    PORT
      LAYER Metal2 ;
        RECT 613.720 78.980 614.120 79.380 ;
    END
  END Tile_X2Y0_S4END[6]
  PIN Tile_X2Y0_S4END[7]
    DIRECTION INPUT ;
    USE SIGNAL ;
    ANTENNAGATEAREA 0.426400 ;
    PORT
      LAYER Metal2 ;
        RECT 614.680 78.980 615.080 79.380 ;
    END
  END Tile_X2Y0_S4END[7]
  PIN Tile_X2Y0_S4END[8]
    DIRECTION INPUT ;
    USE SIGNAL ;
    ANTENNAGATEAREA 0.426400 ;
    PORT
      LAYER Metal2 ;
        RECT 615.640 78.980 616.040 79.380 ;
    END
  END Tile_X2Y0_S4END[8]
  PIN Tile_X2Y0_S4END[9]
    DIRECTION INPUT ;
    USE SIGNAL ;
    ANTENNAGATEAREA 0.426400 ;
    PORT
      LAYER Metal2 ;
        RECT 616.600 78.980 617.000 79.380 ;
    END
  END Tile_X2Y0_S4END[9]
  PIN Tile_X2Y0_SS4END[0]
    DIRECTION INPUT ;
    USE SIGNAL ;
    ANTENNAGATEAREA 0.426400 ;
    PORT
      LAYER Metal2 ;
        RECT 637.720 78.980 638.120 79.380 ;
    END
  END Tile_X2Y0_SS4END[0]
  PIN Tile_X2Y0_SS4END[10]
    DIRECTION INPUT ;
    USE SIGNAL ;
    ANTENNAGATEAREA 0.426400 ;
    PORT
      LAYER Metal2 ;
        RECT 647.320 78.980 647.720 79.380 ;
    END
  END Tile_X2Y0_SS4END[10]
  PIN Tile_X2Y0_SS4END[11]
    DIRECTION INPUT ;
    USE SIGNAL ;
    ANTENNAGATEAREA 0.426400 ;
    PORT
      LAYER Metal2 ;
        RECT 648.280 78.980 648.680 79.380 ;
    END
  END Tile_X2Y0_SS4END[11]
  PIN Tile_X2Y0_SS4END[12]
    DIRECTION INPUT ;
    USE SIGNAL ;
    ANTENNAGATEAREA 0.426400 ;
    PORT
      LAYER Metal2 ;
        RECT 649.240 78.980 649.640 79.380 ;
    END
  END Tile_X2Y0_SS4END[12]
  PIN Tile_X2Y0_SS4END[13]
    DIRECTION INPUT ;
    USE SIGNAL ;
    ANTENNAGATEAREA 0.426400 ;
    PORT
      LAYER Metal2 ;
        RECT 650.200 78.980 650.600 79.380 ;
    END
  END Tile_X2Y0_SS4END[13]
  PIN Tile_X2Y0_SS4END[14]
    DIRECTION INPUT ;
    USE SIGNAL ;
    ANTENNAGATEAREA 0.426400 ;
    PORT
      LAYER Metal2 ;
        RECT 651.160 78.980 651.560 79.380 ;
    END
  END Tile_X2Y0_SS4END[14]
  PIN Tile_X2Y0_SS4END[15]
    DIRECTION INPUT ;
    USE SIGNAL ;
    ANTENNAGATEAREA 0.426400 ;
    ANTENNADIFFAREA 8.061600 ;
    PORT
      LAYER Metal2 ;
        RECT 652.120 78.980 652.520 79.380 ;
    END
  END Tile_X2Y0_SS4END[15]
  PIN Tile_X2Y0_SS4END[1]
    DIRECTION INPUT ;
    USE SIGNAL ;
    ANTENNAGATEAREA 0.426400 ;
    PORT
      LAYER Metal2 ;
        RECT 638.680 78.980 639.080 79.380 ;
    END
  END Tile_X2Y0_SS4END[1]
  PIN Tile_X2Y0_SS4END[2]
    DIRECTION INPUT ;
    USE SIGNAL ;
    ANTENNAGATEAREA 0.426400 ;
    PORT
      LAYER Metal2 ;
        RECT 639.640 78.980 640.040 79.380 ;
    END
  END Tile_X2Y0_SS4END[2]
  PIN Tile_X2Y0_SS4END[3]
    DIRECTION INPUT ;
    USE SIGNAL ;
    ANTENNAGATEAREA 0.426400 ;
    PORT
      LAYER Metal2 ;
        RECT 640.600 78.980 641.000 79.380 ;
    END
  END Tile_X2Y0_SS4END[3]
  PIN Tile_X2Y0_SS4END[4]
    DIRECTION INPUT ;
    USE SIGNAL ;
    ANTENNAGATEAREA 0.426400 ;
    PORT
      LAYER Metal2 ;
        RECT 641.560 78.980 641.960 79.380 ;
    END
  END Tile_X2Y0_SS4END[4]
  PIN Tile_X2Y0_SS4END[5]
    DIRECTION INPUT ;
    USE SIGNAL ;
    ANTENNAGATEAREA 0.426400 ;
    PORT
      LAYER Metal2 ;
        RECT 642.520 78.980 642.920 79.380 ;
    END
  END Tile_X2Y0_SS4END[5]
  PIN Tile_X2Y0_SS4END[6]
    DIRECTION INPUT ;
    USE SIGNAL ;
    ANTENNAGATEAREA 0.426400 ;
    PORT
      LAYER Metal2 ;
        RECT 643.480 78.980 643.880 79.380 ;
    END
  END Tile_X2Y0_SS4END[6]
  PIN Tile_X2Y0_SS4END[7]
    DIRECTION INPUT ;
    USE SIGNAL ;
    ANTENNAGATEAREA 0.426400 ;
    ANTENNADIFFAREA 8.061600 ;
    PORT
      LAYER Metal2 ;
        RECT 644.440 78.980 644.840 79.380 ;
    END
  END Tile_X2Y0_SS4END[7]
  PIN Tile_X2Y0_SS4END[8]
    DIRECTION INPUT ;
    USE SIGNAL ;
    ANTENNAGATEAREA 0.426400 ;
    PORT
      LAYER Metal2 ;
        RECT 645.400 78.980 645.800 79.380 ;
    END
  END Tile_X2Y0_SS4END[8]
  PIN Tile_X2Y0_SS4END[9]
    DIRECTION INPUT ;
    USE SIGNAL ;
    ANTENNAGATEAREA 0.426400 ;
    PORT
      LAYER Metal2 ;
        RECT 646.360 78.980 646.760 79.380 ;
    END
  END Tile_X2Y0_SS4END[9]
  PIN Tile_X3Y0_Co
    DIRECTION OUTPUT ;
    USE SIGNAL ;
    ANTENNADIFFAREA 2.314600 ;
    PORT
      LAYER Metal2 ;
        RECT 894.040 78.980 894.440 79.380 ;
    END
  END Tile_X3Y0_Co
  PIN Tile_X3Y0_FrameStrobe[0]
    DIRECTION INPUT ;
    USE SIGNAL ;
    ANTENNAGATEAREA 11.745500 ;
    PORT
      LAYER Metal2 ;
        RECT 706.840 0.000 707.240 0.400 ;
    END
  END Tile_X3Y0_FrameStrobe[0]
  PIN Tile_X3Y0_FrameStrobe[10]
    DIRECTION INPUT ;
    USE SIGNAL ;
    ANTENNAGATEAREA 0.180700 ;
    PORT
      LAYER Metal2 ;
        RECT 822.040 0.000 822.440 0.400 ;
    END
  END Tile_X3Y0_FrameStrobe[10]
  PIN Tile_X3Y0_FrameStrobe[11]
    DIRECTION INPUT ;
    USE SIGNAL ;
    ANTENNAGATEAREA 0.180700 ;
    PORT
      LAYER Metal2 ;
        RECT 833.560 0.000 833.960 0.400 ;
    END
  END Tile_X3Y0_FrameStrobe[11]
  PIN Tile_X3Y0_FrameStrobe[12]
    DIRECTION INPUT ;
    USE SIGNAL ;
    ANTENNAGATEAREA 0.180700 ;
    PORT
      LAYER Metal2 ;
        RECT 845.080 0.000 845.480 0.400 ;
    END
  END Tile_X3Y0_FrameStrobe[12]
  PIN Tile_X3Y0_FrameStrobe[13]
    DIRECTION INPUT ;
    USE SIGNAL ;
    ANTENNAGATEAREA 0.180700 ;
    PORT
      LAYER Metal2 ;
        RECT 856.600 0.000 857.000 0.400 ;
    END
  END Tile_X3Y0_FrameStrobe[13]
  PIN Tile_X3Y0_FrameStrobe[14]
    DIRECTION INPUT ;
    USE SIGNAL ;
    ANTENNAGATEAREA 0.180700 ;
    PORT
      LAYER Metal2 ;
        RECT 868.120 0.000 868.520 0.400 ;
    END
  END Tile_X3Y0_FrameStrobe[14]
  PIN Tile_X3Y0_FrameStrobe[15]
    DIRECTION INPUT ;
    USE SIGNAL ;
    ANTENNAGATEAREA 0.180700 ;
    PORT
      LAYER Metal2 ;
        RECT 879.640 0.000 880.040 0.400 ;
    END
  END Tile_X3Y0_FrameStrobe[15]
  PIN Tile_X3Y0_FrameStrobe[16]
    DIRECTION INPUT ;
    USE SIGNAL ;
    ANTENNAGATEAREA 0.180700 ;
    PORT
      LAYER Metal2 ;
        RECT 891.160 0.000 891.560 0.400 ;
    END
  END Tile_X3Y0_FrameStrobe[16]
  PIN Tile_X3Y0_FrameStrobe[17]
    DIRECTION INPUT ;
    USE SIGNAL ;
    ANTENNAGATEAREA 0.180700 ;
    PORT
      LAYER Metal2 ;
        RECT 902.680 0.000 903.080 0.400 ;
    END
  END Tile_X3Y0_FrameStrobe[17]
  PIN Tile_X3Y0_FrameStrobe[18]
    DIRECTION INPUT ;
    USE SIGNAL ;
    ANTENNAGATEAREA 0.180700 ;
    PORT
      LAYER Metal2 ;
        RECT 914.200 0.000 914.600 0.400 ;
    END
  END Tile_X3Y0_FrameStrobe[18]
  PIN Tile_X3Y0_FrameStrobe[19]
    DIRECTION INPUT ;
    USE SIGNAL ;
    ANTENNAGATEAREA 0.180700 ;
    PORT
      LAYER Metal2 ;
        RECT 925.720 0.000 926.120 0.400 ;
    END
  END Tile_X3Y0_FrameStrobe[19]
  PIN Tile_X3Y0_FrameStrobe[1]
    DIRECTION INPUT ;
    USE SIGNAL ;
    ANTENNAGATEAREA 11.745500 ;
    PORT
      LAYER Metal2 ;
        RECT 718.360 0.000 718.760 0.400 ;
    END
  END Tile_X3Y0_FrameStrobe[1]
  PIN Tile_X3Y0_FrameStrobe[2]
    DIRECTION INPUT ;
    USE SIGNAL ;
    ANTENNAGATEAREA 11.745500 ;
    PORT
      LAYER Metal2 ;
        RECT 729.880 0.000 730.280 0.400 ;
    END
  END Tile_X3Y0_FrameStrobe[2]
  PIN Tile_X3Y0_FrameStrobe[3]
    DIRECTION INPUT ;
    USE SIGNAL ;
    ANTENNAGATEAREA 0.180700 ;
    PORT
      LAYER Metal2 ;
        RECT 741.400 0.000 741.800 0.400 ;
    END
  END Tile_X3Y0_FrameStrobe[3]
  PIN Tile_X3Y0_FrameStrobe[4]
    DIRECTION INPUT ;
    USE SIGNAL ;
    ANTENNAGATEAREA 0.180700 ;
    PORT
      LAYER Metal2 ;
        RECT 752.920 0.000 753.320 0.400 ;
    END
  END Tile_X3Y0_FrameStrobe[4]
  PIN Tile_X3Y0_FrameStrobe[5]
    DIRECTION INPUT ;
    USE SIGNAL ;
    ANTENNAGATEAREA 0.180700 ;
    PORT
      LAYER Metal2 ;
        RECT 764.440 0.000 764.840 0.400 ;
    END
  END Tile_X3Y0_FrameStrobe[5]
  PIN Tile_X3Y0_FrameStrobe[6]
    DIRECTION INPUT ;
    USE SIGNAL ;
    ANTENNAGATEAREA 0.180700 ;
    PORT
      LAYER Metal2 ;
        RECT 775.960 0.000 776.360 0.400 ;
    END
  END Tile_X3Y0_FrameStrobe[6]
  PIN Tile_X3Y0_FrameStrobe[7]
    DIRECTION INPUT ;
    USE SIGNAL ;
    ANTENNAGATEAREA 0.180700 ;
    PORT
      LAYER Metal2 ;
        RECT 787.480 0.000 787.880 0.400 ;
    END
  END Tile_X3Y0_FrameStrobe[7]
  PIN Tile_X3Y0_FrameStrobe[8]
    DIRECTION INPUT ;
    USE SIGNAL ;
    ANTENNAGATEAREA 0.180700 ;
    PORT
      LAYER Metal2 ;
        RECT 799.000 0.000 799.400 0.400 ;
    END
  END Tile_X3Y0_FrameStrobe[8]
  PIN Tile_X3Y0_FrameStrobe[9]
    DIRECTION INPUT ;
    USE SIGNAL ;
    ANTENNAGATEAREA 0.180700 ;
    PORT
      LAYER Metal2 ;
        RECT 810.520 0.000 810.920 0.400 ;
    END
  END Tile_X3Y0_FrameStrobe[9]
  PIN Tile_X3Y0_FrameStrobe_O[0]
    DIRECTION OUTPUT ;
    USE SIGNAL ;
    ANTENNADIFFAREA 2.724000 ;
    PORT
      LAYER Metal2 ;
        RECT 904.600 78.980 905.000 79.380 ;
    END
  END Tile_X3Y0_FrameStrobe_O[0]
  PIN Tile_X3Y0_FrameStrobe_O[10]
    DIRECTION OUTPUT ;
    USE SIGNAL ;
    ANTENNADIFFAREA 2.724000 ;
    PORT
      LAYER Metal2 ;
        RECT 914.200 78.980 914.600 79.380 ;
    END
  END Tile_X3Y0_FrameStrobe_O[10]
  PIN Tile_X3Y0_FrameStrobe_O[11]
    DIRECTION OUTPUT ;
    USE SIGNAL ;
    ANTENNADIFFAREA 2.724000 ;
    PORT
      LAYER Metal2 ;
        RECT 915.160 78.980 915.560 79.380 ;
    END
  END Tile_X3Y0_FrameStrobe_O[11]
  PIN Tile_X3Y0_FrameStrobe_O[12]
    DIRECTION OUTPUT ;
    USE SIGNAL ;
    ANTENNADIFFAREA 2.724000 ;
    PORT
      LAYER Metal2 ;
        RECT 916.120 78.980 916.520 79.380 ;
    END
  END Tile_X3Y0_FrameStrobe_O[12]
  PIN Tile_X3Y0_FrameStrobe_O[13]
    DIRECTION OUTPUT ;
    USE SIGNAL ;
    ANTENNADIFFAREA 2.724000 ;
    PORT
      LAYER Metal2 ;
        RECT 917.080 78.980 917.480 79.380 ;
    END
  END Tile_X3Y0_FrameStrobe_O[13]
  PIN Tile_X3Y0_FrameStrobe_O[14]
    DIRECTION OUTPUT ;
    USE SIGNAL ;
    ANTENNADIFFAREA 2.724000 ;
    PORT
      LAYER Metal2 ;
        RECT 918.040 78.980 918.440 79.380 ;
    END
  END Tile_X3Y0_FrameStrobe_O[14]
  PIN Tile_X3Y0_FrameStrobe_O[15]
    DIRECTION OUTPUT ;
    USE SIGNAL ;
    ANTENNADIFFAREA 2.724000 ;
    PORT
      LAYER Metal2 ;
        RECT 919.000 78.980 919.400 79.380 ;
    END
  END Tile_X3Y0_FrameStrobe_O[15]
  PIN Tile_X3Y0_FrameStrobe_O[16]
    DIRECTION OUTPUT ;
    USE SIGNAL ;
    ANTENNADIFFAREA 2.724000 ;
    PORT
      LAYER Metal2 ;
        RECT 919.960 78.980 920.360 79.380 ;
    END
  END Tile_X3Y0_FrameStrobe_O[16]
  PIN Tile_X3Y0_FrameStrobe_O[17]
    DIRECTION OUTPUT ;
    USE SIGNAL ;
    ANTENNADIFFAREA 2.724000 ;
    PORT
      LAYER Metal2 ;
        RECT 920.920 78.980 921.320 79.380 ;
    END
  END Tile_X3Y0_FrameStrobe_O[17]
  PIN Tile_X3Y0_FrameStrobe_O[18]
    DIRECTION OUTPUT ;
    USE SIGNAL ;
    ANTENNADIFFAREA 2.724000 ;
    PORT
      LAYER Metal2 ;
        RECT 921.880 78.980 922.280 79.380 ;
    END
  END Tile_X3Y0_FrameStrobe_O[18]
  PIN Tile_X3Y0_FrameStrobe_O[19]
    DIRECTION OUTPUT ;
    USE SIGNAL ;
    ANTENNADIFFAREA 2.724000 ;
    PORT
      LAYER Metal2 ;
        RECT 922.840 78.980 923.240 79.380 ;
    END
  END Tile_X3Y0_FrameStrobe_O[19]
  PIN Tile_X3Y0_FrameStrobe_O[1]
    DIRECTION OUTPUT ;
    USE SIGNAL ;
    ANTENNADIFFAREA 2.724000 ;
    PORT
      LAYER Metal2 ;
        RECT 905.560 78.980 905.960 79.380 ;
    END
  END Tile_X3Y0_FrameStrobe_O[1]
  PIN Tile_X3Y0_FrameStrobe_O[2]
    DIRECTION OUTPUT ;
    USE SIGNAL ;
    ANTENNADIFFAREA 2.724000 ;
    PORT
      LAYER Metal2 ;
        RECT 906.520 78.980 906.920 79.380 ;
    END
  END Tile_X3Y0_FrameStrobe_O[2]
  PIN Tile_X3Y0_FrameStrobe_O[3]
    DIRECTION OUTPUT ;
    USE SIGNAL ;
    ANTENNADIFFAREA 2.724000 ;
    PORT
      LAYER Metal2 ;
        RECT 907.480 78.980 907.880 79.380 ;
    END
  END Tile_X3Y0_FrameStrobe_O[3]
  PIN Tile_X3Y0_FrameStrobe_O[4]
    DIRECTION OUTPUT ;
    USE SIGNAL ;
    ANTENNADIFFAREA 2.724000 ;
    PORT
      LAYER Metal2 ;
        RECT 908.440 78.980 908.840 79.380 ;
    END
  END Tile_X3Y0_FrameStrobe_O[4]
  PIN Tile_X3Y0_FrameStrobe_O[5]
    DIRECTION OUTPUT ;
    USE SIGNAL ;
    ANTENNADIFFAREA 2.724000 ;
    PORT
      LAYER Metal2 ;
        RECT 909.400 78.980 909.800 79.380 ;
    END
  END Tile_X3Y0_FrameStrobe_O[5]
  PIN Tile_X3Y0_FrameStrobe_O[6]
    DIRECTION OUTPUT ;
    USE SIGNAL ;
    ANTENNADIFFAREA 2.724000 ;
    PORT
      LAYER Metal2 ;
        RECT 910.360 78.980 910.760 79.380 ;
    END
  END Tile_X3Y0_FrameStrobe_O[6]
  PIN Tile_X3Y0_FrameStrobe_O[7]
    DIRECTION OUTPUT ;
    USE SIGNAL ;
    ANTENNADIFFAREA 2.724000 ;
    PORT
      LAYER Metal2 ;
        RECT 911.320 78.980 911.720 79.380 ;
    END
  END Tile_X3Y0_FrameStrobe_O[7]
  PIN Tile_X3Y0_FrameStrobe_O[8]
    DIRECTION OUTPUT ;
    USE SIGNAL ;
    ANTENNADIFFAREA 2.724000 ;
    PORT
      LAYER Metal2 ;
        RECT 912.280 78.980 912.680 79.380 ;
    END
  END Tile_X3Y0_FrameStrobe_O[8]
  PIN Tile_X3Y0_FrameStrobe_O[9]
    DIRECTION OUTPUT ;
    USE SIGNAL ;
    ANTENNADIFFAREA 2.724000 ;
    PORT
      LAYER Metal2 ;
        RECT 913.240 78.980 913.640 79.380 ;
    END
  END Tile_X3Y0_FrameStrobe_O[9]
  PIN Tile_X3Y0_N1BEG[0]
    DIRECTION OUTPUT ;
    USE SIGNAL ;
    ANTENNADIFFAREA 2.724000 ;
    PORT
      LAYER Metal2 ;
        RECT 701.080 78.980 701.480 79.380 ;
    END
  END Tile_X3Y0_N1BEG[0]
  PIN Tile_X3Y0_N1BEG[1]
    DIRECTION OUTPUT ;
    USE SIGNAL ;
    ANTENNADIFFAREA 2.724000 ;
    PORT
      LAYER Metal2 ;
        RECT 703.000 78.980 703.400 79.380 ;
    END
  END Tile_X3Y0_N1BEG[1]
  PIN Tile_X3Y0_N1BEG[2]
    DIRECTION OUTPUT ;
    USE SIGNAL ;
    ANTENNADIFFAREA 2.724000 ;
    PORT
      LAYER Metal2 ;
        RECT 704.920 78.980 705.320 79.380 ;
    END
  END Tile_X3Y0_N1BEG[2]
  PIN Tile_X3Y0_N1BEG[3]
    DIRECTION OUTPUT ;
    USE SIGNAL ;
    ANTENNADIFFAREA 2.724000 ;
    PORT
      LAYER Metal2 ;
        RECT 706.840 78.980 707.240 79.380 ;
    END
  END Tile_X3Y0_N1BEG[3]
  PIN Tile_X3Y0_N2BEG[0]
    DIRECTION OUTPUT ;
    USE SIGNAL ;
    ANTENNADIFFAREA 2.724000 ;
    PORT
      LAYER Metal2 ;
        RECT 711.640 78.980 712.040 79.380 ;
    END
  END Tile_X3Y0_N2BEG[0]
  PIN Tile_X3Y0_N2BEG[1]
    DIRECTION OUTPUT ;
    USE SIGNAL ;
    ANTENNADIFFAREA 2.724000 ;
    PORT
      LAYER Metal2 ;
        RECT 712.600 78.980 713.000 79.380 ;
    END
  END Tile_X3Y0_N2BEG[1]
  PIN Tile_X3Y0_N2BEG[2]
    DIRECTION OUTPUT ;
    USE SIGNAL ;
    ANTENNADIFFAREA 2.724000 ;
    PORT
      LAYER Metal2 ;
        RECT 713.560 78.980 713.960 79.380 ;
    END
  END Tile_X3Y0_N2BEG[2]
  PIN Tile_X3Y0_N2BEG[3]
    DIRECTION OUTPUT ;
    USE SIGNAL ;
    ANTENNADIFFAREA 2.724000 ;
    PORT
      LAYER Metal2 ;
        RECT 714.520 78.980 714.920 79.380 ;
    END
  END Tile_X3Y0_N2BEG[3]
  PIN Tile_X3Y0_N2BEG[4]
    DIRECTION OUTPUT ;
    USE SIGNAL ;
    ANTENNADIFFAREA 2.724000 ;
    PORT
      LAYER Metal2 ;
        RECT 715.480 78.980 715.880 79.380 ;
    END
  END Tile_X3Y0_N2BEG[4]
  PIN Tile_X3Y0_N2BEG[5]
    DIRECTION OUTPUT ;
    USE SIGNAL ;
    ANTENNADIFFAREA 2.724000 ;
    PORT
      LAYER Metal2 ;
        RECT 716.440 78.980 716.840 79.380 ;
    END
  END Tile_X3Y0_N2BEG[5]
  PIN Tile_X3Y0_N2BEG[6]
    DIRECTION OUTPUT ;
    USE SIGNAL ;
    ANTENNADIFFAREA 2.724000 ;
    PORT
      LAYER Metal2 ;
        RECT 717.400 78.980 717.800 79.380 ;
    END
  END Tile_X3Y0_N2BEG[6]
  PIN Tile_X3Y0_N2BEG[7]
    DIRECTION OUTPUT ;
    USE SIGNAL ;
    ANTENNADIFFAREA 2.724000 ;
    PORT
      LAYER Metal2 ;
        RECT 718.360 78.980 718.760 79.380 ;
    END
  END Tile_X3Y0_N2BEG[7]
  PIN Tile_X3Y0_N2BEGb[0]
    DIRECTION OUTPUT ;
    USE SIGNAL ;
    ANTENNADIFFAREA 2.724000 ;
    PORT
      LAYER Metal2 ;
        RECT 726.040 78.980 726.440 79.380 ;
    END
  END Tile_X3Y0_N2BEGb[0]
  PIN Tile_X3Y0_N2BEGb[1]
    DIRECTION OUTPUT ;
    USE SIGNAL ;
    ANTENNADIFFAREA 2.724000 ;
    PORT
      LAYER Metal2 ;
        RECT 727.000 78.980 727.400 79.380 ;
    END
  END Tile_X3Y0_N2BEGb[1]
  PIN Tile_X3Y0_N2BEGb[2]
    DIRECTION OUTPUT ;
    USE SIGNAL ;
    ANTENNADIFFAREA 2.724000 ;
    PORT
      LAYER Metal2 ;
        RECT 727.960 78.980 728.360 79.380 ;
    END
  END Tile_X3Y0_N2BEGb[2]
  PIN Tile_X3Y0_N2BEGb[3]
    DIRECTION OUTPUT ;
    USE SIGNAL ;
    ANTENNADIFFAREA 2.724000 ;
    PORT
      LAYER Metal2 ;
        RECT 728.920 78.980 729.320 79.380 ;
    END
  END Tile_X3Y0_N2BEGb[3]
  PIN Tile_X3Y0_N2BEGb[4]
    DIRECTION OUTPUT ;
    USE SIGNAL ;
    ANTENNADIFFAREA 2.724000 ;
    PORT
      LAYER Metal2 ;
        RECT 729.880 78.980 730.280 79.380 ;
    END
  END Tile_X3Y0_N2BEGb[4]
  PIN Tile_X3Y0_N2BEGb[5]
    DIRECTION OUTPUT ;
    USE SIGNAL ;
    ANTENNADIFFAREA 2.724000 ;
    PORT
      LAYER Metal2 ;
        RECT 730.840 78.980 731.240 79.380 ;
    END
  END Tile_X3Y0_N2BEGb[5]
  PIN Tile_X3Y0_N2BEGb[6]
    DIRECTION OUTPUT ;
    USE SIGNAL ;
    ANTENNADIFFAREA 2.724000 ;
    PORT
      LAYER Metal2 ;
        RECT 731.800 78.980 732.200 79.380 ;
    END
  END Tile_X3Y0_N2BEGb[6]
  PIN Tile_X3Y0_N2BEGb[7]
    DIRECTION OUTPUT ;
    USE SIGNAL ;
    ANTENNADIFFAREA 2.724000 ;
    PORT
      LAYER Metal2 ;
        RECT 732.760 78.980 733.160 79.380 ;
    END
  END Tile_X3Y0_N2BEGb[7]
  PIN Tile_X3Y0_N4BEG[0]
    DIRECTION OUTPUT ;
    USE SIGNAL ;
    ANTENNADIFFAREA 2.724000 ;
    PORT
      LAYER Metal2 ;
        RECT 744.280 78.980 744.680 79.380 ;
    END
  END Tile_X3Y0_N4BEG[0]
  PIN Tile_X3Y0_N4BEG[10]
    DIRECTION OUTPUT ;
    USE SIGNAL ;
    ANTENNADIFFAREA 2.724000 ;
    PORT
      LAYER Metal2 ;
        RECT 753.880 78.980 754.280 79.380 ;
    END
  END Tile_X3Y0_N4BEG[10]
  PIN Tile_X3Y0_N4BEG[11]
    DIRECTION OUTPUT ;
    USE SIGNAL ;
    ANTENNADIFFAREA 2.724000 ;
    PORT
      LAYER Metal2 ;
        RECT 754.840 78.980 755.240 79.380 ;
    END
  END Tile_X3Y0_N4BEG[11]
  PIN Tile_X3Y0_N4BEG[12]
    DIRECTION OUTPUT ;
    USE SIGNAL ;
    ANTENNADIFFAREA 2.724000 ;
    PORT
      LAYER Metal2 ;
        RECT 755.800 78.980 756.200 79.380 ;
    END
  END Tile_X3Y0_N4BEG[12]
  PIN Tile_X3Y0_N4BEG[13]
    DIRECTION OUTPUT ;
    USE SIGNAL ;
    ANTENNADIFFAREA 2.724000 ;
    PORT
      LAYER Metal2 ;
        RECT 756.760 78.980 757.160 79.380 ;
    END
  END Tile_X3Y0_N4BEG[13]
  PIN Tile_X3Y0_N4BEG[14]
    DIRECTION OUTPUT ;
    USE SIGNAL ;
    ANTENNADIFFAREA 2.724000 ;
    PORT
      LAYER Metal2 ;
        RECT 757.720 78.980 758.120 79.380 ;
    END
  END Tile_X3Y0_N4BEG[14]
  PIN Tile_X3Y0_N4BEG[15]
    DIRECTION OUTPUT ;
    USE SIGNAL ;
    ANTENNADIFFAREA 2.724000 ;
    PORT
      LAYER Metal2 ;
        RECT 758.680 78.980 759.080 79.380 ;
    END
  END Tile_X3Y0_N4BEG[15]
  PIN Tile_X3Y0_N4BEG[1]
    DIRECTION OUTPUT ;
    USE SIGNAL ;
    ANTENNADIFFAREA 2.724000 ;
    PORT
      LAYER Metal2 ;
        RECT 745.240 78.980 745.640 79.380 ;
    END
  END Tile_X3Y0_N4BEG[1]
  PIN Tile_X3Y0_N4BEG[2]
    DIRECTION OUTPUT ;
    USE SIGNAL ;
    ANTENNADIFFAREA 2.724000 ;
    PORT
      LAYER Metal2 ;
        RECT 746.200 78.980 746.600 79.380 ;
    END
  END Tile_X3Y0_N4BEG[2]
  PIN Tile_X3Y0_N4BEG[3]
    DIRECTION OUTPUT ;
    USE SIGNAL ;
    ANTENNADIFFAREA 2.724000 ;
    PORT
      LAYER Metal2 ;
        RECT 747.160 78.980 747.560 79.380 ;
    END
  END Tile_X3Y0_N4BEG[3]
  PIN Tile_X3Y0_N4BEG[4]
    DIRECTION OUTPUT ;
    USE SIGNAL ;
    ANTENNADIFFAREA 2.724000 ;
    PORT
      LAYER Metal2 ;
        RECT 748.120 78.980 748.520 79.380 ;
    END
  END Tile_X3Y0_N4BEG[4]
  PIN Tile_X3Y0_N4BEG[5]
    DIRECTION OUTPUT ;
    USE SIGNAL ;
    ANTENNADIFFAREA 2.724000 ;
    PORT
      LAYER Metal2 ;
        RECT 749.080 78.980 749.480 79.380 ;
    END
  END Tile_X3Y0_N4BEG[5]
  PIN Tile_X3Y0_N4BEG[6]
    DIRECTION OUTPUT ;
    USE SIGNAL ;
    ANTENNADIFFAREA 2.724000 ;
    PORT
      LAYER Metal2 ;
        RECT 750.040 78.980 750.440 79.380 ;
    END
  END Tile_X3Y0_N4BEG[6]
  PIN Tile_X3Y0_N4BEG[7]
    DIRECTION OUTPUT ;
    USE SIGNAL ;
    ANTENNADIFFAREA 2.724000 ;
    PORT
      LAYER Metal2 ;
        RECT 751.000 78.980 751.400 79.380 ;
    END
  END Tile_X3Y0_N4BEG[7]
  PIN Tile_X3Y0_N4BEG[8]
    DIRECTION OUTPUT ;
    USE SIGNAL ;
    ANTENNADIFFAREA 2.724000 ;
    PORT
      LAYER Metal2 ;
        RECT 751.960 78.980 752.360 79.380 ;
    END
  END Tile_X3Y0_N4BEG[8]
  PIN Tile_X3Y0_N4BEG[9]
    DIRECTION OUTPUT ;
    USE SIGNAL ;
    ANTENNADIFFAREA 2.724000 ;
    PORT
      LAYER Metal2 ;
        RECT 752.920 78.980 753.320 79.380 ;
    END
  END Tile_X3Y0_N4BEG[9]
  PIN Tile_X3Y0_NN4BEG[0]
    DIRECTION OUTPUT ;
    USE SIGNAL ;
    ANTENNADIFFAREA 2.724000 ;
    PORT
      LAYER Metal2 ;
        RECT 774.040 78.980 774.440 79.380 ;
    END
  END Tile_X3Y0_NN4BEG[0]
  PIN Tile_X3Y0_NN4BEG[10]
    DIRECTION OUTPUT ;
    USE SIGNAL ;
    ANTENNADIFFAREA 2.724000 ;
    PORT
      LAYER Metal2 ;
        RECT 783.640 78.980 784.040 79.380 ;
    END
  END Tile_X3Y0_NN4BEG[10]
  PIN Tile_X3Y0_NN4BEG[11]
    DIRECTION OUTPUT ;
    USE SIGNAL ;
    ANTENNADIFFAREA 2.724000 ;
    PORT
      LAYER Metal2 ;
        RECT 784.600 78.980 785.000 79.380 ;
    END
  END Tile_X3Y0_NN4BEG[11]
  PIN Tile_X3Y0_NN4BEG[12]
    DIRECTION OUTPUT ;
    USE SIGNAL ;
    ANTENNADIFFAREA 2.724000 ;
    PORT
      LAYER Metal2 ;
        RECT 785.560 78.980 785.960 79.380 ;
    END
  END Tile_X3Y0_NN4BEG[12]
  PIN Tile_X3Y0_NN4BEG[13]
    DIRECTION OUTPUT ;
    USE SIGNAL ;
    ANTENNADIFFAREA 2.724000 ;
    PORT
      LAYER Metal2 ;
        RECT 786.520 78.980 786.920 79.380 ;
    END
  END Tile_X3Y0_NN4BEG[13]
  PIN Tile_X3Y0_NN4BEG[14]
    DIRECTION OUTPUT ;
    USE SIGNAL ;
    ANTENNADIFFAREA 2.724000 ;
    PORT
      LAYER Metal2 ;
        RECT 787.480 78.980 787.880 79.380 ;
    END
  END Tile_X3Y0_NN4BEG[14]
  PIN Tile_X3Y0_NN4BEG[15]
    DIRECTION OUTPUT ;
    USE SIGNAL ;
    ANTENNADIFFAREA 2.724000 ;
    PORT
      LAYER Metal2 ;
        RECT 788.440 78.980 788.840 79.380 ;
    END
  END Tile_X3Y0_NN4BEG[15]
  PIN Tile_X3Y0_NN4BEG[1]
    DIRECTION OUTPUT ;
    USE SIGNAL ;
    ANTENNADIFFAREA 2.724000 ;
    PORT
      LAYER Metal2 ;
        RECT 775.000 78.980 775.400 79.380 ;
    END
  END Tile_X3Y0_NN4BEG[1]
  PIN Tile_X3Y0_NN4BEG[2]
    DIRECTION OUTPUT ;
    USE SIGNAL ;
    ANTENNADIFFAREA 2.724000 ;
    PORT
      LAYER Metal2 ;
        RECT 775.960 78.980 776.360 79.380 ;
    END
  END Tile_X3Y0_NN4BEG[2]
  PIN Tile_X3Y0_NN4BEG[3]
    DIRECTION OUTPUT ;
    USE SIGNAL ;
    ANTENNADIFFAREA 2.724000 ;
    PORT
      LAYER Metal2 ;
        RECT 776.920 78.980 777.320 79.380 ;
    END
  END Tile_X3Y0_NN4BEG[3]
  PIN Tile_X3Y0_NN4BEG[4]
    DIRECTION OUTPUT ;
    USE SIGNAL ;
    ANTENNADIFFAREA 2.724000 ;
    PORT
      LAYER Metal2 ;
        RECT 777.880 78.980 778.280 79.380 ;
    END
  END Tile_X3Y0_NN4BEG[4]
  PIN Tile_X3Y0_NN4BEG[5]
    DIRECTION OUTPUT ;
    USE SIGNAL ;
    ANTENNADIFFAREA 2.724000 ;
    PORT
      LAYER Metal2 ;
        RECT 778.840 78.980 779.240 79.380 ;
    END
  END Tile_X3Y0_NN4BEG[5]
  PIN Tile_X3Y0_NN4BEG[6]
    DIRECTION OUTPUT ;
    USE SIGNAL ;
    ANTENNADIFFAREA 2.724000 ;
    PORT
      LAYER Metal2 ;
        RECT 779.800 78.980 780.200 79.380 ;
    END
  END Tile_X3Y0_NN4BEG[6]
  PIN Tile_X3Y0_NN4BEG[7]
    DIRECTION OUTPUT ;
    USE SIGNAL ;
    ANTENNADIFFAREA 2.724000 ;
    PORT
      LAYER Metal2 ;
        RECT 780.760 78.980 781.160 79.380 ;
    END
  END Tile_X3Y0_NN4BEG[7]
  PIN Tile_X3Y0_NN4BEG[8]
    DIRECTION OUTPUT ;
    USE SIGNAL ;
    ANTENNADIFFAREA 2.724000 ;
    PORT
      LAYER Metal2 ;
        RECT 781.720 78.980 782.120 79.380 ;
    END
  END Tile_X3Y0_NN4BEG[8]
  PIN Tile_X3Y0_NN4BEG[9]
    DIRECTION OUTPUT ;
    USE SIGNAL ;
    ANTENNADIFFAREA 2.724000 ;
    PORT
      LAYER Metal2 ;
        RECT 782.680 78.980 783.080 79.380 ;
    END
  END Tile_X3Y0_NN4BEG[9]
  PIN Tile_X3Y0_S1END[0]
    DIRECTION INPUT ;
    USE SIGNAL ;
    ANTENNAGATEAREA 1.033500 ;
    PORT
      LAYER Metal2 ;
        RECT 797.080 78.980 797.480 79.380 ;
    END
  END Tile_X3Y0_S1END[0]
  PIN Tile_X3Y0_S1END[1]
    DIRECTION INPUT ;
    USE SIGNAL ;
    ANTENNAGATEAREA 1.033500 ;
    PORT
      LAYER Metal2 ;
        RECT 799.000 78.980 799.400 79.380 ;
    END
  END Tile_X3Y0_S1END[1]
  PIN Tile_X3Y0_S1END[2]
    DIRECTION INPUT ;
    USE SIGNAL ;
    ANTENNAGATEAREA 1.033500 ;
    PORT
      LAYER Metal2 ;
        RECT 800.920 78.980 801.320 79.380 ;
    END
  END Tile_X3Y0_S1END[2]
  PIN Tile_X3Y0_S1END[3]
    DIRECTION INPUT ;
    USE SIGNAL ;
    ANTENNAGATEAREA 1.033500 ;
    PORT
      LAYER Metal2 ;
        RECT 802.840 78.980 803.240 79.380 ;
    END
  END Tile_X3Y0_S1END[3]
  PIN Tile_X3Y0_S2END[0]
    DIRECTION INPUT ;
    USE SIGNAL ;
    ANTENNAGATEAREA 0.852800 ;
    PORT
      LAYER Metal2 ;
        RECT 823.000 78.980 823.400 79.380 ;
    END
  END Tile_X3Y0_S2END[0]
  PIN Tile_X3Y0_S2END[1]
    DIRECTION INPUT ;
    USE SIGNAL ;
    ANTENNAGATEAREA 0.852800 ;
    PORT
      LAYER Metal2 ;
        RECT 823.960 78.980 824.360 79.380 ;
    END
  END Tile_X3Y0_S2END[1]
  PIN Tile_X3Y0_S2END[2]
    DIRECTION INPUT ;
    USE SIGNAL ;
    ANTENNAGATEAREA 0.852800 ;
    PORT
      LAYER Metal2 ;
        RECT 824.920 78.980 825.320 79.380 ;
    END
  END Tile_X3Y0_S2END[2]
  PIN Tile_X3Y0_S2END[3]
    DIRECTION INPUT ;
    USE SIGNAL ;
    ANTENNAGATEAREA 0.852800 ;
    PORT
      LAYER Metal2 ;
        RECT 825.880 78.980 826.280 79.380 ;
    END
  END Tile_X3Y0_S2END[3]
  PIN Tile_X3Y0_S2END[4]
    DIRECTION INPUT ;
    USE SIGNAL ;
    ANTENNAGATEAREA 0.852800 ;
    PORT
      LAYER Metal2 ;
        RECT 826.840 78.980 827.240 79.380 ;
    END
  END Tile_X3Y0_S2END[4]
  PIN Tile_X3Y0_S2END[5]
    DIRECTION INPUT ;
    USE SIGNAL ;
    ANTENNAGATEAREA 0.852800 ;
    PORT
      LAYER Metal2 ;
        RECT 827.800 78.980 828.200 79.380 ;
    END
  END Tile_X3Y0_S2END[5]
  PIN Tile_X3Y0_S2END[6]
    DIRECTION INPUT ;
    USE SIGNAL ;
    ANTENNAGATEAREA 0.852800 ;
    PORT
      LAYER Metal2 ;
        RECT 828.760 78.980 829.160 79.380 ;
    END
  END Tile_X3Y0_S2END[6]
  PIN Tile_X3Y0_S2END[7]
    DIRECTION INPUT ;
    USE SIGNAL ;
    ANTENNAGATEAREA 0.852800 ;
    PORT
      LAYER Metal2 ;
        RECT 829.720 78.980 830.120 79.380 ;
    END
  END Tile_X3Y0_S2END[7]
  PIN Tile_X3Y0_S2MID[0]
    DIRECTION INPUT ;
    USE SIGNAL ;
    ANTENNAGATEAREA 1.246700 ;
    PORT
      LAYER Metal2 ;
        RECT 804.760 78.980 805.160 79.380 ;
    END
  END Tile_X3Y0_S2MID[0]
  PIN Tile_X3Y0_S2MID[1]
    DIRECTION INPUT ;
    USE SIGNAL ;
    ANTENNAGATEAREA 1.246700 ;
    PORT
      LAYER Metal2 ;
        RECT 806.680 78.980 807.080 79.380 ;
    END
  END Tile_X3Y0_S2MID[1]
  PIN Tile_X3Y0_S2MID[2]
    DIRECTION INPUT ;
    USE SIGNAL ;
    ANTENNAGATEAREA 1.246700 ;
    PORT
      LAYER Metal2 ;
        RECT 808.600 78.980 809.000 79.380 ;
    END
  END Tile_X3Y0_S2MID[2]
  PIN Tile_X3Y0_S2MID[3]
    DIRECTION INPUT ;
    USE SIGNAL ;
    ANTENNAGATEAREA 1.246700 ;
    PORT
      LAYER Metal2 ;
        RECT 810.520 78.980 810.920 79.380 ;
    END
  END Tile_X3Y0_S2MID[3]
  PIN Tile_X3Y0_S2MID[4]
    DIRECTION INPUT ;
    USE SIGNAL ;
    ANTENNAGATEAREA 1.246700 ;
    PORT
      LAYER Metal2 ;
        RECT 812.440 78.980 812.840 79.380 ;
    END
  END Tile_X3Y0_S2MID[4]
  PIN Tile_X3Y0_S2MID[5]
    DIRECTION INPUT ;
    USE SIGNAL ;
    ANTENNAGATEAREA 1.246700 ;
    PORT
      LAYER Metal2 ;
        RECT 814.360 78.980 814.760 79.380 ;
    END
  END Tile_X3Y0_S2MID[5]
  PIN Tile_X3Y0_S2MID[6]
    DIRECTION INPUT ;
    USE SIGNAL ;
    ANTENNAGATEAREA 1.246700 ;
    PORT
      LAYER Metal2 ;
        RECT 816.280 78.980 816.680 79.380 ;
    END
  END Tile_X3Y0_S2MID[6]
  PIN Tile_X3Y0_S2MID[7]
    DIRECTION INPUT ;
    USE SIGNAL ;
    ANTENNAGATEAREA 1.246700 ;
    PORT
      LAYER Metal2 ;
        RECT 818.200 78.980 818.600 79.380 ;
    END
  END Tile_X3Y0_S2MID[7]
  PIN Tile_X3Y0_S4END[0]
    DIRECTION INPUT ;
    USE SIGNAL ;
    ANTENNAGATEAREA 0.426400 ;
    PORT
      LAYER Metal2 ;
        RECT 841.240 78.980 841.640 79.380 ;
    END
  END Tile_X3Y0_S4END[0]
  PIN Tile_X3Y0_S4END[10]
    DIRECTION INPUT ;
    USE SIGNAL ;
    ANTENNAGATEAREA 0.426400 ;
    PORT
      LAYER Metal2 ;
        RECT 850.840 78.980 851.240 79.380 ;
    END
  END Tile_X3Y0_S4END[10]
  PIN Tile_X3Y0_S4END[11]
    DIRECTION INPUT ;
    USE SIGNAL ;
    ANTENNAGATEAREA 0.426400 ;
    PORT
      LAYER Metal2 ;
        RECT 851.800 78.980 852.200 79.380 ;
    END
  END Tile_X3Y0_S4END[11]
  PIN Tile_X3Y0_S4END[12]
    DIRECTION INPUT ;
    USE SIGNAL ;
    ANTENNAGATEAREA 0.426400 ;
    PORT
      LAYER Metal2 ;
        RECT 852.760 78.980 853.160 79.380 ;
    END
  END Tile_X3Y0_S4END[12]
  PIN Tile_X3Y0_S4END[13]
    DIRECTION INPUT ;
    USE SIGNAL ;
    ANTENNAGATEAREA 0.426400 ;
    PORT
      LAYER Metal2 ;
        RECT 853.720 78.980 854.120 79.380 ;
    END
  END Tile_X3Y0_S4END[13]
  PIN Tile_X3Y0_S4END[14]
    DIRECTION INPUT ;
    USE SIGNAL ;
    ANTENNAGATEAREA 0.426400 ;
    PORT
      LAYER Metal2 ;
        RECT 854.680 78.980 855.080 79.380 ;
    END
  END Tile_X3Y0_S4END[14]
  PIN Tile_X3Y0_S4END[15]
    DIRECTION INPUT ;
    USE SIGNAL ;
    ANTENNAGATEAREA 0.426400 ;
    PORT
      LAYER Metal2 ;
        RECT 855.640 78.980 856.040 79.380 ;
    END
  END Tile_X3Y0_S4END[15]
  PIN Tile_X3Y0_S4END[1]
    DIRECTION INPUT ;
    USE SIGNAL ;
    ANTENNAGATEAREA 0.426400 ;
    PORT
      LAYER Metal2 ;
        RECT 842.200 78.980 842.600 79.380 ;
    END
  END Tile_X3Y0_S4END[1]
  PIN Tile_X3Y0_S4END[2]
    DIRECTION INPUT ;
    USE SIGNAL ;
    ANTENNAGATEAREA 0.426400 ;
    PORT
      LAYER Metal2 ;
        RECT 843.160 78.980 843.560 79.380 ;
    END
  END Tile_X3Y0_S4END[2]
  PIN Tile_X3Y0_S4END[3]
    DIRECTION INPUT ;
    USE SIGNAL ;
    ANTENNAGATEAREA 0.426400 ;
    PORT
      LAYER Metal2 ;
        RECT 844.120 78.980 844.520 79.380 ;
    END
  END Tile_X3Y0_S4END[3]
  PIN Tile_X3Y0_S4END[4]
    DIRECTION INPUT ;
    USE SIGNAL ;
    ANTENNAGATEAREA 0.426400 ;
    PORT
      LAYER Metal2 ;
        RECT 845.080 78.980 845.480 79.380 ;
    END
  END Tile_X3Y0_S4END[4]
  PIN Tile_X3Y0_S4END[5]
    DIRECTION INPUT ;
    USE SIGNAL ;
    ANTENNAGATEAREA 0.426400 ;
    PORT
      LAYER Metal2 ;
        RECT 846.040 78.980 846.440 79.380 ;
    END
  END Tile_X3Y0_S4END[5]
  PIN Tile_X3Y0_S4END[6]
    DIRECTION INPUT ;
    USE SIGNAL ;
    ANTENNAGATEAREA 0.426400 ;
    PORT
      LAYER Metal2 ;
        RECT 847.000 78.980 847.400 79.380 ;
    END
  END Tile_X3Y0_S4END[6]
  PIN Tile_X3Y0_S4END[7]
    DIRECTION INPUT ;
    USE SIGNAL ;
    ANTENNAGATEAREA 0.426400 ;
    PORT
      LAYER Metal2 ;
        RECT 847.960 78.980 848.360 79.380 ;
    END
  END Tile_X3Y0_S4END[7]
  PIN Tile_X3Y0_S4END[8]
    DIRECTION INPUT ;
    USE SIGNAL ;
    ANTENNAGATEAREA 0.426400 ;
    ANTENNADIFFAREA 8.061600 ;
    PORT
      LAYER Metal2 ;
        RECT 848.920 78.980 849.320 79.380 ;
    END
  END Tile_X3Y0_S4END[8]
  PIN Tile_X3Y0_S4END[9]
    DIRECTION INPUT ;
    USE SIGNAL ;
    ANTENNAGATEAREA 0.426400 ;
    PORT
      LAYER Metal2 ;
        RECT 849.880 78.980 850.280 79.380 ;
    END
  END Tile_X3Y0_S4END[9]
  PIN Tile_X3Y0_SS4END[0]
    DIRECTION INPUT ;
    USE SIGNAL ;
    ANTENNAGATEAREA 0.426400 ;
    PORT
      LAYER Metal2 ;
        RECT 871.000 78.980 871.400 79.380 ;
    END
  END Tile_X3Y0_SS4END[0]
  PIN Tile_X3Y0_SS4END[10]
    DIRECTION INPUT ;
    USE SIGNAL ;
    ANTENNAGATEAREA 0.426400 ;
    PORT
      LAYER Metal2 ;
        RECT 880.600 78.980 881.000 79.380 ;
    END
  END Tile_X3Y0_SS4END[10]
  PIN Tile_X3Y0_SS4END[11]
    DIRECTION INPUT ;
    USE SIGNAL ;
    ANTENNAGATEAREA 0.426400 ;
    PORT
      LAYER Metal2 ;
        RECT 881.560 78.980 881.960 79.380 ;
    END
  END Tile_X3Y0_SS4END[11]
  PIN Tile_X3Y0_SS4END[12]
    DIRECTION INPUT ;
    USE SIGNAL ;
    ANTENNAGATEAREA 0.426400 ;
    PORT
      LAYER Metal2 ;
        RECT 882.520 78.980 882.920 79.380 ;
    END
  END Tile_X3Y0_SS4END[12]
  PIN Tile_X3Y0_SS4END[13]
    DIRECTION INPUT ;
    USE SIGNAL ;
    ANTENNAGATEAREA 0.426400 ;
    PORT
      LAYER Metal2 ;
        RECT 883.480 78.980 883.880 79.380 ;
    END
  END Tile_X3Y0_SS4END[13]
  PIN Tile_X3Y0_SS4END[14]
    DIRECTION INPUT ;
    USE SIGNAL ;
    ANTENNAGATEAREA 0.426400 ;
    PORT
      LAYER Metal2 ;
        RECT 884.440 78.980 884.840 79.380 ;
    END
  END Tile_X3Y0_SS4END[14]
  PIN Tile_X3Y0_SS4END[15]
    DIRECTION INPUT ;
    USE SIGNAL ;
    ANTENNAGATEAREA 0.426400 ;
    ANTENNADIFFAREA 8.061600 ;
    PORT
      LAYER Metal2 ;
        RECT 885.400 78.980 885.800 79.380 ;
    END
  END Tile_X3Y0_SS4END[15]
  PIN Tile_X3Y0_SS4END[1]
    DIRECTION INPUT ;
    USE SIGNAL ;
    ANTENNAGATEAREA 0.426400 ;
    PORT
      LAYER Metal2 ;
        RECT 871.960 78.980 872.360 79.380 ;
    END
  END Tile_X3Y0_SS4END[1]
  PIN Tile_X3Y0_SS4END[2]
    DIRECTION INPUT ;
    USE SIGNAL ;
    ANTENNAGATEAREA 0.426400 ;
    PORT
      LAYER Metal2 ;
        RECT 872.920 78.980 873.320 79.380 ;
    END
  END Tile_X3Y0_SS4END[2]
  PIN Tile_X3Y0_SS4END[3]
    DIRECTION INPUT ;
    USE SIGNAL ;
    ANTENNAGATEAREA 0.426400 ;
    PORT
      LAYER Metal2 ;
        RECT 873.880 78.980 874.280 79.380 ;
    END
  END Tile_X3Y0_SS4END[3]
  PIN Tile_X3Y0_SS4END[4]
    DIRECTION INPUT ;
    USE SIGNAL ;
    ANTENNAGATEAREA 0.426400 ;
    PORT
      LAYER Metal2 ;
        RECT 874.840 78.980 875.240 79.380 ;
    END
  END Tile_X3Y0_SS4END[4]
  PIN Tile_X3Y0_SS4END[5]
    DIRECTION INPUT ;
    USE SIGNAL ;
    ANTENNAGATEAREA 0.426400 ;
    ANTENNADIFFAREA 8.061600 ;
    PORT
      LAYER Metal2 ;
        RECT 875.800 78.980 876.200 79.380 ;
    END
  END Tile_X3Y0_SS4END[5]
  PIN Tile_X3Y0_SS4END[6]
    DIRECTION INPUT ;
    USE SIGNAL ;
    ANTENNAGATEAREA 0.426400 ;
    PORT
      LAYER Metal2 ;
        RECT 876.760 78.980 877.160 79.380 ;
    END
  END Tile_X3Y0_SS4END[6]
  PIN Tile_X3Y0_SS4END[7]
    DIRECTION INPUT ;
    USE SIGNAL ;
    ANTENNAGATEAREA 0.426400 ;
    ANTENNADIFFAREA 8.061600 ;
    PORT
      LAYER Metal2 ;
        RECT 877.720 78.980 878.120 79.380 ;
    END
  END Tile_X3Y0_SS4END[7]
  PIN Tile_X3Y0_SS4END[8]
    DIRECTION INPUT ;
    USE SIGNAL ;
    ANTENNAGATEAREA 0.426400 ;
    PORT
      LAYER Metal2 ;
        RECT 878.680 78.980 879.080 79.380 ;
    END
  END Tile_X3Y0_SS4END[8]
  PIN Tile_X3Y0_SS4END[9]
    DIRECTION INPUT ;
    USE SIGNAL ;
    ANTENNAGATEAREA 0.426400 ;
    PORT
      LAYER Metal2 ;
        RECT 879.640 78.980 880.040 79.380 ;
    END
  END Tile_X3Y0_SS4END[9]
  PIN Tile_X4Y0_Co
    DIRECTION OUTPUT ;
    USE SIGNAL ;
    ANTENNADIFFAREA 2.314600 ;
    PORT
      LAYER Metal2 ;
        RECT 1127.320 78.980 1127.720 79.380 ;
    END
  END Tile_X4Y0_Co
  PIN Tile_X4Y0_FrameData_O[0]
    DIRECTION OUTPUT ;
    USE SIGNAL ;
    ANTENNADIFFAREA 2.724000 ;
    PORT
      LAYER Metal3 ;
        RECT 1166.000 15.340 1166.400 15.740 ;
    END
  END Tile_X4Y0_FrameData_O[0]
  PIN Tile_X4Y0_FrameData_O[10]
    DIRECTION OUTPUT ;
    USE SIGNAL ;
    ANTENNADIFFAREA 2.724000 ;
    PORT
      LAYER Metal3 ;
        RECT 1166.000 32.140 1166.400 32.540 ;
    END
  END Tile_X4Y0_FrameData_O[10]
  PIN Tile_X4Y0_FrameData_O[11]
    DIRECTION OUTPUT ;
    USE SIGNAL ;
    ANTENNADIFFAREA 2.724000 ;
    PORT
      LAYER Metal3 ;
        RECT 1166.000 33.820 1166.400 34.220 ;
    END
  END Tile_X4Y0_FrameData_O[11]
  PIN Tile_X4Y0_FrameData_O[12]
    DIRECTION OUTPUT ;
    USE SIGNAL ;
    ANTENNADIFFAREA 2.724000 ;
    PORT
      LAYER Metal3 ;
        RECT 1166.000 35.500 1166.400 35.900 ;
    END
  END Tile_X4Y0_FrameData_O[12]
  PIN Tile_X4Y0_FrameData_O[13]
    DIRECTION OUTPUT ;
    USE SIGNAL ;
    ANTENNADIFFAREA 2.724000 ;
    PORT
      LAYER Metal3 ;
        RECT 1166.000 37.180 1166.400 37.580 ;
    END
  END Tile_X4Y0_FrameData_O[13]
  PIN Tile_X4Y0_FrameData_O[14]
    DIRECTION OUTPUT ;
    USE SIGNAL ;
    ANTENNADIFFAREA 2.724000 ;
    PORT
      LAYER Metal3 ;
        RECT 1166.000 38.860 1166.400 39.260 ;
    END
  END Tile_X4Y0_FrameData_O[14]
  PIN Tile_X4Y0_FrameData_O[15]
    DIRECTION OUTPUT ;
    USE SIGNAL ;
    ANTENNADIFFAREA 2.724000 ;
    PORT
      LAYER Metal3 ;
        RECT 1166.000 40.540 1166.400 40.940 ;
    END
  END Tile_X4Y0_FrameData_O[15]
  PIN Tile_X4Y0_FrameData_O[16]
    DIRECTION OUTPUT ;
    USE SIGNAL ;
    ANTENNADIFFAREA 2.724000 ;
    PORT
      LAYER Metal3 ;
        RECT 1166.000 42.220 1166.400 42.620 ;
    END
  END Tile_X4Y0_FrameData_O[16]
  PIN Tile_X4Y0_FrameData_O[17]
    DIRECTION OUTPUT ;
    USE SIGNAL ;
    ANTENNADIFFAREA 2.724000 ;
    PORT
      LAYER Metal3 ;
        RECT 1166.000 43.900 1166.400 44.300 ;
    END
  END Tile_X4Y0_FrameData_O[17]
  PIN Tile_X4Y0_FrameData_O[18]
    DIRECTION OUTPUT ;
    USE SIGNAL ;
    ANTENNADIFFAREA 2.724000 ;
    PORT
      LAYER Metal3 ;
        RECT 1166.000 45.580 1166.400 45.980 ;
    END
  END Tile_X4Y0_FrameData_O[18]
  PIN Tile_X4Y0_FrameData_O[19]
    DIRECTION OUTPUT ;
    USE SIGNAL ;
    ANTENNADIFFAREA 2.724000 ;
    PORT
      LAYER Metal3 ;
        RECT 1166.000 47.260 1166.400 47.660 ;
    END
  END Tile_X4Y0_FrameData_O[19]
  PIN Tile_X4Y0_FrameData_O[1]
    DIRECTION OUTPUT ;
    USE SIGNAL ;
    ANTENNADIFFAREA 2.724000 ;
    PORT
      LAYER Metal3 ;
        RECT 1166.000 17.020 1166.400 17.420 ;
    END
  END Tile_X4Y0_FrameData_O[1]
  PIN Tile_X4Y0_FrameData_O[20]
    DIRECTION OUTPUT ;
    USE SIGNAL ;
    ANTENNADIFFAREA 2.724000 ;
    PORT
      LAYER Metal3 ;
        RECT 1166.000 48.940 1166.400 49.340 ;
    END
  END Tile_X4Y0_FrameData_O[20]
  PIN Tile_X4Y0_FrameData_O[21]
    DIRECTION OUTPUT ;
    USE SIGNAL ;
    ANTENNADIFFAREA 2.724000 ;
    PORT
      LAYER Metal3 ;
        RECT 1166.000 50.620 1166.400 51.020 ;
    END
  END Tile_X4Y0_FrameData_O[21]
  PIN Tile_X4Y0_FrameData_O[22]
    DIRECTION OUTPUT ;
    USE SIGNAL ;
    ANTENNADIFFAREA 2.724000 ;
    PORT
      LAYER Metal3 ;
        RECT 1166.000 52.300 1166.400 52.700 ;
    END
  END Tile_X4Y0_FrameData_O[22]
  PIN Tile_X4Y0_FrameData_O[23]
    DIRECTION OUTPUT ;
    USE SIGNAL ;
    ANTENNADIFFAREA 2.724000 ;
    PORT
      LAYER Metal3 ;
        RECT 1166.000 53.980 1166.400 54.380 ;
    END
  END Tile_X4Y0_FrameData_O[23]
  PIN Tile_X4Y0_FrameData_O[24]
    DIRECTION OUTPUT ;
    USE SIGNAL ;
    ANTENNADIFFAREA 2.724000 ;
    PORT
      LAYER Metal3 ;
        RECT 1166.000 55.660 1166.400 56.060 ;
    END
  END Tile_X4Y0_FrameData_O[24]
  PIN Tile_X4Y0_FrameData_O[25]
    DIRECTION OUTPUT ;
    USE SIGNAL ;
    ANTENNADIFFAREA 2.724000 ;
    PORT
      LAYER Metal3 ;
        RECT 1166.000 57.340 1166.400 57.740 ;
    END
  END Tile_X4Y0_FrameData_O[25]
  PIN Tile_X4Y0_FrameData_O[26]
    DIRECTION OUTPUT ;
    USE SIGNAL ;
    ANTENNADIFFAREA 2.724000 ;
    PORT
      LAYER Metal3 ;
        RECT 1166.000 59.020 1166.400 59.420 ;
    END
  END Tile_X4Y0_FrameData_O[26]
  PIN Tile_X4Y0_FrameData_O[27]
    DIRECTION OUTPUT ;
    USE SIGNAL ;
    ANTENNADIFFAREA 2.724000 ;
    PORT
      LAYER Metal3 ;
        RECT 1166.000 60.700 1166.400 61.100 ;
    END
  END Tile_X4Y0_FrameData_O[27]
  PIN Tile_X4Y0_FrameData_O[28]
    DIRECTION OUTPUT ;
    USE SIGNAL ;
    ANTENNADIFFAREA 2.724000 ;
    PORT
      LAYER Metal3 ;
        RECT 1166.000 62.380 1166.400 62.780 ;
    END
  END Tile_X4Y0_FrameData_O[28]
  PIN Tile_X4Y0_FrameData_O[29]
    DIRECTION OUTPUT ;
    USE SIGNAL ;
    ANTENNADIFFAREA 2.724000 ;
    PORT
      LAYER Metal3 ;
        RECT 1166.000 64.060 1166.400 64.460 ;
    END
  END Tile_X4Y0_FrameData_O[29]
  PIN Tile_X4Y0_FrameData_O[2]
    DIRECTION OUTPUT ;
    USE SIGNAL ;
    ANTENNADIFFAREA 2.724000 ;
    PORT
      LAYER Metal3 ;
        RECT 1166.000 18.700 1166.400 19.100 ;
    END
  END Tile_X4Y0_FrameData_O[2]
  PIN Tile_X4Y0_FrameData_O[30]
    DIRECTION OUTPUT ;
    USE SIGNAL ;
    ANTENNADIFFAREA 2.724000 ;
    PORT
      LAYER Metal3 ;
        RECT 1166.000 65.740 1166.400 66.140 ;
    END
  END Tile_X4Y0_FrameData_O[30]
  PIN Tile_X4Y0_FrameData_O[31]
    DIRECTION OUTPUT ;
    USE SIGNAL ;
    ANTENNADIFFAREA 2.724000 ;
    PORT
      LAYER Metal3 ;
        RECT 1166.000 67.420 1166.400 67.820 ;
    END
  END Tile_X4Y0_FrameData_O[31]
  PIN Tile_X4Y0_FrameData_O[3]
    DIRECTION OUTPUT ;
    USE SIGNAL ;
    ANTENNADIFFAREA 2.724000 ;
    PORT
      LAYER Metal3 ;
        RECT 1166.000 20.380 1166.400 20.780 ;
    END
  END Tile_X4Y0_FrameData_O[3]
  PIN Tile_X4Y0_FrameData_O[4]
    DIRECTION OUTPUT ;
    USE SIGNAL ;
    ANTENNADIFFAREA 2.724000 ;
    PORT
      LAYER Metal3 ;
        RECT 1166.000 22.060 1166.400 22.460 ;
    END
  END Tile_X4Y0_FrameData_O[4]
  PIN Tile_X4Y0_FrameData_O[5]
    DIRECTION OUTPUT ;
    USE SIGNAL ;
    ANTENNADIFFAREA 2.724000 ;
    PORT
      LAYER Metal3 ;
        RECT 1166.000 23.740 1166.400 24.140 ;
    END
  END Tile_X4Y0_FrameData_O[5]
  PIN Tile_X4Y0_FrameData_O[6]
    DIRECTION OUTPUT ;
    USE SIGNAL ;
    ANTENNADIFFAREA 2.724000 ;
    PORT
      LAYER Metal3 ;
        RECT 1166.000 25.420 1166.400 25.820 ;
    END
  END Tile_X4Y0_FrameData_O[6]
  PIN Tile_X4Y0_FrameData_O[7]
    DIRECTION OUTPUT ;
    USE SIGNAL ;
    ANTENNADIFFAREA 2.724000 ;
    PORT
      LAYER Metal3 ;
        RECT 1166.000 27.100 1166.400 27.500 ;
    END
  END Tile_X4Y0_FrameData_O[7]
  PIN Tile_X4Y0_FrameData_O[8]
    DIRECTION OUTPUT ;
    USE SIGNAL ;
    ANTENNADIFFAREA 2.724000 ;
    PORT
      LAYER Metal3 ;
        RECT 1166.000 28.780 1166.400 29.180 ;
    END
  END Tile_X4Y0_FrameData_O[8]
  PIN Tile_X4Y0_FrameData_O[9]
    DIRECTION OUTPUT ;
    USE SIGNAL ;
    ANTENNADIFFAREA 2.724000 ;
    PORT
      LAYER Metal3 ;
        RECT 1166.000 30.460 1166.400 30.860 ;
    END
  END Tile_X4Y0_FrameData_O[9]
  PIN Tile_X4Y0_FrameStrobe[0]
    DIRECTION INPUT ;
    USE SIGNAL ;
    ANTENNAGATEAREA 5.240300 ;
    PORT
      LAYER Metal2 ;
        RECT 938.200 0.000 938.600 0.400 ;
    END
  END Tile_X4Y0_FrameStrobe[0]
  PIN Tile_X4Y0_FrameStrobe[10]
    DIRECTION INPUT ;
    USE SIGNAL ;
    ANTENNAGATEAREA 0.180700 ;
    PORT
      LAYER Metal2 ;
        RECT 957.400 0.000 957.800 0.400 ;
    END
  END Tile_X4Y0_FrameStrobe[10]
  PIN Tile_X4Y0_FrameStrobe[11]
    DIRECTION INPUT ;
    USE SIGNAL ;
    ANTENNAGATEAREA 0.180700 ;
    PORT
      LAYER Metal2 ;
        RECT 959.320 0.000 959.720 0.400 ;
    END
  END Tile_X4Y0_FrameStrobe[11]
  PIN Tile_X4Y0_FrameStrobe[12]
    DIRECTION INPUT ;
    USE SIGNAL ;
    ANTENNAGATEAREA 0.180700 ;
    PORT
      LAYER Metal2 ;
        RECT 961.240 0.000 961.640 0.400 ;
    END
  END Tile_X4Y0_FrameStrobe[12]
  PIN Tile_X4Y0_FrameStrobe[13]
    DIRECTION INPUT ;
    USE SIGNAL ;
    ANTENNAGATEAREA 0.180700 ;
    PORT
      LAYER Metal2 ;
        RECT 963.160 0.000 963.560 0.400 ;
    END
  END Tile_X4Y0_FrameStrobe[13]
  PIN Tile_X4Y0_FrameStrobe[14]
    DIRECTION INPUT ;
    USE SIGNAL ;
    ANTENNAGATEAREA 0.180700 ;
    PORT
      LAYER Metal2 ;
        RECT 965.080 0.000 965.480 0.400 ;
    END
  END Tile_X4Y0_FrameStrobe[14]
  PIN Tile_X4Y0_FrameStrobe[15]
    DIRECTION INPUT ;
    USE SIGNAL ;
    ANTENNAGATEAREA 0.180700 ;
    PORT
      LAYER Metal2 ;
        RECT 967.000 0.000 967.400 0.400 ;
    END
  END Tile_X4Y0_FrameStrobe[15]
  PIN Tile_X4Y0_FrameStrobe[16]
    DIRECTION INPUT ;
    USE SIGNAL ;
    ANTENNAGATEAREA 0.180700 ;
    PORT
      LAYER Metal2 ;
        RECT 968.920 0.000 969.320 0.400 ;
    END
  END Tile_X4Y0_FrameStrobe[16]
  PIN Tile_X4Y0_FrameStrobe[17]
    DIRECTION INPUT ;
    USE SIGNAL ;
    ANTENNAGATEAREA 0.180700 ;
    PORT
      LAYER Metal2 ;
        RECT 970.840 0.000 971.240 0.400 ;
    END
  END Tile_X4Y0_FrameStrobe[17]
  PIN Tile_X4Y0_FrameStrobe[18]
    DIRECTION INPUT ;
    USE SIGNAL ;
    ANTENNAGATEAREA 0.180700 ;
    PORT
      LAYER Metal2 ;
        RECT 972.760 0.000 973.160 0.400 ;
    END
  END Tile_X4Y0_FrameStrobe[18]
  PIN Tile_X4Y0_FrameStrobe[19]
    DIRECTION INPUT ;
    USE SIGNAL ;
    ANTENNAGATEAREA 0.180700 ;
    PORT
      LAYER Metal2 ;
        RECT 974.680 0.000 975.080 0.400 ;
    END
  END Tile_X4Y0_FrameStrobe[19]
  PIN Tile_X4Y0_FrameStrobe[1]
    DIRECTION INPUT ;
    USE SIGNAL ;
    ANTENNAGATEAREA 0.180700 ;
    PORT
      LAYER Metal2 ;
        RECT 940.120 0.000 940.520 0.400 ;
    END
  END Tile_X4Y0_FrameStrobe[1]
  PIN Tile_X4Y0_FrameStrobe[2]
    DIRECTION INPUT ;
    USE SIGNAL ;
    ANTENNAGATEAREA 0.180700 ;
    PORT
      LAYER Metal2 ;
        RECT 942.040 0.000 942.440 0.400 ;
    END
  END Tile_X4Y0_FrameStrobe[2]
  PIN Tile_X4Y0_FrameStrobe[3]
    DIRECTION INPUT ;
    USE SIGNAL ;
    ANTENNAGATEAREA 0.180700 ;
    PORT
      LAYER Metal2 ;
        RECT 943.960 0.000 944.360 0.400 ;
    END
  END Tile_X4Y0_FrameStrobe[3]
  PIN Tile_X4Y0_FrameStrobe[4]
    DIRECTION INPUT ;
    USE SIGNAL ;
    ANTENNAGATEAREA 0.180700 ;
    PORT
      LAYER Metal2 ;
        RECT 945.880 0.000 946.280 0.400 ;
    END
  END Tile_X4Y0_FrameStrobe[4]
  PIN Tile_X4Y0_FrameStrobe[5]
    DIRECTION INPUT ;
    USE SIGNAL ;
    ANTENNAGATEAREA 0.180700 ;
    PORT
      LAYER Metal2 ;
        RECT 947.800 0.000 948.200 0.400 ;
    END
  END Tile_X4Y0_FrameStrobe[5]
  PIN Tile_X4Y0_FrameStrobe[6]
    DIRECTION INPUT ;
    USE SIGNAL ;
    ANTENNAGATEAREA 0.180700 ;
    PORT
      LAYER Metal2 ;
        RECT 949.720 0.000 950.120 0.400 ;
    END
  END Tile_X4Y0_FrameStrobe[6]
  PIN Tile_X4Y0_FrameStrobe[7]
    DIRECTION INPUT ;
    USE SIGNAL ;
    ANTENNAGATEAREA 0.180700 ;
    PORT
      LAYER Metal2 ;
        RECT 951.640 0.000 952.040 0.400 ;
    END
  END Tile_X4Y0_FrameStrobe[7]
  PIN Tile_X4Y0_FrameStrobe[8]
    DIRECTION INPUT ;
    USE SIGNAL ;
    ANTENNAGATEAREA 0.180700 ;
    PORT
      LAYER Metal2 ;
        RECT 953.560 0.000 953.960 0.400 ;
    END
  END Tile_X4Y0_FrameStrobe[8]
  PIN Tile_X4Y0_FrameStrobe[9]
    DIRECTION INPUT ;
    USE SIGNAL ;
    ANTENNAGATEAREA 0.180700 ;
    PORT
      LAYER Metal2 ;
        RECT 955.480 0.000 955.880 0.400 ;
    END
  END Tile_X4Y0_FrameStrobe[9]
  PIN Tile_X4Y0_FrameStrobe_O[0]
    DIRECTION OUTPUT ;
    USE SIGNAL ;
    ANTENNADIFFAREA 2.724000 ;
    PORT
      LAYER Metal2 ;
        RECT 1137.880 78.980 1138.280 79.380 ;
    END
  END Tile_X4Y0_FrameStrobe_O[0]
  PIN Tile_X4Y0_FrameStrobe_O[10]
    DIRECTION OUTPUT ;
    USE SIGNAL ;
    ANTENNADIFFAREA 2.724000 ;
    PORT
      LAYER Metal2 ;
        RECT 1147.480 78.980 1147.880 79.380 ;
    END
  END Tile_X4Y0_FrameStrobe_O[10]
  PIN Tile_X4Y0_FrameStrobe_O[11]
    DIRECTION OUTPUT ;
    USE SIGNAL ;
    ANTENNADIFFAREA 2.724000 ;
    PORT
      LAYER Metal2 ;
        RECT 1148.440 78.980 1148.840 79.380 ;
    END
  END Tile_X4Y0_FrameStrobe_O[11]
  PIN Tile_X4Y0_FrameStrobe_O[12]
    DIRECTION OUTPUT ;
    USE SIGNAL ;
    ANTENNADIFFAREA 2.724000 ;
    PORT
      LAYER Metal2 ;
        RECT 1149.400 78.980 1149.800 79.380 ;
    END
  END Tile_X4Y0_FrameStrobe_O[12]
  PIN Tile_X4Y0_FrameStrobe_O[13]
    DIRECTION OUTPUT ;
    USE SIGNAL ;
    ANTENNADIFFAREA 2.724000 ;
    PORT
      LAYER Metal2 ;
        RECT 1150.360 78.980 1150.760 79.380 ;
    END
  END Tile_X4Y0_FrameStrobe_O[13]
  PIN Tile_X4Y0_FrameStrobe_O[14]
    DIRECTION OUTPUT ;
    USE SIGNAL ;
    ANTENNADIFFAREA 2.724000 ;
    PORT
      LAYER Metal2 ;
        RECT 1151.320 78.980 1151.720 79.380 ;
    END
  END Tile_X4Y0_FrameStrobe_O[14]
  PIN Tile_X4Y0_FrameStrobe_O[15]
    DIRECTION OUTPUT ;
    USE SIGNAL ;
    ANTENNADIFFAREA 2.724000 ;
    PORT
      LAYER Metal2 ;
        RECT 1152.280 78.980 1152.680 79.380 ;
    END
  END Tile_X4Y0_FrameStrobe_O[15]
  PIN Tile_X4Y0_FrameStrobe_O[16]
    DIRECTION OUTPUT ;
    USE SIGNAL ;
    ANTENNADIFFAREA 2.724000 ;
    PORT
      LAYER Metal2 ;
        RECT 1153.240 78.980 1153.640 79.380 ;
    END
  END Tile_X4Y0_FrameStrobe_O[16]
  PIN Tile_X4Y0_FrameStrobe_O[17]
    DIRECTION OUTPUT ;
    USE SIGNAL ;
    ANTENNADIFFAREA 2.724000 ;
    PORT
      LAYER Metal2 ;
        RECT 1154.200 78.980 1154.600 79.380 ;
    END
  END Tile_X4Y0_FrameStrobe_O[17]
  PIN Tile_X4Y0_FrameStrobe_O[18]
    DIRECTION OUTPUT ;
    USE SIGNAL ;
    ANTENNADIFFAREA 2.724000 ;
    PORT
      LAYER Metal2 ;
        RECT 1155.160 78.980 1155.560 79.380 ;
    END
  END Tile_X4Y0_FrameStrobe_O[18]
  PIN Tile_X4Y0_FrameStrobe_O[19]
    DIRECTION OUTPUT ;
    USE SIGNAL ;
    ANTENNADIFFAREA 2.724000 ;
    PORT
      LAYER Metal2 ;
        RECT 1156.120 78.980 1156.520 79.380 ;
    END
  END Tile_X4Y0_FrameStrobe_O[19]
  PIN Tile_X4Y0_FrameStrobe_O[1]
    DIRECTION OUTPUT ;
    USE SIGNAL ;
    ANTENNADIFFAREA 2.724000 ;
    PORT
      LAYER Metal2 ;
        RECT 1138.840 78.980 1139.240 79.380 ;
    END
  END Tile_X4Y0_FrameStrobe_O[1]
  PIN Tile_X4Y0_FrameStrobe_O[2]
    DIRECTION OUTPUT ;
    USE SIGNAL ;
    ANTENNADIFFAREA 2.724000 ;
    PORT
      LAYER Metal2 ;
        RECT 1139.800 78.980 1140.200 79.380 ;
    END
  END Tile_X4Y0_FrameStrobe_O[2]
  PIN Tile_X4Y0_FrameStrobe_O[3]
    DIRECTION OUTPUT ;
    USE SIGNAL ;
    ANTENNADIFFAREA 2.724000 ;
    PORT
      LAYER Metal2 ;
        RECT 1140.760 78.980 1141.160 79.380 ;
    END
  END Tile_X4Y0_FrameStrobe_O[3]
  PIN Tile_X4Y0_FrameStrobe_O[4]
    DIRECTION OUTPUT ;
    USE SIGNAL ;
    ANTENNADIFFAREA 2.724000 ;
    PORT
      LAYER Metal2 ;
        RECT 1141.720 78.980 1142.120 79.380 ;
    END
  END Tile_X4Y0_FrameStrobe_O[4]
  PIN Tile_X4Y0_FrameStrobe_O[5]
    DIRECTION OUTPUT ;
    USE SIGNAL ;
    ANTENNADIFFAREA 2.724000 ;
    PORT
      LAYER Metal2 ;
        RECT 1142.680 78.980 1143.080 79.380 ;
    END
  END Tile_X4Y0_FrameStrobe_O[5]
  PIN Tile_X4Y0_FrameStrobe_O[6]
    DIRECTION OUTPUT ;
    USE SIGNAL ;
    ANTENNADIFFAREA 2.724000 ;
    PORT
      LAYER Metal2 ;
        RECT 1143.640 78.980 1144.040 79.380 ;
    END
  END Tile_X4Y0_FrameStrobe_O[6]
  PIN Tile_X4Y0_FrameStrobe_O[7]
    DIRECTION OUTPUT ;
    USE SIGNAL ;
    ANTENNADIFFAREA 2.724000 ;
    PORT
      LAYER Metal2 ;
        RECT 1144.600 78.980 1145.000 79.380 ;
    END
  END Tile_X4Y0_FrameStrobe_O[7]
  PIN Tile_X4Y0_FrameStrobe_O[8]
    DIRECTION OUTPUT ;
    USE SIGNAL ;
    ANTENNADIFFAREA 2.724000 ;
    PORT
      LAYER Metal2 ;
        RECT 1145.560 78.980 1145.960 79.380 ;
    END
  END Tile_X4Y0_FrameStrobe_O[8]
  PIN Tile_X4Y0_FrameStrobe_O[9]
    DIRECTION OUTPUT ;
    USE SIGNAL ;
    ANTENNADIFFAREA 2.724000 ;
    PORT
      LAYER Metal2 ;
        RECT 1146.520 78.980 1146.920 79.380 ;
    END
  END Tile_X4Y0_FrameStrobe_O[9]
  PIN Tile_X4Y0_N1BEG[0]
    DIRECTION OUTPUT ;
    USE SIGNAL ;
    ANTENNADIFFAREA 2.724000 ;
    PORT
      LAYER Metal2 ;
        RECT 934.360 78.980 934.760 79.380 ;
    END
  END Tile_X4Y0_N1BEG[0]
  PIN Tile_X4Y0_N1BEG[1]
    DIRECTION OUTPUT ;
    USE SIGNAL ;
    ANTENNADIFFAREA 2.724000 ;
    PORT
      LAYER Metal2 ;
        RECT 936.280 78.980 936.680 79.380 ;
    END
  END Tile_X4Y0_N1BEG[1]
  PIN Tile_X4Y0_N1BEG[2]
    DIRECTION OUTPUT ;
    USE SIGNAL ;
    ANTENNADIFFAREA 2.724000 ;
    PORT
      LAYER Metal2 ;
        RECT 938.200 78.980 938.600 79.380 ;
    END
  END Tile_X4Y0_N1BEG[2]
  PIN Tile_X4Y0_N1BEG[3]
    DIRECTION OUTPUT ;
    USE SIGNAL ;
    ANTENNADIFFAREA 2.724000 ;
    PORT
      LAYER Metal2 ;
        RECT 940.120 78.980 940.520 79.380 ;
    END
  END Tile_X4Y0_N1BEG[3]
  PIN Tile_X4Y0_N2BEG[0]
    DIRECTION OUTPUT ;
    USE SIGNAL ;
    ANTENNADIFFAREA 2.724000 ;
    PORT
      LAYER Metal2 ;
        RECT 944.920 78.980 945.320 79.380 ;
    END
  END Tile_X4Y0_N2BEG[0]
  PIN Tile_X4Y0_N2BEG[1]
    DIRECTION OUTPUT ;
    USE SIGNAL ;
    ANTENNADIFFAREA 2.724000 ;
    PORT
      LAYER Metal2 ;
        RECT 945.880 78.980 946.280 79.380 ;
    END
  END Tile_X4Y0_N2BEG[1]
  PIN Tile_X4Y0_N2BEG[2]
    DIRECTION OUTPUT ;
    USE SIGNAL ;
    ANTENNADIFFAREA 2.724000 ;
    PORT
      LAYER Metal2 ;
        RECT 946.840 78.980 947.240 79.380 ;
    END
  END Tile_X4Y0_N2BEG[2]
  PIN Tile_X4Y0_N2BEG[3]
    DIRECTION OUTPUT ;
    USE SIGNAL ;
    ANTENNADIFFAREA 2.724000 ;
    PORT
      LAYER Metal2 ;
        RECT 947.800 78.980 948.200 79.380 ;
    END
  END Tile_X4Y0_N2BEG[3]
  PIN Tile_X4Y0_N2BEG[4]
    DIRECTION OUTPUT ;
    USE SIGNAL ;
    ANTENNADIFFAREA 2.724000 ;
    PORT
      LAYER Metal2 ;
        RECT 948.760 78.980 949.160 79.380 ;
    END
  END Tile_X4Y0_N2BEG[4]
  PIN Tile_X4Y0_N2BEG[5]
    DIRECTION OUTPUT ;
    USE SIGNAL ;
    ANTENNADIFFAREA 2.724000 ;
    PORT
      LAYER Metal2 ;
        RECT 949.720 78.980 950.120 79.380 ;
    END
  END Tile_X4Y0_N2BEG[5]
  PIN Tile_X4Y0_N2BEG[6]
    DIRECTION OUTPUT ;
    USE SIGNAL ;
    ANTENNADIFFAREA 2.724000 ;
    PORT
      LAYER Metal2 ;
        RECT 950.680 78.980 951.080 79.380 ;
    END
  END Tile_X4Y0_N2BEG[6]
  PIN Tile_X4Y0_N2BEG[7]
    DIRECTION OUTPUT ;
    USE SIGNAL ;
    ANTENNADIFFAREA 2.724000 ;
    PORT
      LAYER Metal2 ;
        RECT 951.640 78.980 952.040 79.380 ;
    END
  END Tile_X4Y0_N2BEG[7]
  PIN Tile_X4Y0_N2BEGb[0]
    DIRECTION OUTPUT ;
    USE SIGNAL ;
    ANTENNADIFFAREA 2.724000 ;
    PORT
      LAYER Metal2 ;
        RECT 959.320 78.980 959.720 79.380 ;
    END
  END Tile_X4Y0_N2BEGb[0]
  PIN Tile_X4Y0_N2BEGb[1]
    DIRECTION OUTPUT ;
    USE SIGNAL ;
    ANTENNADIFFAREA 2.724000 ;
    PORT
      LAYER Metal2 ;
        RECT 960.280 78.980 960.680 79.380 ;
    END
  END Tile_X4Y0_N2BEGb[1]
  PIN Tile_X4Y0_N2BEGb[2]
    DIRECTION OUTPUT ;
    USE SIGNAL ;
    ANTENNADIFFAREA 2.724000 ;
    PORT
      LAYER Metal2 ;
        RECT 961.240 78.980 961.640 79.380 ;
    END
  END Tile_X4Y0_N2BEGb[2]
  PIN Tile_X4Y0_N2BEGb[3]
    DIRECTION OUTPUT ;
    USE SIGNAL ;
    ANTENNADIFFAREA 2.724000 ;
    PORT
      LAYER Metal2 ;
        RECT 962.200 78.980 962.600 79.380 ;
    END
  END Tile_X4Y0_N2BEGb[3]
  PIN Tile_X4Y0_N2BEGb[4]
    DIRECTION OUTPUT ;
    USE SIGNAL ;
    ANTENNADIFFAREA 2.724000 ;
    PORT
      LAYER Metal2 ;
        RECT 963.160 78.980 963.560 79.380 ;
    END
  END Tile_X4Y0_N2BEGb[4]
  PIN Tile_X4Y0_N2BEGb[5]
    DIRECTION OUTPUT ;
    USE SIGNAL ;
    ANTENNADIFFAREA 2.724000 ;
    PORT
      LAYER Metal2 ;
        RECT 964.120 78.980 964.520 79.380 ;
    END
  END Tile_X4Y0_N2BEGb[5]
  PIN Tile_X4Y0_N2BEGb[6]
    DIRECTION OUTPUT ;
    USE SIGNAL ;
    ANTENNADIFFAREA 2.724000 ;
    PORT
      LAYER Metal2 ;
        RECT 965.080 78.980 965.480 79.380 ;
    END
  END Tile_X4Y0_N2BEGb[6]
  PIN Tile_X4Y0_N2BEGb[7]
    DIRECTION OUTPUT ;
    USE SIGNAL ;
    ANTENNADIFFAREA 2.724000 ;
    PORT
      LAYER Metal2 ;
        RECT 966.040 78.980 966.440 79.380 ;
    END
  END Tile_X4Y0_N2BEGb[7]
  PIN Tile_X4Y0_N4BEG[0]
    DIRECTION OUTPUT ;
    USE SIGNAL ;
    ANTENNADIFFAREA 2.724000 ;
    PORT
      LAYER Metal2 ;
        RECT 977.560 78.980 977.960 79.380 ;
    END
  END Tile_X4Y0_N4BEG[0]
  PIN Tile_X4Y0_N4BEG[10]
    DIRECTION OUTPUT ;
    USE SIGNAL ;
    ANTENNADIFFAREA 2.724000 ;
    PORT
      LAYER Metal2 ;
        RECT 987.160 78.980 987.560 79.380 ;
    END
  END Tile_X4Y0_N4BEG[10]
  PIN Tile_X4Y0_N4BEG[11]
    DIRECTION OUTPUT ;
    USE SIGNAL ;
    ANTENNADIFFAREA 2.724000 ;
    PORT
      LAYER Metal2 ;
        RECT 988.120 78.980 988.520 79.380 ;
    END
  END Tile_X4Y0_N4BEG[11]
  PIN Tile_X4Y0_N4BEG[12]
    DIRECTION OUTPUT ;
    USE SIGNAL ;
    ANTENNADIFFAREA 2.724000 ;
    PORT
      LAYER Metal2 ;
        RECT 989.080 78.980 989.480 79.380 ;
    END
  END Tile_X4Y0_N4BEG[12]
  PIN Tile_X4Y0_N4BEG[13]
    DIRECTION OUTPUT ;
    USE SIGNAL ;
    ANTENNADIFFAREA 2.724000 ;
    PORT
      LAYER Metal2 ;
        RECT 990.040 78.980 990.440 79.380 ;
    END
  END Tile_X4Y0_N4BEG[13]
  PIN Tile_X4Y0_N4BEG[14]
    DIRECTION OUTPUT ;
    USE SIGNAL ;
    ANTENNADIFFAREA 2.724000 ;
    PORT
      LAYER Metal2 ;
        RECT 991.000 78.980 991.400 79.380 ;
    END
  END Tile_X4Y0_N4BEG[14]
  PIN Tile_X4Y0_N4BEG[15]
    DIRECTION OUTPUT ;
    USE SIGNAL ;
    ANTENNADIFFAREA 2.724000 ;
    PORT
      LAYER Metal2 ;
        RECT 991.960 78.980 992.360 79.380 ;
    END
  END Tile_X4Y0_N4BEG[15]
  PIN Tile_X4Y0_N4BEG[1]
    DIRECTION OUTPUT ;
    USE SIGNAL ;
    ANTENNADIFFAREA 2.724000 ;
    PORT
      LAYER Metal2 ;
        RECT 978.520 78.980 978.920 79.380 ;
    END
  END Tile_X4Y0_N4BEG[1]
  PIN Tile_X4Y0_N4BEG[2]
    DIRECTION OUTPUT ;
    USE SIGNAL ;
    ANTENNADIFFAREA 2.724000 ;
    PORT
      LAYER Metal2 ;
        RECT 979.480 78.980 979.880 79.380 ;
    END
  END Tile_X4Y0_N4BEG[2]
  PIN Tile_X4Y0_N4BEG[3]
    DIRECTION OUTPUT ;
    USE SIGNAL ;
    ANTENNADIFFAREA 2.724000 ;
    PORT
      LAYER Metal2 ;
        RECT 980.440 78.980 980.840 79.380 ;
    END
  END Tile_X4Y0_N4BEG[3]
  PIN Tile_X4Y0_N4BEG[4]
    DIRECTION OUTPUT ;
    USE SIGNAL ;
    ANTENNADIFFAREA 2.724000 ;
    PORT
      LAYER Metal2 ;
        RECT 981.400 78.980 981.800 79.380 ;
    END
  END Tile_X4Y0_N4BEG[4]
  PIN Tile_X4Y0_N4BEG[5]
    DIRECTION OUTPUT ;
    USE SIGNAL ;
    ANTENNADIFFAREA 2.724000 ;
    PORT
      LAYER Metal2 ;
        RECT 982.360 78.980 982.760 79.380 ;
    END
  END Tile_X4Y0_N4BEG[5]
  PIN Tile_X4Y0_N4BEG[6]
    DIRECTION OUTPUT ;
    USE SIGNAL ;
    ANTENNADIFFAREA 2.724000 ;
    PORT
      LAYER Metal2 ;
        RECT 983.320 78.980 983.720 79.380 ;
    END
  END Tile_X4Y0_N4BEG[6]
  PIN Tile_X4Y0_N4BEG[7]
    DIRECTION OUTPUT ;
    USE SIGNAL ;
    ANTENNADIFFAREA 2.724000 ;
    PORT
      LAYER Metal2 ;
        RECT 984.280 78.980 984.680 79.380 ;
    END
  END Tile_X4Y0_N4BEG[7]
  PIN Tile_X4Y0_N4BEG[8]
    DIRECTION OUTPUT ;
    USE SIGNAL ;
    ANTENNADIFFAREA 2.724000 ;
    PORT
      LAYER Metal2 ;
        RECT 985.240 78.980 985.640 79.380 ;
    END
  END Tile_X4Y0_N4BEG[8]
  PIN Tile_X4Y0_N4BEG[9]
    DIRECTION OUTPUT ;
    USE SIGNAL ;
    ANTENNADIFFAREA 2.724000 ;
    PORT
      LAYER Metal2 ;
        RECT 986.200 78.980 986.600 79.380 ;
    END
  END Tile_X4Y0_N4BEG[9]
  PIN Tile_X4Y0_NN4BEG[0]
    DIRECTION OUTPUT ;
    USE SIGNAL ;
    ANTENNADIFFAREA 2.724000 ;
    PORT
      LAYER Metal2 ;
        RECT 1007.320 78.980 1007.720 79.380 ;
    END
  END Tile_X4Y0_NN4BEG[0]
  PIN Tile_X4Y0_NN4BEG[10]
    DIRECTION OUTPUT ;
    USE SIGNAL ;
    ANTENNADIFFAREA 2.724000 ;
    PORT
      LAYER Metal2 ;
        RECT 1016.920 78.980 1017.320 79.380 ;
    END
  END Tile_X4Y0_NN4BEG[10]
  PIN Tile_X4Y0_NN4BEG[11]
    DIRECTION OUTPUT ;
    USE SIGNAL ;
    ANTENNADIFFAREA 2.724000 ;
    PORT
      LAYER Metal2 ;
        RECT 1017.880 78.980 1018.280 79.380 ;
    END
  END Tile_X4Y0_NN4BEG[11]
  PIN Tile_X4Y0_NN4BEG[12]
    DIRECTION OUTPUT ;
    USE SIGNAL ;
    ANTENNADIFFAREA 2.724000 ;
    PORT
      LAYER Metal2 ;
        RECT 1018.840 78.980 1019.240 79.380 ;
    END
  END Tile_X4Y0_NN4BEG[12]
  PIN Tile_X4Y0_NN4BEG[13]
    DIRECTION OUTPUT ;
    USE SIGNAL ;
    ANTENNADIFFAREA 2.724000 ;
    PORT
      LAYER Metal2 ;
        RECT 1019.800 78.980 1020.200 79.380 ;
    END
  END Tile_X4Y0_NN4BEG[13]
  PIN Tile_X4Y0_NN4BEG[14]
    DIRECTION OUTPUT ;
    USE SIGNAL ;
    ANTENNADIFFAREA 2.724000 ;
    PORT
      LAYER Metal2 ;
        RECT 1020.760 78.980 1021.160 79.380 ;
    END
  END Tile_X4Y0_NN4BEG[14]
  PIN Tile_X4Y0_NN4BEG[15]
    DIRECTION OUTPUT ;
    USE SIGNAL ;
    ANTENNADIFFAREA 2.724000 ;
    PORT
      LAYER Metal2 ;
        RECT 1021.720 78.980 1022.120 79.380 ;
    END
  END Tile_X4Y0_NN4BEG[15]
  PIN Tile_X4Y0_NN4BEG[1]
    DIRECTION OUTPUT ;
    USE SIGNAL ;
    ANTENNADIFFAREA 2.724000 ;
    PORT
      LAYER Metal2 ;
        RECT 1008.280 78.980 1008.680 79.380 ;
    END
  END Tile_X4Y0_NN4BEG[1]
  PIN Tile_X4Y0_NN4BEG[2]
    DIRECTION OUTPUT ;
    USE SIGNAL ;
    ANTENNADIFFAREA 2.724000 ;
    PORT
      LAYER Metal2 ;
        RECT 1009.240 78.980 1009.640 79.380 ;
    END
  END Tile_X4Y0_NN4BEG[2]
  PIN Tile_X4Y0_NN4BEG[3]
    DIRECTION OUTPUT ;
    USE SIGNAL ;
    ANTENNADIFFAREA 2.724000 ;
    PORT
      LAYER Metal2 ;
        RECT 1010.200 78.980 1010.600 79.380 ;
    END
  END Tile_X4Y0_NN4BEG[3]
  PIN Tile_X4Y0_NN4BEG[4]
    DIRECTION OUTPUT ;
    USE SIGNAL ;
    ANTENNADIFFAREA 2.724000 ;
    PORT
      LAYER Metal2 ;
        RECT 1011.160 78.980 1011.560 79.380 ;
    END
  END Tile_X4Y0_NN4BEG[4]
  PIN Tile_X4Y0_NN4BEG[5]
    DIRECTION OUTPUT ;
    USE SIGNAL ;
    ANTENNADIFFAREA 2.724000 ;
    PORT
      LAYER Metal2 ;
        RECT 1012.120 78.980 1012.520 79.380 ;
    END
  END Tile_X4Y0_NN4BEG[5]
  PIN Tile_X4Y0_NN4BEG[6]
    DIRECTION OUTPUT ;
    USE SIGNAL ;
    ANTENNADIFFAREA 2.724000 ;
    PORT
      LAYER Metal2 ;
        RECT 1013.080 78.980 1013.480 79.380 ;
    END
  END Tile_X4Y0_NN4BEG[6]
  PIN Tile_X4Y0_NN4BEG[7]
    DIRECTION OUTPUT ;
    USE SIGNAL ;
    ANTENNADIFFAREA 2.724000 ;
    PORT
      LAYER Metal2 ;
        RECT 1014.040 78.980 1014.440 79.380 ;
    END
  END Tile_X4Y0_NN4BEG[7]
  PIN Tile_X4Y0_NN4BEG[8]
    DIRECTION OUTPUT ;
    USE SIGNAL ;
    ANTENNADIFFAREA 2.724000 ;
    PORT
      LAYER Metal2 ;
        RECT 1015.000 78.980 1015.400 79.380 ;
    END
  END Tile_X4Y0_NN4BEG[8]
  PIN Tile_X4Y0_NN4BEG[9]
    DIRECTION OUTPUT ;
    USE SIGNAL ;
    ANTENNADIFFAREA 2.724000 ;
    PORT
      LAYER Metal2 ;
        RECT 1015.960 78.980 1016.360 79.380 ;
    END
  END Tile_X4Y0_NN4BEG[9]
  PIN Tile_X4Y0_S1END[0]
    DIRECTION INPUT ;
    USE SIGNAL ;
    ANTENNAGATEAREA 0.393900 ;
    PORT
      LAYER Metal2 ;
        RECT 1030.360 78.980 1030.760 79.380 ;
    END
  END Tile_X4Y0_S1END[0]
  PIN Tile_X4Y0_S1END[1]
    DIRECTION INPUT ;
    USE SIGNAL ;
    ANTENNAGATEAREA 0.393900 ;
    PORT
      LAYER Metal2 ;
        RECT 1032.280 78.980 1032.680 79.380 ;
    END
  END Tile_X4Y0_S1END[1]
  PIN Tile_X4Y0_S1END[2]
    DIRECTION INPUT ;
    USE SIGNAL ;
    ANTENNAGATEAREA 0.393900 ;
    PORT
      LAYER Metal2 ;
        RECT 1034.200 78.980 1034.600 79.380 ;
    END
  END Tile_X4Y0_S1END[2]
  PIN Tile_X4Y0_S1END[3]
    DIRECTION INPUT ;
    USE SIGNAL ;
    ANTENNAGATEAREA 0.180700 ;
    ANTENNADIFFAREA 2.015400 ;
    PORT
      LAYER Metal2 ;
        RECT 1036.120 78.980 1036.520 79.380 ;
    END
  END Tile_X4Y0_S1END[3]
  PIN Tile_X4Y0_S2END[0]
    DIRECTION INPUT ;
    USE SIGNAL ;
    ANTENNAGATEAREA 0.180700 ;
    PORT
      LAYER Metal2 ;
        RECT 1056.280 78.980 1056.680 79.380 ;
    END
  END Tile_X4Y0_S2END[0]
  PIN Tile_X4Y0_S2END[1]
    DIRECTION INPUT ;
    USE SIGNAL ;
    ANTENNAGATEAREA 0.180700 ;
    PORT
      LAYER Metal2 ;
        RECT 1057.240 78.980 1057.640 79.380 ;
    END
  END Tile_X4Y0_S2END[1]
  PIN Tile_X4Y0_S2END[2]
    DIRECTION INPUT ;
    USE SIGNAL ;
    ANTENNAGATEAREA 0.180700 ;
    PORT
      LAYER Metal2 ;
        RECT 1058.200 78.980 1058.600 79.380 ;
    END
  END Tile_X4Y0_S2END[2]
  PIN Tile_X4Y0_S2END[3]
    DIRECTION INPUT ;
    USE SIGNAL ;
    ANTENNAGATEAREA 0.180700 ;
    PORT
      LAYER Metal2 ;
        RECT 1059.160 78.980 1059.560 79.380 ;
    END
  END Tile_X4Y0_S2END[3]
  PIN Tile_X4Y0_S2END[4]
    DIRECTION INPUT ;
    USE SIGNAL ;
    ANTENNAGATEAREA 0.180700 ;
    PORT
      LAYER Metal2 ;
        RECT 1060.120 78.980 1060.520 79.380 ;
    END
  END Tile_X4Y0_S2END[4]
  PIN Tile_X4Y0_S2END[5]
    DIRECTION INPUT ;
    USE SIGNAL ;
    ANTENNAGATEAREA 0.393900 ;
    PORT
      LAYER Metal2 ;
        RECT 1061.080 78.980 1061.480 79.380 ;
    END
  END Tile_X4Y0_S2END[5]
  PIN Tile_X4Y0_S2END[6]
    DIRECTION INPUT ;
    USE SIGNAL ;
    ANTENNAGATEAREA 0.393900 ;
    PORT
      LAYER Metal2 ;
        RECT 1062.040 78.980 1062.440 79.380 ;
    END
  END Tile_X4Y0_S2END[6]
  PIN Tile_X4Y0_S2END[7]
    DIRECTION INPUT ;
    USE SIGNAL ;
    ANTENNAGATEAREA 0.393900 ;
    PORT
      LAYER Metal2 ;
        RECT 1063.000 78.980 1063.400 79.380 ;
    END
  END Tile_X4Y0_S2END[7]
  PIN Tile_X4Y0_S2MID[0]
    DIRECTION INPUT ;
    USE SIGNAL ;
    ANTENNAGATEAREA 0.393900 ;
    PORT
      LAYER Metal2 ;
        RECT 1038.040 78.980 1038.440 79.380 ;
    END
  END Tile_X4Y0_S2MID[0]
  PIN Tile_X4Y0_S2MID[1]
    DIRECTION INPUT ;
    USE SIGNAL ;
    ANTENNAGATEAREA 0.393900 ;
    PORT
      LAYER Metal2 ;
        RECT 1039.960 78.980 1040.360 79.380 ;
    END
  END Tile_X4Y0_S2MID[1]
  PIN Tile_X4Y0_S2MID[2]
    DIRECTION INPUT ;
    USE SIGNAL ;
    ANTENNAGATEAREA 0.393900 ;
    PORT
      LAYER Metal2 ;
        RECT 1041.880 78.980 1042.280 79.380 ;
    END
  END Tile_X4Y0_S2MID[2]
  PIN Tile_X4Y0_S2MID[3]
    DIRECTION INPUT ;
    USE SIGNAL ;
    ANTENNAGATEAREA 0.180700 ;
    PORT
      LAYER Metal2 ;
        RECT 1043.800 78.980 1044.200 79.380 ;
    END
  END Tile_X4Y0_S2MID[3]
  PIN Tile_X4Y0_S2MID[4]
    DIRECTION INPUT ;
    USE SIGNAL ;
    ANTENNAGATEAREA 0.180700 ;
    ANTENNADIFFAREA 2.015400 ;
    PORT
      LAYER Metal2 ;
        RECT 1045.720 78.980 1046.120 79.380 ;
    END
  END Tile_X4Y0_S2MID[4]
  PIN Tile_X4Y0_S2MID[5]
    DIRECTION INPUT ;
    USE SIGNAL ;
    ANTENNAGATEAREA 0.393900 ;
    PORT
      LAYER Metal2 ;
        RECT 1047.640 78.980 1048.040 79.380 ;
    END
  END Tile_X4Y0_S2MID[5]
  PIN Tile_X4Y0_S2MID[6]
    DIRECTION INPUT ;
    USE SIGNAL ;
    ANTENNAGATEAREA 0.393900 ;
    PORT
      LAYER Metal2 ;
        RECT 1049.560 78.980 1049.960 79.380 ;
    END
  END Tile_X4Y0_S2MID[6]
  PIN Tile_X4Y0_S2MID[7]
    DIRECTION INPUT ;
    USE SIGNAL ;
    ANTENNAGATEAREA 0.393900 ;
    ANTENNADIFFAREA 8.061600 ;
    PORT
      LAYER Metal2 ;
        RECT 1051.480 78.980 1051.880 79.380 ;
    END
  END Tile_X4Y0_S2MID[7]
  PIN Tile_X4Y0_S4END[0]
    DIRECTION INPUT ;
    USE SIGNAL ;
    ANTENNAGATEAREA 0.180700 ;
    PORT
      LAYER Metal2 ;
        RECT 1074.520 78.980 1074.920 79.380 ;
    END
  END Tile_X4Y0_S4END[0]
  PIN Tile_X4Y0_S4END[10]
    DIRECTION INPUT ;
    USE SIGNAL ;
    ANTENNAGATEAREA 0.180700 ;
    PORT
      LAYER Metal2 ;
        RECT 1084.120 78.980 1084.520 79.380 ;
    END
  END Tile_X4Y0_S4END[10]
  PIN Tile_X4Y0_S4END[11]
    DIRECTION INPUT ;
    USE SIGNAL ;
    ANTENNAGATEAREA 0.180700 ;
    PORT
      LAYER Metal2 ;
        RECT 1085.080 78.980 1085.480 79.380 ;
    END
  END Tile_X4Y0_S4END[11]
  PIN Tile_X4Y0_S4END[12]
    DIRECTION INPUT ;
    USE SIGNAL ;
    ANTENNAGATEAREA 0.180700 ;
    PORT
      LAYER Metal2 ;
        RECT 1086.040 78.980 1086.440 79.380 ;
    END
  END Tile_X4Y0_S4END[12]
  PIN Tile_X4Y0_S4END[13]
    DIRECTION INPUT ;
    USE SIGNAL ;
    ANTENNAGATEAREA 0.180700 ;
    PORT
      LAYER Metal2 ;
        RECT 1087.000 78.980 1087.400 79.380 ;
    END
  END Tile_X4Y0_S4END[13]
  PIN Tile_X4Y0_S4END[14]
    DIRECTION INPUT ;
    USE SIGNAL ;
    ANTENNAGATEAREA 0.180700 ;
    PORT
      LAYER Metal2 ;
        RECT 1087.960 78.980 1088.360 79.380 ;
    END
  END Tile_X4Y0_S4END[14]
  PIN Tile_X4Y0_S4END[15]
    DIRECTION INPUT ;
    USE SIGNAL ;
    ANTENNAGATEAREA 0.180700 ;
    PORT
      LAYER Metal2 ;
        RECT 1088.920 78.980 1089.320 79.380 ;
    END
  END Tile_X4Y0_S4END[15]
  PIN Tile_X4Y0_S4END[1]
    DIRECTION INPUT ;
    USE SIGNAL ;
    ANTENNAGATEAREA 0.180700 ;
    PORT
      LAYER Metal2 ;
        RECT 1075.480 78.980 1075.880 79.380 ;
    END
  END Tile_X4Y0_S4END[1]
  PIN Tile_X4Y0_S4END[2]
    DIRECTION INPUT ;
    USE SIGNAL ;
    ANTENNAGATEAREA 0.180700 ;
    PORT
      LAYER Metal2 ;
        RECT 1076.440 78.980 1076.840 79.380 ;
    END
  END Tile_X4Y0_S4END[2]
  PIN Tile_X4Y0_S4END[3]
    DIRECTION INPUT ;
    USE SIGNAL ;
    ANTENNAGATEAREA 0.180700 ;
    PORT
      LAYER Metal2 ;
        RECT 1077.400 78.980 1077.800 79.380 ;
    END
  END Tile_X4Y0_S4END[3]
  PIN Tile_X4Y0_S4END[4]
    DIRECTION INPUT ;
    USE SIGNAL ;
    ANTENNAGATEAREA 0.180700 ;
    PORT
      LAYER Metal2 ;
        RECT 1078.360 78.980 1078.760 79.380 ;
    END
  END Tile_X4Y0_S4END[4]
  PIN Tile_X4Y0_S4END[5]
    DIRECTION INPUT ;
    USE SIGNAL ;
    ANTENNAGATEAREA 0.180700 ;
    PORT
      LAYER Metal2 ;
        RECT 1079.320 78.980 1079.720 79.380 ;
    END
  END Tile_X4Y0_S4END[5]
  PIN Tile_X4Y0_S4END[6]
    DIRECTION INPUT ;
    USE SIGNAL ;
    ANTENNAGATEAREA 0.180700 ;
    PORT
      LAYER Metal2 ;
        RECT 1080.280 78.980 1080.680 79.380 ;
    END
  END Tile_X4Y0_S4END[6]
  PIN Tile_X4Y0_S4END[7]
    DIRECTION INPUT ;
    USE SIGNAL ;
    ANTENNAGATEAREA 0.180700 ;
    PORT
      LAYER Metal2 ;
        RECT 1081.240 78.980 1081.640 79.380 ;
    END
  END Tile_X4Y0_S4END[7]
  PIN Tile_X4Y0_S4END[8]
    DIRECTION INPUT ;
    USE SIGNAL ;
    ANTENNAGATEAREA 0.180700 ;
    PORT
      LAYER Metal2 ;
        RECT 1082.200 78.980 1082.600 79.380 ;
    END
  END Tile_X4Y0_S4END[8]
  PIN Tile_X4Y0_S4END[9]
    DIRECTION INPUT ;
    USE SIGNAL ;
    ANTENNAGATEAREA 0.180700 ;
    PORT
      LAYER Metal2 ;
        RECT 1083.160 78.980 1083.560 79.380 ;
    END
  END Tile_X4Y0_S4END[9]
  PIN Tile_X4Y0_SS4END[0]
    DIRECTION INPUT ;
    USE SIGNAL ;
    ANTENNAGATEAREA 0.180700 ;
    PORT
      LAYER Metal2 ;
        RECT 1104.280 78.980 1104.680 79.380 ;
    END
  END Tile_X4Y0_SS4END[0]
  PIN Tile_X4Y0_SS4END[10]
    DIRECTION INPUT ;
    USE SIGNAL ;
    ANTENNAGATEAREA 0.180700 ;
    PORT
      LAYER Metal2 ;
        RECT 1113.880 78.980 1114.280 79.380 ;
    END
  END Tile_X4Y0_SS4END[10]
  PIN Tile_X4Y0_SS4END[11]
    DIRECTION INPUT ;
    USE SIGNAL ;
    ANTENNAGATEAREA 0.180700 ;
    PORT
      LAYER Metal2 ;
        RECT 1114.840 78.980 1115.240 79.380 ;
    END
  END Tile_X4Y0_SS4END[11]
  PIN Tile_X4Y0_SS4END[12]
    DIRECTION INPUT ;
    USE SIGNAL ;
    ANTENNAGATEAREA 0.180700 ;
    PORT
      LAYER Metal2 ;
        RECT 1115.800 78.980 1116.200 79.380 ;
    END
  END Tile_X4Y0_SS4END[12]
  PIN Tile_X4Y0_SS4END[13]
    DIRECTION INPUT ;
    USE SIGNAL ;
    ANTENNAGATEAREA 0.180700 ;
    PORT
      LAYER Metal2 ;
        RECT 1116.760 78.980 1117.160 79.380 ;
    END
  END Tile_X4Y0_SS4END[13]
  PIN Tile_X4Y0_SS4END[14]
    DIRECTION INPUT ;
    USE SIGNAL ;
    ANTENNAGATEAREA 0.180700 ;
    PORT
      LAYER Metal2 ;
        RECT 1117.720 78.980 1118.120 79.380 ;
    END
  END Tile_X4Y0_SS4END[14]
  PIN Tile_X4Y0_SS4END[15]
    DIRECTION INPUT ;
    USE SIGNAL ;
    ANTENNAGATEAREA 0.180700 ;
    PORT
      LAYER Metal2 ;
        RECT 1118.680 78.980 1119.080 79.380 ;
    END
  END Tile_X4Y0_SS4END[15]
  PIN Tile_X4Y0_SS4END[1]
    DIRECTION INPUT ;
    USE SIGNAL ;
    ANTENNAGATEAREA 0.180700 ;
    PORT
      LAYER Metal2 ;
        RECT 1105.240 78.980 1105.640 79.380 ;
    END
  END Tile_X4Y0_SS4END[1]
  PIN Tile_X4Y0_SS4END[2]
    DIRECTION INPUT ;
    USE SIGNAL ;
    ANTENNAGATEAREA 0.180700 ;
    PORT
      LAYER Metal2 ;
        RECT 1106.200 78.980 1106.600 79.380 ;
    END
  END Tile_X4Y0_SS4END[2]
  PIN Tile_X4Y0_SS4END[3]
    DIRECTION INPUT ;
    USE SIGNAL ;
    ANTENNAGATEAREA 0.180700 ;
    PORT
      LAYER Metal2 ;
        RECT 1107.160 78.980 1107.560 79.380 ;
    END
  END Tile_X4Y0_SS4END[3]
  PIN Tile_X4Y0_SS4END[4]
    DIRECTION INPUT ;
    USE SIGNAL ;
    ANTENNAGATEAREA 0.180700 ;
    PORT
      LAYER Metal2 ;
        RECT 1108.120 78.980 1108.520 79.380 ;
    END
  END Tile_X4Y0_SS4END[4]
  PIN Tile_X4Y0_SS4END[5]
    DIRECTION INPUT ;
    USE SIGNAL ;
    ANTENNAGATEAREA 0.180700 ;
    PORT
      LAYER Metal2 ;
        RECT 1109.080 78.980 1109.480 79.380 ;
    END
  END Tile_X4Y0_SS4END[5]
  PIN Tile_X4Y0_SS4END[6]
    DIRECTION INPUT ;
    USE SIGNAL ;
    ANTENNAGATEAREA 0.180700 ;
    PORT
      LAYER Metal2 ;
        RECT 1110.040 78.980 1110.440 79.380 ;
    END
  END Tile_X4Y0_SS4END[6]
  PIN Tile_X4Y0_SS4END[7]
    DIRECTION INPUT ;
    USE SIGNAL ;
    ANTENNAGATEAREA 0.180700 ;
    PORT
      LAYER Metal2 ;
        RECT 1111.000 78.980 1111.400 79.380 ;
    END
  END Tile_X4Y0_SS4END[7]
  PIN Tile_X4Y0_SS4END[8]
    DIRECTION INPUT ;
    USE SIGNAL ;
    ANTENNAGATEAREA 0.180700 ;
    PORT
      LAYER Metal2 ;
        RECT 1111.960 78.980 1112.360 79.380 ;
    END
  END Tile_X4Y0_SS4END[8]
  PIN Tile_X4Y0_SS4END[9]
    DIRECTION INPUT ;
    USE SIGNAL ;
    ANTENNAGATEAREA 0.180700 ;
    PORT
      LAYER Metal2 ;
        RECT 1112.920 78.980 1113.320 79.380 ;
    END
  END Tile_X4Y0_SS4END[9]
  PIN Tile_X4Y0_UserCLKo
    DIRECTION OUTPUT ;
    USE SIGNAL ;
    ANTENNADIFFAREA 2.724000 ;
    PORT
      LAYER Metal3 ;
        RECT 1166.000 1.900 1166.400 2.300 ;
    END
  END Tile_X4Y0_UserCLKo
  PIN VGND
    DIRECTION INOUT ;
    USE GROUND ;
    PORT
      LAYER Metal4 ;
        RECT 15.380 0.000 16.380 79.380 ;
    END
    PORT
      LAYER Metal4 ;
        RECT 65.380 0.000 66.380 79.380 ;
    END
    PORT
      LAYER Metal4 ;
        RECT 115.380 0.000 116.380 79.380 ;
    END
    PORT
      LAYER Metal4 ;
        RECT 165.380 0.000 166.380 79.380 ;
    END
    PORT
      LAYER Metal4 ;
        RECT 215.380 0.000 216.380 79.380 ;
    END
    PORT
      LAYER Metal4 ;
        RECT 248.660 0.000 249.660 79.380 ;
    END
    PORT
      LAYER Metal4 ;
        RECT 298.660 0.000 299.660 79.380 ;
    END
    PORT
      LAYER Metal4 ;
        RECT 348.660 0.000 349.660 79.380 ;
    END
    PORT
      LAYER Metal4 ;
        RECT 398.660 0.000 399.660 79.380 ;
    END
    PORT
      LAYER Metal4 ;
        RECT 448.660 0.000 449.660 79.380 ;
    END
    PORT
      LAYER Metal4 ;
        RECT 481.940 0.000 482.940 79.380 ;
    END
    PORT
      LAYER Metal4 ;
        RECT 531.940 0.000 532.940 79.380 ;
    END
    PORT
      LAYER Metal4 ;
        RECT 581.940 0.000 582.940 79.380 ;
    END
    PORT
      LAYER Metal4 ;
        RECT 631.940 0.000 632.940 79.380 ;
    END
    PORT
      LAYER Metal4 ;
        RECT 681.940 0.000 682.940 79.380 ;
    END
    PORT
      LAYER Metal4 ;
        RECT 715.220 0.000 716.220 79.380 ;
    END
    PORT
      LAYER Metal4 ;
        RECT 765.220 0.000 766.220 79.380 ;
    END
    PORT
      LAYER Metal4 ;
        RECT 815.220 0.000 816.220 79.380 ;
    END
    PORT
      LAYER Metal4 ;
        RECT 865.220 0.000 866.220 79.380 ;
    END
    PORT
      LAYER Metal4 ;
        RECT 915.220 0.000 916.220 79.380 ;
    END
    PORT
      LAYER Metal4 ;
        RECT 948.500 0.000 949.500 79.380 ;
    END
    PORT
      LAYER Metal4 ;
        RECT 998.500 0.000 999.500 79.380 ;
    END
    PORT
      LAYER Metal4 ;
        RECT 1048.500 0.000 1049.500 79.380 ;
    END
    PORT
      LAYER Metal4 ;
        RECT 1098.500 0.000 1099.500 79.380 ;
    END
    PORT
      LAYER Metal4 ;
        RECT 1148.500 0.000 1149.500 79.380 ;
    END
  END VGND
  PIN VPWR
    DIRECTION INOUT ;
    USE POWER ;
    PORT
      LAYER Metal4 ;
        RECT 12.380 0.000 13.380 79.380 ;
    END
    PORT
      LAYER Metal4 ;
        RECT 62.380 0.000 63.380 79.380 ;
    END
    PORT
      LAYER Metal4 ;
        RECT 112.380 0.000 113.380 79.380 ;
    END
    PORT
      LAYER Metal4 ;
        RECT 162.380 0.000 163.380 79.380 ;
    END
    PORT
      LAYER Metal4 ;
        RECT 212.380 0.000 213.380 79.380 ;
    END
    PORT
      LAYER Metal4 ;
        RECT 245.660 0.000 246.660 79.380 ;
    END
    PORT
      LAYER Metal4 ;
        RECT 295.660 0.000 296.660 79.380 ;
    END
    PORT
      LAYER Metal4 ;
        RECT 345.660 0.000 346.660 79.380 ;
    END
    PORT
      LAYER Metal4 ;
        RECT 395.660 0.000 396.660 79.380 ;
    END
    PORT
      LAYER Metal4 ;
        RECT 445.660 0.000 446.660 79.380 ;
    END
    PORT
      LAYER Metal4 ;
        RECT 478.940 0.000 479.940 79.380 ;
    END
    PORT
      LAYER Metal4 ;
        RECT 528.940 0.000 529.940 79.380 ;
    END
    PORT
      LAYER Metal4 ;
        RECT 578.940 0.000 579.940 79.380 ;
    END
    PORT
      LAYER Metal4 ;
        RECT 628.940 0.000 629.940 79.380 ;
    END
    PORT
      LAYER Metal4 ;
        RECT 678.940 0.000 679.940 79.380 ;
    END
    PORT
      LAYER Metal4 ;
        RECT 712.220 0.000 713.220 79.380 ;
    END
    PORT
      LAYER Metal4 ;
        RECT 762.220 0.000 763.220 79.380 ;
    END
    PORT
      LAYER Metal4 ;
        RECT 812.220 0.000 813.220 79.380 ;
    END
    PORT
      LAYER Metal4 ;
        RECT 862.220 0.000 863.220 79.380 ;
    END
    PORT
      LAYER Metal4 ;
        RECT 912.220 0.000 913.220 79.380 ;
    END
    PORT
      LAYER Metal4 ;
        RECT 945.500 0.000 946.500 79.380 ;
    END
    PORT
      LAYER Metal4 ;
        RECT 995.500 0.000 996.500 79.380 ;
    END
    PORT
      LAYER Metal4 ;
        RECT 1045.500 0.000 1046.500 79.380 ;
    END
    PORT
      LAYER Metal4 ;
        RECT 1095.500 0.000 1096.500 79.380 ;
    END
    PORT
      LAYER Metal4 ;
        RECT 1145.500 0.000 1146.500 79.380 ;
    END
  END VPWR
  OBS
      LAYER GatPoly ;
        RECT 2.880 3.630 1163.520 75.750 ;
      LAYER Metal1 ;
        RECT 2.880 3.560 1163.520 75.820 ;
      LAYER Metal2 ;
        RECT 0.375 78.770 1.030 79.105 ;
        RECT 1.850 78.770 2.950 79.105 ;
        RECT 3.770 78.770 4.870 79.105 ;
        RECT 5.690 78.770 6.790 79.105 ;
        RECT 7.610 78.770 11.590 79.105 ;
        RECT 12.410 78.770 12.550 79.105 ;
        RECT 13.370 78.770 13.510 79.105 ;
        RECT 14.330 78.770 14.470 79.105 ;
        RECT 15.290 78.770 15.430 79.105 ;
        RECT 16.250 78.770 16.390 79.105 ;
        RECT 17.210 78.770 17.350 79.105 ;
        RECT 18.170 78.770 18.310 79.105 ;
        RECT 19.130 78.770 25.990 79.105 ;
        RECT 26.810 78.770 26.950 79.105 ;
        RECT 27.770 78.770 27.910 79.105 ;
        RECT 28.730 78.770 28.870 79.105 ;
        RECT 29.690 78.770 29.830 79.105 ;
        RECT 30.650 78.770 30.790 79.105 ;
        RECT 31.610 78.770 31.750 79.105 ;
        RECT 32.570 78.770 32.710 79.105 ;
        RECT 33.530 78.770 44.230 79.105 ;
        RECT 45.050 78.770 45.190 79.105 ;
        RECT 46.010 78.770 46.150 79.105 ;
        RECT 46.970 78.770 47.110 79.105 ;
        RECT 47.930 78.770 48.070 79.105 ;
        RECT 48.890 78.770 49.030 79.105 ;
        RECT 49.850 78.770 49.990 79.105 ;
        RECT 50.810 78.770 50.950 79.105 ;
        RECT 51.770 78.770 51.910 79.105 ;
        RECT 52.730 78.770 52.870 79.105 ;
        RECT 53.690 78.770 53.830 79.105 ;
        RECT 54.650 78.770 54.790 79.105 ;
        RECT 55.610 78.770 55.750 79.105 ;
        RECT 56.570 78.770 56.710 79.105 ;
        RECT 57.530 78.770 57.670 79.105 ;
        RECT 58.490 78.770 58.630 79.105 ;
        RECT 59.450 78.770 73.990 79.105 ;
        RECT 74.810 78.770 74.950 79.105 ;
        RECT 75.770 78.770 75.910 79.105 ;
        RECT 76.730 78.770 76.870 79.105 ;
        RECT 77.690 78.770 77.830 79.105 ;
        RECT 78.650 78.770 78.790 79.105 ;
        RECT 79.610 78.770 79.750 79.105 ;
        RECT 80.570 78.770 80.710 79.105 ;
        RECT 81.530 78.770 81.670 79.105 ;
        RECT 82.490 78.770 82.630 79.105 ;
        RECT 83.450 78.770 83.590 79.105 ;
        RECT 84.410 78.770 84.550 79.105 ;
        RECT 85.370 78.770 85.510 79.105 ;
        RECT 86.330 78.770 86.470 79.105 ;
        RECT 87.290 78.770 87.430 79.105 ;
        RECT 88.250 78.770 88.390 79.105 ;
        RECT 89.210 78.770 97.030 79.105 ;
        RECT 97.850 78.770 98.950 79.105 ;
        RECT 99.770 78.770 100.870 79.105 ;
        RECT 101.690 78.770 102.790 79.105 ;
        RECT 103.610 78.770 104.710 79.105 ;
        RECT 105.530 78.770 106.630 79.105 ;
        RECT 107.450 78.770 108.550 79.105 ;
        RECT 109.370 78.770 110.470 79.105 ;
        RECT 111.290 78.770 112.390 79.105 ;
        RECT 113.210 78.770 114.310 79.105 ;
        RECT 115.130 78.770 116.230 79.105 ;
        RECT 117.050 78.770 118.150 79.105 ;
        RECT 118.970 78.770 122.950 79.105 ;
        RECT 123.770 78.770 123.910 79.105 ;
        RECT 124.730 78.770 124.870 79.105 ;
        RECT 125.690 78.770 125.830 79.105 ;
        RECT 126.650 78.770 126.790 79.105 ;
        RECT 127.610 78.770 127.750 79.105 ;
        RECT 128.570 78.770 128.710 79.105 ;
        RECT 129.530 78.770 129.670 79.105 ;
        RECT 130.490 78.770 141.190 79.105 ;
        RECT 142.010 78.770 142.150 79.105 ;
        RECT 142.970 78.770 143.110 79.105 ;
        RECT 143.930 78.770 144.070 79.105 ;
        RECT 144.890 78.770 145.030 79.105 ;
        RECT 145.850 78.770 145.990 79.105 ;
        RECT 146.810 78.770 146.950 79.105 ;
        RECT 147.770 78.770 147.910 79.105 ;
        RECT 148.730 78.770 148.870 79.105 ;
        RECT 149.690 78.770 149.830 79.105 ;
        RECT 150.650 78.770 150.790 79.105 ;
        RECT 151.610 78.770 151.750 79.105 ;
        RECT 152.570 78.770 152.710 79.105 ;
        RECT 153.530 78.770 153.670 79.105 ;
        RECT 154.490 78.770 154.630 79.105 ;
        RECT 155.450 78.770 155.590 79.105 ;
        RECT 156.410 78.770 170.950 79.105 ;
        RECT 171.770 78.770 171.910 79.105 ;
        RECT 172.730 78.770 172.870 79.105 ;
        RECT 173.690 78.770 173.830 79.105 ;
        RECT 174.650 78.770 174.790 79.105 ;
        RECT 175.610 78.770 175.750 79.105 ;
        RECT 176.570 78.770 176.710 79.105 ;
        RECT 177.530 78.770 177.670 79.105 ;
        RECT 178.490 78.770 178.630 79.105 ;
        RECT 179.450 78.770 179.590 79.105 ;
        RECT 180.410 78.770 180.550 79.105 ;
        RECT 181.370 78.770 181.510 79.105 ;
        RECT 182.330 78.770 182.470 79.105 ;
        RECT 183.290 78.770 183.430 79.105 ;
        RECT 184.250 78.770 184.390 79.105 ;
        RECT 185.210 78.770 185.350 79.105 ;
        RECT 186.170 78.770 193.990 79.105 ;
        RECT 194.810 78.770 204.550 79.105 ;
        RECT 205.370 78.770 205.510 79.105 ;
        RECT 206.330 78.770 206.470 79.105 ;
        RECT 207.290 78.770 207.430 79.105 ;
        RECT 208.250 78.770 208.390 79.105 ;
        RECT 209.210 78.770 209.350 79.105 ;
        RECT 210.170 78.770 210.310 79.105 ;
        RECT 211.130 78.770 211.270 79.105 ;
        RECT 212.090 78.770 212.230 79.105 ;
        RECT 213.050 78.770 213.190 79.105 ;
        RECT 214.010 78.770 214.150 79.105 ;
        RECT 214.970 78.770 215.110 79.105 ;
        RECT 215.930 78.770 216.070 79.105 ;
        RECT 216.890 78.770 217.030 79.105 ;
        RECT 217.850 78.770 217.990 79.105 ;
        RECT 218.810 78.770 218.950 79.105 ;
        RECT 219.770 78.770 219.910 79.105 ;
        RECT 220.730 78.770 220.870 79.105 ;
        RECT 221.690 78.770 221.830 79.105 ;
        RECT 222.650 78.770 222.790 79.105 ;
        RECT 223.610 78.770 234.310 79.105 ;
        RECT 235.130 78.770 236.230 79.105 ;
        RECT 237.050 78.770 238.150 79.105 ;
        RECT 238.970 78.770 240.070 79.105 ;
        RECT 240.890 78.770 244.870 79.105 ;
        RECT 245.690 78.770 245.830 79.105 ;
        RECT 246.650 78.770 246.790 79.105 ;
        RECT 247.610 78.770 247.750 79.105 ;
        RECT 248.570 78.770 248.710 79.105 ;
        RECT 249.530 78.770 249.670 79.105 ;
        RECT 250.490 78.770 250.630 79.105 ;
        RECT 251.450 78.770 251.590 79.105 ;
        RECT 252.410 78.770 259.270 79.105 ;
        RECT 260.090 78.770 260.230 79.105 ;
        RECT 261.050 78.770 261.190 79.105 ;
        RECT 262.010 78.770 262.150 79.105 ;
        RECT 262.970 78.770 263.110 79.105 ;
        RECT 263.930 78.770 264.070 79.105 ;
        RECT 264.890 78.770 265.030 79.105 ;
        RECT 265.850 78.770 265.990 79.105 ;
        RECT 266.810 78.770 277.510 79.105 ;
        RECT 278.330 78.770 278.470 79.105 ;
        RECT 279.290 78.770 279.430 79.105 ;
        RECT 280.250 78.770 280.390 79.105 ;
        RECT 281.210 78.770 281.350 79.105 ;
        RECT 282.170 78.770 282.310 79.105 ;
        RECT 283.130 78.770 283.270 79.105 ;
        RECT 284.090 78.770 284.230 79.105 ;
        RECT 285.050 78.770 285.190 79.105 ;
        RECT 286.010 78.770 286.150 79.105 ;
        RECT 286.970 78.770 287.110 79.105 ;
        RECT 287.930 78.770 288.070 79.105 ;
        RECT 288.890 78.770 289.030 79.105 ;
        RECT 289.850 78.770 289.990 79.105 ;
        RECT 290.810 78.770 290.950 79.105 ;
        RECT 291.770 78.770 291.910 79.105 ;
        RECT 292.730 78.770 307.270 79.105 ;
        RECT 308.090 78.770 308.230 79.105 ;
        RECT 309.050 78.770 309.190 79.105 ;
        RECT 310.010 78.770 310.150 79.105 ;
        RECT 310.970 78.770 311.110 79.105 ;
        RECT 311.930 78.770 312.070 79.105 ;
        RECT 312.890 78.770 313.030 79.105 ;
        RECT 313.850 78.770 313.990 79.105 ;
        RECT 314.810 78.770 314.950 79.105 ;
        RECT 315.770 78.770 315.910 79.105 ;
        RECT 316.730 78.770 316.870 79.105 ;
        RECT 317.690 78.770 317.830 79.105 ;
        RECT 318.650 78.770 318.790 79.105 ;
        RECT 319.610 78.770 319.750 79.105 ;
        RECT 320.570 78.770 320.710 79.105 ;
        RECT 321.530 78.770 321.670 79.105 ;
        RECT 322.490 78.770 330.310 79.105 ;
        RECT 331.130 78.770 332.230 79.105 ;
        RECT 333.050 78.770 334.150 79.105 ;
        RECT 334.970 78.770 336.070 79.105 ;
        RECT 336.890 78.770 337.990 79.105 ;
        RECT 338.810 78.770 339.910 79.105 ;
        RECT 340.730 78.770 341.830 79.105 ;
        RECT 342.650 78.770 343.750 79.105 ;
        RECT 344.570 78.770 345.670 79.105 ;
        RECT 346.490 78.770 347.590 79.105 ;
        RECT 348.410 78.770 349.510 79.105 ;
        RECT 350.330 78.770 351.430 79.105 ;
        RECT 352.250 78.770 356.230 79.105 ;
        RECT 357.050 78.770 357.190 79.105 ;
        RECT 358.010 78.770 358.150 79.105 ;
        RECT 358.970 78.770 359.110 79.105 ;
        RECT 359.930 78.770 360.070 79.105 ;
        RECT 360.890 78.770 361.030 79.105 ;
        RECT 361.850 78.770 361.990 79.105 ;
        RECT 362.810 78.770 362.950 79.105 ;
        RECT 363.770 78.770 374.470 79.105 ;
        RECT 375.290 78.770 375.430 79.105 ;
        RECT 376.250 78.770 376.390 79.105 ;
        RECT 377.210 78.770 377.350 79.105 ;
        RECT 378.170 78.770 378.310 79.105 ;
        RECT 379.130 78.770 379.270 79.105 ;
        RECT 380.090 78.770 380.230 79.105 ;
        RECT 381.050 78.770 381.190 79.105 ;
        RECT 382.010 78.770 382.150 79.105 ;
        RECT 382.970 78.770 383.110 79.105 ;
        RECT 383.930 78.770 384.070 79.105 ;
        RECT 384.890 78.770 385.030 79.105 ;
        RECT 385.850 78.770 385.990 79.105 ;
        RECT 386.810 78.770 386.950 79.105 ;
        RECT 387.770 78.770 387.910 79.105 ;
        RECT 388.730 78.770 388.870 79.105 ;
        RECT 389.690 78.770 404.230 79.105 ;
        RECT 405.050 78.770 405.190 79.105 ;
        RECT 406.010 78.770 406.150 79.105 ;
        RECT 406.970 78.770 407.110 79.105 ;
        RECT 407.930 78.770 408.070 79.105 ;
        RECT 408.890 78.770 409.030 79.105 ;
        RECT 409.850 78.770 409.990 79.105 ;
        RECT 410.810 78.770 410.950 79.105 ;
        RECT 411.770 78.770 411.910 79.105 ;
        RECT 412.730 78.770 412.870 79.105 ;
        RECT 413.690 78.770 413.830 79.105 ;
        RECT 414.650 78.770 414.790 79.105 ;
        RECT 415.610 78.770 415.750 79.105 ;
        RECT 416.570 78.770 416.710 79.105 ;
        RECT 417.530 78.770 417.670 79.105 ;
        RECT 418.490 78.770 418.630 79.105 ;
        RECT 419.450 78.770 427.270 79.105 ;
        RECT 428.090 78.770 437.830 79.105 ;
        RECT 438.650 78.770 438.790 79.105 ;
        RECT 439.610 78.770 439.750 79.105 ;
        RECT 440.570 78.770 440.710 79.105 ;
        RECT 441.530 78.770 441.670 79.105 ;
        RECT 442.490 78.770 442.630 79.105 ;
        RECT 443.450 78.770 443.590 79.105 ;
        RECT 444.410 78.770 444.550 79.105 ;
        RECT 445.370 78.770 445.510 79.105 ;
        RECT 446.330 78.770 446.470 79.105 ;
        RECT 447.290 78.770 447.430 79.105 ;
        RECT 448.250 78.770 448.390 79.105 ;
        RECT 449.210 78.770 449.350 79.105 ;
        RECT 450.170 78.770 450.310 79.105 ;
        RECT 451.130 78.770 451.270 79.105 ;
        RECT 452.090 78.770 452.230 79.105 ;
        RECT 453.050 78.770 453.190 79.105 ;
        RECT 454.010 78.770 454.150 79.105 ;
        RECT 454.970 78.770 455.110 79.105 ;
        RECT 455.930 78.770 456.070 79.105 ;
        RECT 456.890 78.770 467.590 79.105 ;
        RECT 468.410 78.770 469.510 79.105 ;
        RECT 470.330 78.770 471.430 79.105 ;
        RECT 472.250 78.770 473.350 79.105 ;
        RECT 474.170 78.770 478.150 79.105 ;
        RECT 478.970 78.770 479.110 79.105 ;
        RECT 479.930 78.770 480.070 79.105 ;
        RECT 480.890 78.770 481.030 79.105 ;
        RECT 481.850 78.770 481.990 79.105 ;
        RECT 482.810 78.770 482.950 79.105 ;
        RECT 483.770 78.770 483.910 79.105 ;
        RECT 484.730 78.770 484.870 79.105 ;
        RECT 485.690 78.770 492.550 79.105 ;
        RECT 493.370 78.770 493.510 79.105 ;
        RECT 494.330 78.770 494.470 79.105 ;
        RECT 495.290 78.770 495.430 79.105 ;
        RECT 496.250 78.770 496.390 79.105 ;
        RECT 497.210 78.770 497.350 79.105 ;
        RECT 498.170 78.770 498.310 79.105 ;
        RECT 499.130 78.770 499.270 79.105 ;
        RECT 500.090 78.770 510.790 79.105 ;
        RECT 511.610 78.770 511.750 79.105 ;
        RECT 512.570 78.770 512.710 79.105 ;
        RECT 513.530 78.770 513.670 79.105 ;
        RECT 514.490 78.770 514.630 79.105 ;
        RECT 515.450 78.770 515.590 79.105 ;
        RECT 516.410 78.770 516.550 79.105 ;
        RECT 517.370 78.770 517.510 79.105 ;
        RECT 518.330 78.770 518.470 79.105 ;
        RECT 519.290 78.770 519.430 79.105 ;
        RECT 520.250 78.770 520.390 79.105 ;
        RECT 521.210 78.770 521.350 79.105 ;
        RECT 522.170 78.770 522.310 79.105 ;
        RECT 523.130 78.770 523.270 79.105 ;
        RECT 524.090 78.770 524.230 79.105 ;
        RECT 525.050 78.770 525.190 79.105 ;
        RECT 526.010 78.770 540.550 79.105 ;
        RECT 541.370 78.770 541.510 79.105 ;
        RECT 542.330 78.770 542.470 79.105 ;
        RECT 543.290 78.770 543.430 79.105 ;
        RECT 544.250 78.770 544.390 79.105 ;
        RECT 545.210 78.770 545.350 79.105 ;
        RECT 546.170 78.770 546.310 79.105 ;
        RECT 547.130 78.770 547.270 79.105 ;
        RECT 548.090 78.770 548.230 79.105 ;
        RECT 549.050 78.770 549.190 79.105 ;
        RECT 550.010 78.770 550.150 79.105 ;
        RECT 550.970 78.770 551.110 79.105 ;
        RECT 551.930 78.770 552.070 79.105 ;
        RECT 552.890 78.770 553.030 79.105 ;
        RECT 553.850 78.770 553.990 79.105 ;
        RECT 554.810 78.770 554.950 79.105 ;
        RECT 555.770 78.770 563.590 79.105 ;
        RECT 564.410 78.770 565.510 79.105 ;
        RECT 566.330 78.770 567.430 79.105 ;
        RECT 568.250 78.770 569.350 79.105 ;
        RECT 570.170 78.770 571.270 79.105 ;
        RECT 572.090 78.770 573.190 79.105 ;
        RECT 574.010 78.770 575.110 79.105 ;
        RECT 575.930 78.770 577.030 79.105 ;
        RECT 577.850 78.770 578.950 79.105 ;
        RECT 579.770 78.770 580.870 79.105 ;
        RECT 581.690 78.770 582.790 79.105 ;
        RECT 583.610 78.770 584.710 79.105 ;
        RECT 585.530 78.770 589.510 79.105 ;
        RECT 590.330 78.770 590.470 79.105 ;
        RECT 591.290 78.770 591.430 79.105 ;
        RECT 592.250 78.770 592.390 79.105 ;
        RECT 593.210 78.770 593.350 79.105 ;
        RECT 594.170 78.770 594.310 79.105 ;
        RECT 595.130 78.770 595.270 79.105 ;
        RECT 596.090 78.770 596.230 79.105 ;
        RECT 597.050 78.770 607.750 79.105 ;
        RECT 608.570 78.770 608.710 79.105 ;
        RECT 609.530 78.770 609.670 79.105 ;
        RECT 610.490 78.770 610.630 79.105 ;
        RECT 611.450 78.770 611.590 79.105 ;
        RECT 612.410 78.770 612.550 79.105 ;
        RECT 613.370 78.770 613.510 79.105 ;
        RECT 614.330 78.770 614.470 79.105 ;
        RECT 615.290 78.770 615.430 79.105 ;
        RECT 616.250 78.770 616.390 79.105 ;
        RECT 617.210 78.770 617.350 79.105 ;
        RECT 618.170 78.770 618.310 79.105 ;
        RECT 619.130 78.770 619.270 79.105 ;
        RECT 620.090 78.770 620.230 79.105 ;
        RECT 621.050 78.770 621.190 79.105 ;
        RECT 622.010 78.770 622.150 79.105 ;
        RECT 622.970 78.770 637.510 79.105 ;
        RECT 638.330 78.770 638.470 79.105 ;
        RECT 639.290 78.770 639.430 79.105 ;
        RECT 640.250 78.770 640.390 79.105 ;
        RECT 641.210 78.770 641.350 79.105 ;
        RECT 642.170 78.770 642.310 79.105 ;
        RECT 643.130 78.770 643.270 79.105 ;
        RECT 644.090 78.770 644.230 79.105 ;
        RECT 645.050 78.770 645.190 79.105 ;
        RECT 646.010 78.770 646.150 79.105 ;
        RECT 646.970 78.770 647.110 79.105 ;
        RECT 647.930 78.770 648.070 79.105 ;
        RECT 648.890 78.770 649.030 79.105 ;
        RECT 649.850 78.770 649.990 79.105 ;
        RECT 650.810 78.770 650.950 79.105 ;
        RECT 651.770 78.770 651.910 79.105 ;
        RECT 652.730 78.770 660.550 79.105 ;
        RECT 661.370 78.770 671.110 79.105 ;
        RECT 671.930 78.770 672.070 79.105 ;
        RECT 672.890 78.770 673.030 79.105 ;
        RECT 673.850 78.770 673.990 79.105 ;
        RECT 674.810 78.770 674.950 79.105 ;
        RECT 675.770 78.770 675.910 79.105 ;
        RECT 676.730 78.770 676.870 79.105 ;
        RECT 677.690 78.770 677.830 79.105 ;
        RECT 678.650 78.770 678.790 79.105 ;
        RECT 679.610 78.770 679.750 79.105 ;
        RECT 680.570 78.770 680.710 79.105 ;
        RECT 681.530 78.770 681.670 79.105 ;
        RECT 682.490 78.770 682.630 79.105 ;
        RECT 683.450 78.770 683.590 79.105 ;
        RECT 684.410 78.770 684.550 79.105 ;
        RECT 685.370 78.770 685.510 79.105 ;
        RECT 686.330 78.770 686.470 79.105 ;
        RECT 687.290 78.770 687.430 79.105 ;
        RECT 688.250 78.770 688.390 79.105 ;
        RECT 689.210 78.770 689.350 79.105 ;
        RECT 690.170 78.770 700.870 79.105 ;
        RECT 701.690 78.770 702.790 79.105 ;
        RECT 703.610 78.770 704.710 79.105 ;
        RECT 705.530 78.770 706.630 79.105 ;
        RECT 707.450 78.770 711.430 79.105 ;
        RECT 712.250 78.770 712.390 79.105 ;
        RECT 713.210 78.770 713.350 79.105 ;
        RECT 714.170 78.770 714.310 79.105 ;
        RECT 715.130 78.770 715.270 79.105 ;
        RECT 716.090 78.770 716.230 79.105 ;
        RECT 717.050 78.770 717.190 79.105 ;
        RECT 718.010 78.770 718.150 79.105 ;
        RECT 718.970 78.770 725.830 79.105 ;
        RECT 726.650 78.770 726.790 79.105 ;
        RECT 727.610 78.770 727.750 79.105 ;
        RECT 728.570 78.770 728.710 79.105 ;
        RECT 729.530 78.770 729.670 79.105 ;
        RECT 730.490 78.770 730.630 79.105 ;
        RECT 731.450 78.770 731.590 79.105 ;
        RECT 732.410 78.770 732.550 79.105 ;
        RECT 733.370 78.770 744.070 79.105 ;
        RECT 744.890 78.770 745.030 79.105 ;
        RECT 745.850 78.770 745.990 79.105 ;
        RECT 746.810 78.770 746.950 79.105 ;
        RECT 747.770 78.770 747.910 79.105 ;
        RECT 748.730 78.770 748.870 79.105 ;
        RECT 749.690 78.770 749.830 79.105 ;
        RECT 750.650 78.770 750.790 79.105 ;
        RECT 751.610 78.770 751.750 79.105 ;
        RECT 752.570 78.770 752.710 79.105 ;
        RECT 753.530 78.770 753.670 79.105 ;
        RECT 754.490 78.770 754.630 79.105 ;
        RECT 755.450 78.770 755.590 79.105 ;
        RECT 756.410 78.770 756.550 79.105 ;
        RECT 757.370 78.770 757.510 79.105 ;
        RECT 758.330 78.770 758.470 79.105 ;
        RECT 759.290 78.770 773.830 79.105 ;
        RECT 774.650 78.770 774.790 79.105 ;
        RECT 775.610 78.770 775.750 79.105 ;
        RECT 776.570 78.770 776.710 79.105 ;
        RECT 777.530 78.770 777.670 79.105 ;
        RECT 778.490 78.770 778.630 79.105 ;
        RECT 779.450 78.770 779.590 79.105 ;
        RECT 780.410 78.770 780.550 79.105 ;
        RECT 781.370 78.770 781.510 79.105 ;
        RECT 782.330 78.770 782.470 79.105 ;
        RECT 783.290 78.770 783.430 79.105 ;
        RECT 784.250 78.770 784.390 79.105 ;
        RECT 785.210 78.770 785.350 79.105 ;
        RECT 786.170 78.770 786.310 79.105 ;
        RECT 787.130 78.770 787.270 79.105 ;
        RECT 788.090 78.770 788.230 79.105 ;
        RECT 789.050 78.770 796.870 79.105 ;
        RECT 797.690 78.770 798.790 79.105 ;
        RECT 799.610 78.770 800.710 79.105 ;
        RECT 801.530 78.770 802.630 79.105 ;
        RECT 803.450 78.770 804.550 79.105 ;
        RECT 805.370 78.770 806.470 79.105 ;
        RECT 807.290 78.770 808.390 79.105 ;
        RECT 809.210 78.770 810.310 79.105 ;
        RECT 811.130 78.770 812.230 79.105 ;
        RECT 813.050 78.770 814.150 79.105 ;
        RECT 814.970 78.770 816.070 79.105 ;
        RECT 816.890 78.770 817.990 79.105 ;
        RECT 818.810 78.770 822.790 79.105 ;
        RECT 823.610 78.770 823.750 79.105 ;
        RECT 824.570 78.770 824.710 79.105 ;
        RECT 825.530 78.770 825.670 79.105 ;
        RECT 826.490 78.770 826.630 79.105 ;
        RECT 827.450 78.770 827.590 79.105 ;
        RECT 828.410 78.770 828.550 79.105 ;
        RECT 829.370 78.770 829.510 79.105 ;
        RECT 830.330 78.770 841.030 79.105 ;
        RECT 841.850 78.770 841.990 79.105 ;
        RECT 842.810 78.770 842.950 79.105 ;
        RECT 843.770 78.770 843.910 79.105 ;
        RECT 844.730 78.770 844.870 79.105 ;
        RECT 845.690 78.770 845.830 79.105 ;
        RECT 846.650 78.770 846.790 79.105 ;
        RECT 847.610 78.770 847.750 79.105 ;
        RECT 848.570 78.770 848.710 79.105 ;
        RECT 849.530 78.770 849.670 79.105 ;
        RECT 850.490 78.770 850.630 79.105 ;
        RECT 851.450 78.770 851.590 79.105 ;
        RECT 852.410 78.770 852.550 79.105 ;
        RECT 853.370 78.770 853.510 79.105 ;
        RECT 854.330 78.770 854.470 79.105 ;
        RECT 855.290 78.770 855.430 79.105 ;
        RECT 856.250 78.770 870.790 79.105 ;
        RECT 871.610 78.770 871.750 79.105 ;
        RECT 872.570 78.770 872.710 79.105 ;
        RECT 873.530 78.770 873.670 79.105 ;
        RECT 874.490 78.770 874.630 79.105 ;
        RECT 875.450 78.770 875.590 79.105 ;
        RECT 876.410 78.770 876.550 79.105 ;
        RECT 877.370 78.770 877.510 79.105 ;
        RECT 878.330 78.770 878.470 79.105 ;
        RECT 879.290 78.770 879.430 79.105 ;
        RECT 880.250 78.770 880.390 79.105 ;
        RECT 881.210 78.770 881.350 79.105 ;
        RECT 882.170 78.770 882.310 79.105 ;
        RECT 883.130 78.770 883.270 79.105 ;
        RECT 884.090 78.770 884.230 79.105 ;
        RECT 885.050 78.770 885.190 79.105 ;
        RECT 886.010 78.770 893.830 79.105 ;
        RECT 894.650 78.770 904.390 79.105 ;
        RECT 905.210 78.770 905.350 79.105 ;
        RECT 906.170 78.770 906.310 79.105 ;
        RECT 907.130 78.770 907.270 79.105 ;
        RECT 908.090 78.770 908.230 79.105 ;
        RECT 909.050 78.770 909.190 79.105 ;
        RECT 910.010 78.770 910.150 79.105 ;
        RECT 910.970 78.770 911.110 79.105 ;
        RECT 911.930 78.770 912.070 79.105 ;
        RECT 912.890 78.770 913.030 79.105 ;
        RECT 913.850 78.770 913.990 79.105 ;
        RECT 914.810 78.770 914.950 79.105 ;
        RECT 915.770 78.770 915.910 79.105 ;
        RECT 916.730 78.770 916.870 79.105 ;
        RECT 917.690 78.770 917.830 79.105 ;
        RECT 918.650 78.770 918.790 79.105 ;
        RECT 919.610 78.770 919.750 79.105 ;
        RECT 920.570 78.770 920.710 79.105 ;
        RECT 921.530 78.770 921.670 79.105 ;
        RECT 922.490 78.770 922.630 79.105 ;
        RECT 923.450 78.770 934.150 79.105 ;
        RECT 934.970 78.770 936.070 79.105 ;
        RECT 936.890 78.770 937.990 79.105 ;
        RECT 938.810 78.770 939.910 79.105 ;
        RECT 940.730 78.770 944.710 79.105 ;
        RECT 945.530 78.770 945.670 79.105 ;
        RECT 946.490 78.770 946.630 79.105 ;
        RECT 947.450 78.770 947.590 79.105 ;
        RECT 948.410 78.770 948.550 79.105 ;
        RECT 949.370 78.770 949.510 79.105 ;
        RECT 950.330 78.770 950.470 79.105 ;
        RECT 951.290 78.770 951.430 79.105 ;
        RECT 952.250 78.770 959.110 79.105 ;
        RECT 959.930 78.770 960.070 79.105 ;
        RECT 960.890 78.770 961.030 79.105 ;
        RECT 961.850 78.770 961.990 79.105 ;
        RECT 962.810 78.770 962.950 79.105 ;
        RECT 963.770 78.770 963.910 79.105 ;
        RECT 964.730 78.770 964.870 79.105 ;
        RECT 965.690 78.770 965.830 79.105 ;
        RECT 966.650 78.770 977.350 79.105 ;
        RECT 978.170 78.770 978.310 79.105 ;
        RECT 979.130 78.770 979.270 79.105 ;
        RECT 980.090 78.770 980.230 79.105 ;
        RECT 981.050 78.770 981.190 79.105 ;
        RECT 982.010 78.770 982.150 79.105 ;
        RECT 982.970 78.770 983.110 79.105 ;
        RECT 983.930 78.770 984.070 79.105 ;
        RECT 984.890 78.770 985.030 79.105 ;
        RECT 985.850 78.770 985.990 79.105 ;
        RECT 986.810 78.770 986.950 79.105 ;
        RECT 987.770 78.770 987.910 79.105 ;
        RECT 988.730 78.770 988.870 79.105 ;
        RECT 989.690 78.770 989.830 79.105 ;
        RECT 990.650 78.770 990.790 79.105 ;
        RECT 991.610 78.770 991.750 79.105 ;
        RECT 992.570 78.770 1007.110 79.105 ;
        RECT 1007.930 78.770 1008.070 79.105 ;
        RECT 1008.890 78.770 1009.030 79.105 ;
        RECT 1009.850 78.770 1009.990 79.105 ;
        RECT 1010.810 78.770 1010.950 79.105 ;
        RECT 1011.770 78.770 1011.910 79.105 ;
        RECT 1012.730 78.770 1012.870 79.105 ;
        RECT 1013.690 78.770 1013.830 79.105 ;
        RECT 1014.650 78.770 1014.790 79.105 ;
        RECT 1015.610 78.770 1015.750 79.105 ;
        RECT 1016.570 78.770 1016.710 79.105 ;
        RECT 1017.530 78.770 1017.670 79.105 ;
        RECT 1018.490 78.770 1018.630 79.105 ;
        RECT 1019.450 78.770 1019.590 79.105 ;
        RECT 1020.410 78.770 1020.550 79.105 ;
        RECT 1021.370 78.770 1021.510 79.105 ;
        RECT 1022.330 78.770 1030.150 79.105 ;
        RECT 1030.970 78.770 1032.070 79.105 ;
        RECT 1032.890 78.770 1033.990 79.105 ;
        RECT 1034.810 78.770 1035.910 79.105 ;
        RECT 1036.730 78.770 1037.830 79.105 ;
        RECT 1038.650 78.770 1039.750 79.105 ;
        RECT 1040.570 78.770 1041.670 79.105 ;
        RECT 1042.490 78.770 1043.590 79.105 ;
        RECT 1044.410 78.770 1045.510 79.105 ;
        RECT 1046.330 78.770 1047.430 79.105 ;
        RECT 1048.250 78.770 1049.350 79.105 ;
        RECT 1050.170 78.770 1051.270 79.105 ;
        RECT 1052.090 78.770 1056.070 79.105 ;
        RECT 1056.890 78.770 1057.030 79.105 ;
        RECT 1057.850 78.770 1057.990 79.105 ;
        RECT 1058.810 78.770 1058.950 79.105 ;
        RECT 1059.770 78.770 1059.910 79.105 ;
        RECT 1060.730 78.770 1060.870 79.105 ;
        RECT 1061.690 78.770 1061.830 79.105 ;
        RECT 1062.650 78.770 1062.790 79.105 ;
        RECT 1063.610 78.770 1074.310 79.105 ;
        RECT 1075.130 78.770 1075.270 79.105 ;
        RECT 1076.090 78.770 1076.230 79.105 ;
        RECT 1077.050 78.770 1077.190 79.105 ;
        RECT 1078.010 78.770 1078.150 79.105 ;
        RECT 1078.970 78.770 1079.110 79.105 ;
        RECT 1079.930 78.770 1080.070 79.105 ;
        RECT 1080.890 78.770 1081.030 79.105 ;
        RECT 1081.850 78.770 1081.990 79.105 ;
        RECT 1082.810 78.770 1082.950 79.105 ;
        RECT 1083.770 78.770 1083.910 79.105 ;
        RECT 1084.730 78.770 1084.870 79.105 ;
        RECT 1085.690 78.770 1085.830 79.105 ;
        RECT 1086.650 78.770 1086.790 79.105 ;
        RECT 1087.610 78.770 1087.750 79.105 ;
        RECT 1088.570 78.770 1088.710 79.105 ;
        RECT 1089.530 78.770 1104.070 79.105 ;
        RECT 1104.890 78.770 1105.030 79.105 ;
        RECT 1105.850 78.770 1105.990 79.105 ;
        RECT 1106.810 78.770 1106.950 79.105 ;
        RECT 1107.770 78.770 1107.910 79.105 ;
        RECT 1108.730 78.770 1108.870 79.105 ;
        RECT 1109.690 78.770 1109.830 79.105 ;
        RECT 1110.650 78.770 1110.790 79.105 ;
        RECT 1111.610 78.770 1111.750 79.105 ;
        RECT 1112.570 78.770 1112.710 79.105 ;
        RECT 1113.530 78.770 1113.670 79.105 ;
        RECT 1114.490 78.770 1114.630 79.105 ;
        RECT 1115.450 78.770 1115.590 79.105 ;
        RECT 1116.410 78.770 1116.550 79.105 ;
        RECT 1117.370 78.770 1117.510 79.105 ;
        RECT 1118.330 78.770 1118.470 79.105 ;
        RECT 1119.290 78.770 1127.110 79.105 ;
        RECT 1127.930 78.770 1137.670 79.105 ;
        RECT 1138.490 78.770 1138.630 79.105 ;
        RECT 1139.450 78.770 1139.590 79.105 ;
        RECT 1140.410 78.770 1140.550 79.105 ;
        RECT 1141.370 78.770 1141.510 79.105 ;
        RECT 1142.330 78.770 1142.470 79.105 ;
        RECT 1143.290 78.770 1143.430 79.105 ;
        RECT 1144.250 78.770 1144.390 79.105 ;
        RECT 1145.210 78.770 1145.350 79.105 ;
        RECT 1146.170 78.770 1146.310 79.105 ;
        RECT 1147.130 78.770 1147.270 79.105 ;
        RECT 1148.090 78.770 1148.230 79.105 ;
        RECT 1149.050 78.770 1149.190 79.105 ;
        RECT 1150.010 78.770 1150.150 79.105 ;
        RECT 1150.970 78.770 1151.110 79.105 ;
        RECT 1151.930 78.770 1152.070 79.105 ;
        RECT 1152.890 78.770 1153.030 79.105 ;
        RECT 1153.850 78.770 1153.990 79.105 ;
        RECT 1154.810 78.770 1154.950 79.105 ;
        RECT 1155.770 78.770 1155.910 79.105 ;
        RECT 1156.730 78.770 1166.025 79.105 ;
        RECT 0.375 0.610 1166.025 78.770 ;
        RECT 0.375 0.275 6.790 0.610 ;
        RECT 7.610 0.275 18.310 0.610 ;
        RECT 19.130 0.275 29.830 0.610 ;
        RECT 30.650 0.275 41.350 0.610 ;
        RECT 42.170 0.275 52.870 0.610 ;
        RECT 53.690 0.275 64.390 0.610 ;
        RECT 65.210 0.275 75.910 0.610 ;
        RECT 76.730 0.275 87.430 0.610 ;
        RECT 88.250 0.275 98.950 0.610 ;
        RECT 99.770 0.275 110.470 0.610 ;
        RECT 111.290 0.275 121.990 0.610 ;
        RECT 122.810 0.275 133.510 0.610 ;
        RECT 134.330 0.275 145.030 0.610 ;
        RECT 145.850 0.275 156.550 0.610 ;
        RECT 157.370 0.275 168.070 0.610 ;
        RECT 168.890 0.275 179.590 0.610 ;
        RECT 180.410 0.275 191.110 0.610 ;
        RECT 191.930 0.275 202.630 0.610 ;
        RECT 203.450 0.275 214.150 0.610 ;
        RECT 214.970 0.275 225.670 0.610 ;
        RECT 226.490 0.275 240.070 0.610 ;
        RECT 240.890 0.275 251.590 0.610 ;
        RECT 252.410 0.275 263.110 0.610 ;
        RECT 263.930 0.275 274.630 0.610 ;
        RECT 275.450 0.275 286.150 0.610 ;
        RECT 286.970 0.275 297.670 0.610 ;
        RECT 298.490 0.275 309.190 0.610 ;
        RECT 310.010 0.275 320.710 0.610 ;
        RECT 321.530 0.275 332.230 0.610 ;
        RECT 333.050 0.275 343.750 0.610 ;
        RECT 344.570 0.275 355.270 0.610 ;
        RECT 356.090 0.275 366.790 0.610 ;
        RECT 367.610 0.275 378.310 0.610 ;
        RECT 379.130 0.275 389.830 0.610 ;
        RECT 390.650 0.275 401.350 0.610 ;
        RECT 402.170 0.275 412.870 0.610 ;
        RECT 413.690 0.275 424.390 0.610 ;
        RECT 425.210 0.275 435.910 0.610 ;
        RECT 436.730 0.275 447.430 0.610 ;
        RECT 448.250 0.275 458.950 0.610 ;
        RECT 459.770 0.275 473.350 0.610 ;
        RECT 474.170 0.275 484.870 0.610 ;
        RECT 485.690 0.275 496.390 0.610 ;
        RECT 497.210 0.275 507.910 0.610 ;
        RECT 508.730 0.275 519.430 0.610 ;
        RECT 520.250 0.275 530.950 0.610 ;
        RECT 531.770 0.275 542.470 0.610 ;
        RECT 543.290 0.275 553.990 0.610 ;
        RECT 554.810 0.275 565.510 0.610 ;
        RECT 566.330 0.275 577.030 0.610 ;
        RECT 577.850 0.275 588.550 0.610 ;
        RECT 589.370 0.275 600.070 0.610 ;
        RECT 600.890 0.275 611.590 0.610 ;
        RECT 612.410 0.275 623.110 0.610 ;
        RECT 623.930 0.275 634.630 0.610 ;
        RECT 635.450 0.275 646.150 0.610 ;
        RECT 646.970 0.275 657.670 0.610 ;
        RECT 658.490 0.275 669.190 0.610 ;
        RECT 670.010 0.275 680.710 0.610 ;
        RECT 681.530 0.275 692.230 0.610 ;
        RECT 693.050 0.275 706.630 0.610 ;
        RECT 707.450 0.275 718.150 0.610 ;
        RECT 718.970 0.275 729.670 0.610 ;
        RECT 730.490 0.275 741.190 0.610 ;
        RECT 742.010 0.275 752.710 0.610 ;
        RECT 753.530 0.275 764.230 0.610 ;
        RECT 765.050 0.275 775.750 0.610 ;
        RECT 776.570 0.275 787.270 0.610 ;
        RECT 788.090 0.275 798.790 0.610 ;
        RECT 799.610 0.275 810.310 0.610 ;
        RECT 811.130 0.275 821.830 0.610 ;
        RECT 822.650 0.275 833.350 0.610 ;
        RECT 834.170 0.275 844.870 0.610 ;
        RECT 845.690 0.275 856.390 0.610 ;
        RECT 857.210 0.275 867.910 0.610 ;
        RECT 868.730 0.275 879.430 0.610 ;
        RECT 880.250 0.275 890.950 0.610 ;
        RECT 891.770 0.275 902.470 0.610 ;
        RECT 903.290 0.275 913.990 0.610 ;
        RECT 914.810 0.275 925.510 0.610 ;
        RECT 926.330 0.275 937.990 0.610 ;
        RECT 938.810 0.275 939.910 0.610 ;
        RECT 940.730 0.275 941.830 0.610 ;
        RECT 942.650 0.275 943.750 0.610 ;
        RECT 944.570 0.275 945.670 0.610 ;
        RECT 946.490 0.275 947.590 0.610 ;
        RECT 948.410 0.275 949.510 0.610 ;
        RECT 950.330 0.275 951.430 0.610 ;
        RECT 952.250 0.275 953.350 0.610 ;
        RECT 954.170 0.275 955.270 0.610 ;
        RECT 956.090 0.275 957.190 0.610 ;
        RECT 958.010 0.275 959.110 0.610 ;
        RECT 959.930 0.275 961.030 0.610 ;
        RECT 961.850 0.275 962.950 0.610 ;
        RECT 963.770 0.275 964.870 0.610 ;
        RECT 965.690 0.275 966.790 0.610 ;
        RECT 967.610 0.275 968.710 0.610 ;
        RECT 969.530 0.275 970.630 0.610 ;
        RECT 971.450 0.275 972.550 0.610 ;
        RECT 973.370 0.275 974.470 0.610 ;
        RECT 975.290 0.275 993.670 0.610 ;
        RECT 994.490 0.275 995.590 0.610 ;
        RECT 996.410 0.275 997.510 0.610 ;
        RECT 998.330 0.275 999.430 0.610 ;
        RECT 1000.250 0.275 1001.350 0.610 ;
        RECT 1002.170 0.275 1003.270 0.610 ;
        RECT 1004.090 0.275 1005.190 0.610 ;
        RECT 1006.010 0.275 1007.110 0.610 ;
        RECT 1007.930 0.275 1009.030 0.610 ;
        RECT 1009.850 0.275 1010.950 0.610 ;
        RECT 1011.770 0.275 1012.870 0.610 ;
        RECT 1013.690 0.275 1014.790 0.610 ;
        RECT 1015.610 0.275 1016.710 0.610 ;
        RECT 1017.530 0.275 1018.630 0.610 ;
        RECT 1019.450 0.275 1020.550 0.610 ;
        RECT 1021.370 0.275 1022.470 0.610 ;
        RECT 1023.290 0.275 1024.390 0.610 ;
        RECT 1025.210 0.275 1026.310 0.610 ;
        RECT 1027.130 0.275 1028.230 0.610 ;
        RECT 1029.050 0.275 1030.150 0.610 ;
        RECT 1030.970 0.275 1032.070 0.610 ;
        RECT 1032.890 0.275 1033.990 0.610 ;
        RECT 1034.810 0.275 1035.910 0.610 ;
        RECT 1036.730 0.275 1037.830 0.610 ;
        RECT 1038.650 0.275 1039.750 0.610 ;
        RECT 1040.570 0.275 1041.670 0.610 ;
        RECT 1042.490 0.275 1043.590 0.610 ;
        RECT 1044.410 0.275 1045.510 0.610 ;
        RECT 1046.330 0.275 1047.430 0.610 ;
        RECT 1048.250 0.275 1049.350 0.610 ;
        RECT 1050.170 0.275 1051.270 0.610 ;
        RECT 1052.090 0.275 1053.190 0.610 ;
        RECT 1054.010 0.275 1055.110 0.610 ;
        RECT 1055.930 0.275 1057.030 0.610 ;
        RECT 1057.850 0.275 1058.950 0.610 ;
        RECT 1059.770 0.275 1060.870 0.610 ;
        RECT 1061.690 0.275 1062.790 0.610 ;
        RECT 1063.610 0.275 1064.710 0.610 ;
        RECT 1065.530 0.275 1066.630 0.610 ;
        RECT 1067.450 0.275 1068.550 0.610 ;
        RECT 1069.370 0.275 1070.470 0.610 ;
        RECT 1071.290 0.275 1072.390 0.610 ;
        RECT 1073.210 0.275 1074.310 0.610 ;
        RECT 1075.130 0.275 1076.230 0.610 ;
        RECT 1077.050 0.275 1078.150 0.610 ;
        RECT 1078.970 0.275 1080.070 0.610 ;
        RECT 1080.890 0.275 1081.990 0.610 ;
        RECT 1082.810 0.275 1083.910 0.610 ;
        RECT 1084.730 0.275 1085.830 0.610 ;
        RECT 1086.650 0.275 1087.750 0.610 ;
        RECT 1088.570 0.275 1089.670 0.610 ;
        RECT 1090.490 0.275 1091.590 0.610 ;
        RECT 1092.410 0.275 1093.510 0.610 ;
        RECT 1094.330 0.275 1095.430 0.610 ;
        RECT 1096.250 0.275 1097.350 0.610 ;
        RECT 1098.170 0.275 1099.270 0.610 ;
        RECT 1100.090 0.275 1101.190 0.610 ;
        RECT 1102.010 0.275 1103.110 0.610 ;
        RECT 1103.930 0.275 1105.030 0.610 ;
        RECT 1105.850 0.275 1106.950 0.610 ;
        RECT 1107.770 0.275 1108.870 0.610 ;
        RECT 1109.690 0.275 1110.790 0.610 ;
        RECT 1111.610 0.275 1112.710 0.610 ;
        RECT 1113.530 0.275 1114.630 0.610 ;
        RECT 1115.450 0.275 1116.550 0.610 ;
        RECT 1117.370 0.275 1118.470 0.610 ;
        RECT 1119.290 0.275 1120.390 0.610 ;
        RECT 1121.210 0.275 1122.310 0.610 ;
        RECT 1123.130 0.275 1124.230 0.610 ;
        RECT 1125.050 0.275 1126.150 0.610 ;
        RECT 1126.970 0.275 1128.070 0.610 ;
        RECT 1128.890 0.275 1129.990 0.610 ;
        RECT 1130.810 0.275 1131.910 0.610 ;
        RECT 1132.730 0.275 1133.830 0.610 ;
        RECT 1134.650 0.275 1135.750 0.610 ;
        RECT 1136.570 0.275 1137.670 0.610 ;
        RECT 1138.490 0.275 1139.590 0.610 ;
        RECT 1140.410 0.275 1141.510 0.610 ;
        RECT 1142.330 0.275 1143.430 0.610 ;
        RECT 1144.250 0.275 1145.350 0.610 ;
        RECT 1146.170 0.275 1147.270 0.610 ;
        RECT 1148.090 0.275 1149.190 0.610 ;
        RECT 1150.010 0.275 1151.110 0.610 ;
        RECT 1151.930 0.275 1166.025 0.610 ;
      LAYER Metal3 ;
        RECT 0.335 68.030 1166.065 79.065 ;
        RECT 0.610 67.210 1165.790 68.030 ;
        RECT 0.335 66.350 1166.065 67.210 ;
        RECT 0.610 65.530 1165.790 66.350 ;
        RECT 0.335 64.670 1166.065 65.530 ;
        RECT 0.610 63.850 1165.790 64.670 ;
        RECT 0.335 62.990 1166.065 63.850 ;
        RECT 0.610 62.170 1165.790 62.990 ;
        RECT 0.335 61.310 1166.065 62.170 ;
        RECT 0.610 60.490 1165.790 61.310 ;
        RECT 0.335 59.630 1166.065 60.490 ;
        RECT 0.610 58.810 1165.790 59.630 ;
        RECT 0.335 57.950 1166.065 58.810 ;
        RECT 0.610 57.130 1165.790 57.950 ;
        RECT 0.335 56.270 1166.065 57.130 ;
        RECT 0.610 55.450 1165.790 56.270 ;
        RECT 0.335 54.590 1166.065 55.450 ;
        RECT 0.610 53.770 1165.790 54.590 ;
        RECT 0.335 52.910 1166.065 53.770 ;
        RECT 0.610 52.090 1165.790 52.910 ;
        RECT 0.335 51.230 1166.065 52.090 ;
        RECT 0.610 50.410 1165.790 51.230 ;
        RECT 0.335 49.550 1166.065 50.410 ;
        RECT 0.610 48.730 1165.790 49.550 ;
        RECT 0.335 47.870 1166.065 48.730 ;
        RECT 0.610 47.050 1165.790 47.870 ;
        RECT 0.335 46.190 1166.065 47.050 ;
        RECT 0.610 45.370 1165.790 46.190 ;
        RECT 0.335 44.510 1166.065 45.370 ;
        RECT 0.610 43.690 1165.790 44.510 ;
        RECT 0.335 42.830 1166.065 43.690 ;
        RECT 0.610 42.010 1165.790 42.830 ;
        RECT 0.335 41.150 1166.065 42.010 ;
        RECT 0.610 40.330 1165.790 41.150 ;
        RECT 0.335 39.470 1166.065 40.330 ;
        RECT 0.610 38.650 1165.790 39.470 ;
        RECT 0.335 37.790 1166.065 38.650 ;
        RECT 0.610 36.970 1165.790 37.790 ;
        RECT 0.335 36.110 1166.065 36.970 ;
        RECT 0.610 35.290 1165.790 36.110 ;
        RECT 0.335 34.430 1166.065 35.290 ;
        RECT 0.610 33.610 1165.790 34.430 ;
        RECT 0.335 32.750 1166.065 33.610 ;
        RECT 0.610 31.930 1165.790 32.750 ;
        RECT 0.335 31.070 1166.065 31.930 ;
        RECT 0.610 30.250 1165.790 31.070 ;
        RECT 0.335 29.390 1166.065 30.250 ;
        RECT 0.610 28.570 1165.790 29.390 ;
        RECT 0.335 27.710 1166.065 28.570 ;
        RECT 0.610 26.890 1165.790 27.710 ;
        RECT 0.335 26.030 1166.065 26.890 ;
        RECT 0.610 25.210 1165.790 26.030 ;
        RECT 0.335 24.350 1166.065 25.210 ;
        RECT 0.610 23.530 1165.790 24.350 ;
        RECT 0.335 22.670 1166.065 23.530 ;
        RECT 0.610 21.850 1165.790 22.670 ;
        RECT 0.335 20.990 1166.065 21.850 ;
        RECT 0.610 20.170 1165.790 20.990 ;
        RECT 0.335 19.310 1166.065 20.170 ;
        RECT 0.610 18.490 1165.790 19.310 ;
        RECT 0.335 17.630 1166.065 18.490 ;
        RECT 0.610 16.810 1165.790 17.630 ;
        RECT 0.335 15.950 1166.065 16.810 ;
        RECT 0.610 15.130 1165.790 15.950 ;
        RECT 0.335 2.510 1166.065 15.130 ;
        RECT 0.610 1.690 1165.790 2.510 ;
        RECT 0.335 0.315 1166.065 1.690 ;
      LAYER Metal4 ;
        RECT 5.180 0.275 12.170 79.105 ;
        RECT 13.590 0.275 15.170 79.105 ;
        RECT 16.590 0.275 62.170 79.105 ;
        RECT 63.590 0.275 65.170 79.105 ;
        RECT 66.590 0.275 112.170 79.105 ;
        RECT 113.590 0.275 115.170 79.105 ;
        RECT 116.590 0.275 162.170 79.105 ;
        RECT 163.590 0.275 165.170 79.105 ;
        RECT 166.590 0.275 212.170 79.105 ;
        RECT 213.590 0.275 215.170 79.105 ;
        RECT 216.590 0.275 245.450 79.105 ;
        RECT 246.870 0.275 248.450 79.105 ;
        RECT 249.870 0.275 295.450 79.105 ;
        RECT 296.870 0.275 298.450 79.105 ;
        RECT 299.870 0.275 345.450 79.105 ;
        RECT 346.870 0.275 348.450 79.105 ;
        RECT 349.870 0.275 395.450 79.105 ;
        RECT 396.870 0.275 398.450 79.105 ;
        RECT 399.870 0.275 445.450 79.105 ;
        RECT 446.870 0.275 448.450 79.105 ;
        RECT 449.870 0.275 478.730 79.105 ;
        RECT 480.150 0.275 481.730 79.105 ;
        RECT 483.150 0.275 528.730 79.105 ;
        RECT 530.150 0.275 531.730 79.105 ;
        RECT 533.150 0.275 578.730 79.105 ;
        RECT 580.150 0.275 581.730 79.105 ;
        RECT 583.150 0.275 628.730 79.105 ;
        RECT 630.150 0.275 631.730 79.105 ;
        RECT 633.150 0.275 678.730 79.105 ;
        RECT 680.150 0.275 681.730 79.105 ;
        RECT 683.150 0.275 712.010 79.105 ;
        RECT 713.430 0.275 715.010 79.105 ;
        RECT 716.430 0.275 762.010 79.105 ;
        RECT 763.430 0.275 765.010 79.105 ;
        RECT 766.430 0.275 812.010 79.105 ;
        RECT 813.430 0.275 815.010 79.105 ;
        RECT 816.430 0.275 862.010 79.105 ;
        RECT 863.430 0.275 865.010 79.105 ;
        RECT 866.430 0.275 912.010 79.105 ;
        RECT 913.430 0.275 915.010 79.105 ;
        RECT 916.430 0.275 945.290 79.105 ;
        RECT 946.710 0.275 948.290 79.105 ;
        RECT 949.710 0.275 995.290 79.105 ;
        RECT 996.710 0.275 998.290 79.105 ;
        RECT 999.710 0.275 1045.290 79.105 ;
        RECT 1046.710 0.275 1048.290 79.105 ;
        RECT 1049.710 0.275 1095.290 79.105 ;
        RECT 1096.710 0.275 1098.290 79.105 ;
        RECT 1099.710 0.275 1145.290 79.105 ;
        RECT 1146.710 0.275 1148.290 79.105 ;
        RECT 1149.710 0.275 1166.020 79.105 ;
      LAYER TopMetal1 ;
        RECT 16.460 3.100 1160.020 77.700 ;
  END
END NPU_ACCUM_S
END LIBRARY

